VERSION 5.8 ;
BUSBITCHARS "[]" ;
DIVIDERCHAR "/" ;
UNITS
    DATABASE MICRONS 1000 ;
END UNITS

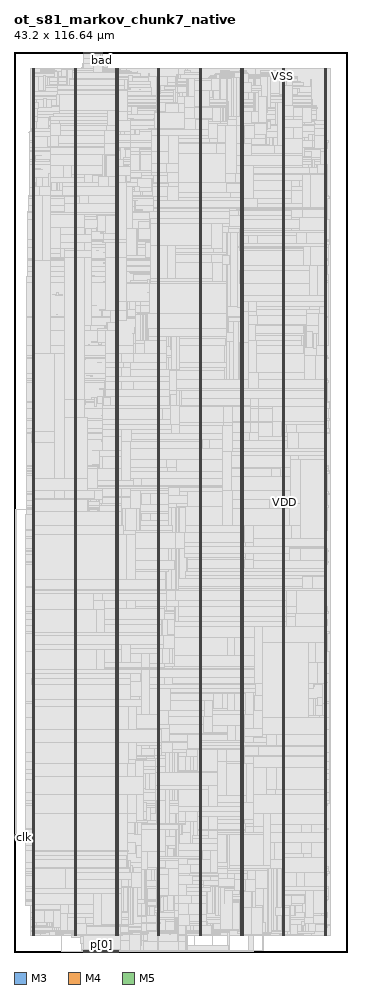
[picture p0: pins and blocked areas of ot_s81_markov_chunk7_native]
MACRO ot_s81_markov_chunk7_native
  FOREIGN ot_s81_markov_chunk7_native 0 0 ;
  CLASS BLOCK ;
  SIZE 43.2 BY 116.64 ;
  PIN bad
    DIRECTION OUTPUT ;
    USE SIGNAL ;
    PORT
      LAYER M3 ;
        RECT  11.448 116.496 11.466 116.64 ;
    END
  END bad
  PIN clk
    DIRECTION INPUT ;
    USE SIGNAL ;
    PORT
      LAYER M4 ;
        RECT  0 14.88 0.192 14.904 ;
    END
  END clk
  PIN p[0]
    DIRECTION INPUT ;
    USE SIGNAL ;
    PORT
      LAYER M3 ;
        RECT  11.304 0 11.322 0.144 ;
    END
  END p[0]
  PIN p[10]
    DIRECTION INPUT ;
    USE SIGNAL ;
    PORT
      LAYER M3 ;
        RECT  12.024 0 12.042 0.144 ;
    END
  END p[10]
  PIN p[11]
    DIRECTION INPUT ;
    USE SIGNAL ;
    PORT
      LAYER M5 ;
        RECT  12.048 0 12.072 0.192 ;
    END
  END p[11]
  PIN p[12]
    DIRECTION INPUT ;
    USE SIGNAL ;
    PORT
      LAYER M3 ;
        RECT  12.168 0 12.186 0.144 ;
    END
  END p[12]
  PIN p[13]
    DIRECTION INPUT ;
    USE SIGNAL ;
    PORT
      LAYER M5 ;
        RECT  12.192 0 12.216 0.192 ;
    END
  END p[13]
  PIN p[14]
    DIRECTION INPUT ;
    USE SIGNAL ;
    PORT
      LAYER M3 ;
        RECT  12.312 0 12.33 0.144 ;
    END
  END p[14]
  PIN p[15]
    DIRECTION INPUT ;
    USE SIGNAL ;
    PORT
      LAYER M5 ;
        RECT  12.336 0 12.36 0.192 ;
    END
  END p[15]
  PIN p[16]
    DIRECTION INPUT ;
    USE SIGNAL ;
    PORT
      LAYER M3 ;
        RECT  12.456 0 12.474 0.144 ;
    END
  END p[16]
  PIN p[17]
    DIRECTION INPUT ;
    USE SIGNAL ;
    PORT
      LAYER M5 ;
        RECT  12.48 0 12.504 0.192 ;
    END
  END p[17]
  PIN p[18]
    DIRECTION INPUT ;
    USE SIGNAL ;
    PORT
      LAYER M3 ;
        RECT  12.6 0 12.618 0.144 ;
    END
  END p[18]
  PIN p[19]
    DIRECTION INPUT ;
    USE SIGNAL ;
    PORT
      LAYER M5 ;
        RECT  12.624 0 12.648 0.192 ;
    END
  END p[19]
  PIN p[1]
    DIRECTION INPUT ;
    USE SIGNAL ;
    PORT
      LAYER M5 ;
        RECT  11.328 0 11.352 0.192 ;
    END
  END p[1]
  PIN p[20]
    DIRECTION INPUT ;
    USE SIGNAL ;
    PORT
      LAYER M3 ;
        RECT  12.744 0 12.762 0.144 ;
    END
  END p[20]
  PIN p[21]
    DIRECTION INPUT ;
    USE SIGNAL ;
    PORT
      LAYER M5 ;
        RECT  12.768 0 12.792 0.192 ;
    END
  END p[21]
  PIN p[22]
    DIRECTION INPUT ;
    USE SIGNAL ;
    PORT
      LAYER M3 ;
        RECT  12.888 0 12.906 0.144 ;
    END
  END p[22]
  PIN p[23]
    DIRECTION INPUT ;
    USE SIGNAL ;
    PORT
      LAYER M5 ;
        RECT  12.912 0 12.936 0.192 ;
    END
  END p[23]
  PIN p[24]
    DIRECTION INPUT ;
    USE SIGNAL ;
    PORT
      LAYER M3 ;
        RECT  13.032 0 13.05 0.144 ;
    END
    PORT
      LAYER M3 ;
        RECT  12.996 0.067 13.086 0.103 ;
    END
  END p[24]
  PIN p[25]
    DIRECTION INPUT ;
    USE SIGNAL ;
    PORT
      LAYER M5 ;
        RECT  13.056 0 13.08 0.192 ;
    END
  END p[25]
  PIN p[26]
    DIRECTION INPUT ;
    USE SIGNAL ;
    PORT
      LAYER M3 ;
        RECT  13.176 0 13.194 0.144 ;
    END
  END p[26]
  PIN p[27]
    DIRECTION INPUT ;
    USE SIGNAL ;
    PORT
      LAYER M5 ;
        RECT  13.2 0 13.224 0.192 ;
    END
  END p[27]
  PIN p[28]
    DIRECTION INPUT ;
    USE SIGNAL ;
    PORT
      LAYER M3 ;
        RECT  13.32 0 13.338 0.144 ;
    END
  END p[28]
  PIN p[29]
    DIRECTION INPUT ;
    USE SIGNAL ;
    PORT
      LAYER M5 ;
        RECT  13.344 0 13.368 0.192 ;
    END
  END p[29]
  PIN p[2]
    DIRECTION INPUT ;
    USE SIGNAL ;
    PORT
      LAYER M3 ;
        RECT  11.448 0 11.466 0.144 ;
    END
  END p[2]
  PIN p[30]
    DIRECTION INPUT ;
    USE SIGNAL ;
    PORT
      LAYER M3 ;
        RECT  13.464 0 13.482 0.144 ;
    END
  END p[30]
  PIN p[31]
    DIRECTION INPUT ;
    USE SIGNAL ;
    PORT
      LAYER M5 ;
        RECT  13.488 0 13.512 0.192 ;
    END
  END p[31]
  PIN p[3]
    DIRECTION INPUT ;
    USE SIGNAL ;
    PORT
      LAYER M5 ;
        RECT  11.472 0 11.496 0.192 ;
    END
  END p[3]
  PIN p[4]
    DIRECTION INPUT ;
    USE SIGNAL ;
    PORT
      LAYER M3 ;
        RECT  11.592 0 11.61 0.144 ;
    END
  END p[4]
  PIN p[5]
    DIRECTION INPUT ;
    USE SIGNAL ;
    PORT
      LAYER M5 ;
        RECT  11.616 0 11.64 0.192 ;
    END
  END p[5]
  PIN p[6]
    DIRECTION INPUT ;
    USE SIGNAL ;
    PORT
      LAYER M3 ;
        RECT  11.736 0 11.754 0.144 ;
    END
  END p[6]
  PIN p[7]
    DIRECTION INPUT ;
    USE SIGNAL ;
    PORT
      LAYER M5 ;
        RECT  11.76 0 11.784 0.192 ;
    END
  END p[7]
  PIN p[8]
    DIRECTION INPUT ;
    USE SIGNAL ;
    PORT
      LAYER M3 ;
        RECT  11.88 0 11.898 0.144 ;
    END
  END p[8]
  PIN p[9]
    DIRECTION INPUT ;
    USE SIGNAL ;
    PORT
      LAYER M5 ;
        RECT  11.904 0 11.928 0.192 ;
    END
  END p[9]
  PIN rst_n
    DIRECTION INPUT ;
    USE SIGNAL ;
    PORT
      LAYER M4 ;
        RECT  0 15.024 0.192 15.048 ;
    END
  END rst_n
  PIN sum[0]
    DIRECTION INPUT ;
    USE SIGNAL ;
    PORT
      LAYER M3 ;
        RECT  9 0 9.018 0.144 ;
    END
  END sum[0]
  PIN sum[10]
    DIRECTION INPUT ;
    USE SIGNAL ;
    PORT
      LAYER M3 ;
        RECT  9.72 0 9.738 0.144 ;
    END
  END sum[10]
  PIN sum[11]
    DIRECTION INPUT ;
    USE SIGNAL ;
    PORT
      LAYER M5 ;
        RECT  9.744 0 9.768 0.192 ;
    END
  END sum[11]
  PIN sum[12]
    DIRECTION INPUT ;
    USE SIGNAL ;
    PORT
      LAYER M3 ;
        RECT  9.864 0 9.882 0.144 ;
    END
  END sum[12]
  PIN sum[13]
    DIRECTION INPUT ;
    USE SIGNAL ;
    PORT
      LAYER M5 ;
        RECT  9.888 0 9.912 0.192 ;
    END
  END sum[13]
  PIN sum[14]
    DIRECTION INPUT ;
    USE SIGNAL ;
    PORT
      LAYER M3 ;
        RECT  10.008 0 10.026 0.144 ;
    END
  END sum[14]
  PIN sum[15]
    DIRECTION INPUT ;
    USE SIGNAL ;
    PORT
      LAYER M5 ;
        RECT  10.032 0 10.056 0.192 ;
    END
  END sum[15]
  PIN sum[16]
    DIRECTION INPUT ;
    USE SIGNAL ;
    PORT
      LAYER M3 ;
        RECT  10.152 0 10.17 0.144 ;
    END
  END sum[16]
  PIN sum[17]
    DIRECTION INPUT ;
    USE SIGNAL ;
    PORT
      LAYER M5 ;
        RECT  10.176 0 10.2 0.192 ;
    END
  END sum[17]
  PIN sum[18]
    DIRECTION INPUT ;
    USE SIGNAL ;
    PORT
      LAYER M3 ;
        RECT  10.296 0 10.314 0.144 ;
    END
  END sum[18]
  PIN sum[19]
    DIRECTION INPUT ;
    USE SIGNAL ;
    PORT
      LAYER M5 ;
        RECT  10.32 0 10.344 0.192 ;
    END
  END sum[19]
  PIN sum[1]
    DIRECTION INPUT ;
    USE SIGNAL ;
    PORT
      LAYER M5 ;
        RECT  9.024 0 9.048 0.192 ;
    END
  END sum[1]
  PIN sum[20]
    DIRECTION INPUT ;
    USE SIGNAL ;
    PORT
      LAYER M3 ;
        RECT  10.44 0 10.458 0.144 ;
    END
  END sum[20]
  PIN sum[21]
    DIRECTION INPUT ;
    USE SIGNAL ;
    PORT
      LAYER M5 ;
        RECT  10.464 0 10.488 0.192 ;
    END
  END sum[21]
  PIN sum[22]
    DIRECTION INPUT ;
    USE SIGNAL ;
    PORT
      LAYER M3 ;
        RECT  10.584 0 10.602 0.144 ;
    END
  END sum[22]
  PIN sum[23]
    DIRECTION INPUT ;
    USE SIGNAL ;
    PORT
      LAYER M5 ;
        RECT  10.608 0 10.632 0.192 ;
    END
  END sum[23]
  PIN sum[24]
    DIRECTION INPUT ;
    USE SIGNAL ;
    PORT
      LAYER M3 ;
        RECT  10.728 0 10.746 0.144 ;
    END
  END sum[24]
  PIN sum[25]
    DIRECTION INPUT ;
    USE SIGNAL ;
    PORT
      LAYER M5 ;
        RECT  10.752 0 10.776 0.192 ;
    END
  END sum[25]
  PIN sum[26]
    DIRECTION INPUT ;
    USE SIGNAL ;
    PORT
      LAYER M3 ;
        RECT  10.872 0 10.89 0.144 ;
    END
  END sum[26]
  PIN sum[27]
    DIRECTION INPUT ;
    USE SIGNAL ;
    PORT
      LAYER M5 ;
        RECT  10.896 0 10.92 0.192 ;
    END
  END sum[27]
  PIN sum[28]
    DIRECTION INPUT ;
    USE SIGNAL ;
    PORT
      LAYER M3 ;
        RECT  11.016 0 11.034 0.144 ;
    END
  END sum[28]
  PIN sum[29]
    DIRECTION INPUT ;
    USE SIGNAL ;
    PORT
      LAYER M5 ;
        RECT  11.04 0 11.064 0.192 ;
    END
  END sum[29]
  PIN sum[2]
    DIRECTION INPUT ;
    USE SIGNAL ;
    PORT
      LAYER M3 ;
        RECT  9.144 0 9.162 0.144 ;
    END
  END sum[2]
  PIN sum[30]
    DIRECTION INPUT ;
    USE SIGNAL ;
    PORT
      LAYER M3 ;
        RECT  11.16 0 11.178 0.144 ;
    END
  END sum[30]
  PIN sum[31]
    DIRECTION INPUT ;
    USE SIGNAL ;
    PORT
      LAYER M5 ;
        RECT  11.184 0 11.208 0.192 ;
    END
  END sum[31]
  PIN sum[3]
    DIRECTION INPUT ;
    USE SIGNAL ;
    PORT
      LAYER M5 ;
        RECT  9.168 0 9.192 0.192 ;
    END
  END sum[3]
  PIN sum[4]
    DIRECTION INPUT ;
    USE SIGNAL ;
    PORT
      LAYER M3 ;
        RECT  9.288 0 9.306 0.144 ;
    END
  END sum[4]
  PIN sum[5]
    DIRECTION INPUT ;
    USE SIGNAL ;
    PORT
      LAYER M5 ;
        RECT  9.312 0 9.336 0.192 ;
    END
  END sum[5]
  PIN sum[6]
    DIRECTION INPUT ;
    USE SIGNAL ;
    PORT
      LAYER M3 ;
        RECT  9.432 0 9.45 0.144 ;
    END
  END sum[6]
  PIN sum[7]
    DIRECTION INPUT ;
    USE SIGNAL ;
    PORT
      LAYER M5 ;
        RECT  9.456 0 9.48 0.192 ;
    END
  END sum[7]
  PIN sum[8]
    DIRECTION INPUT ;
    USE SIGNAL ;
    PORT
      LAYER M3 ;
        RECT  9.576 0 9.594 0.144 ;
    END
  END sum[8]
  PIN sum[9]
    DIRECTION INPUT ;
    USE SIGNAL ;
    PORT
      LAYER M5 ;
        RECT  9.6 0 9.624 0.192 ;
    END
  END sum[9]
  PIN vin
    DIRECTION INPUT ;
    USE SIGNAL ;
    PORT
      LAYER M4 ;
        RECT  0 15.168 0.192 15.192 ;
    END
  END vin
  PIN vout
    DIRECTION OUTPUT ;
    USE SIGNAL ;
    PORT
      LAYER M3 ;
        RECT  11.304 116.496 11.322 116.64 ;
    END
  END vout
  PIN y[0]
    DIRECTION OUTPUT ;
    USE SIGNAL ;
    PORT
      LAYER M3 ;
        RECT  9 116.496 9.018 116.64 ;
    END
  END y[0]
  PIN y[10]
    DIRECTION OUTPUT ;
    USE SIGNAL ;
    PORT
      LAYER M3 ;
        RECT  9.72 116.496 9.738 116.64 ;
    END
  END y[10]
  PIN y[11]
    DIRECTION OUTPUT ;
    USE SIGNAL ;
    PORT
      LAYER M5 ;
        RECT  9.744 116.448 9.768 116.64 ;
    END
  END y[11]
  PIN y[12]
    DIRECTION OUTPUT ;
    USE SIGNAL ;
    PORT
      LAYER M3 ;
        RECT  9.864 116.496 9.882 116.64 ;
    END
  END y[12]
  PIN y[13]
    DIRECTION OUTPUT ;
    USE SIGNAL ;
    PORT
      LAYER M5 ;
        RECT  9.888 116.448 9.912 116.64 ;
    END
  END y[13]
  PIN y[14]
    DIRECTION OUTPUT ;
    USE SIGNAL ;
    PORT
      LAYER M3 ;
        RECT  10.008 116.496 10.026 116.64 ;
    END
  END y[14]
  PIN y[15]
    DIRECTION OUTPUT ;
    USE SIGNAL ;
    PORT
      LAYER M5 ;
        RECT  10.032 116.448 10.056 116.64 ;
    END
  END y[15]
  PIN y[16]
    DIRECTION OUTPUT ;
    USE SIGNAL ;
    PORT
      LAYER M3 ;
        RECT  10.152 116.496 10.17 116.64 ;
    END
  END y[16]
  PIN y[17]
    DIRECTION OUTPUT ;
    USE SIGNAL ;
    PORT
      LAYER M5 ;
        RECT  10.176 116.448 10.2 116.64 ;
    END
  END y[17]
  PIN y[18]
    DIRECTION OUTPUT ;
    USE SIGNAL ;
    PORT
      LAYER M3 ;
        RECT  10.296 116.496 10.314 116.64 ;
    END
  END y[18]
  PIN y[19]
    DIRECTION OUTPUT ;
    USE SIGNAL ;
    PORT
      LAYER M5 ;
        RECT  10.32 116.448 10.344 116.64 ;
    END
  END y[19]
  PIN y[1]
    DIRECTION OUTPUT ;
    USE SIGNAL ;
    PORT
      LAYER M5 ;
        RECT  9.024 116.448 9.048 116.64 ;
    END
  END y[1]
  PIN y[20]
    DIRECTION OUTPUT ;
    USE SIGNAL ;
    PORT
      LAYER M3 ;
        RECT  10.44 116.496 10.458 116.64 ;
    END
  END y[20]
  PIN y[21]
    DIRECTION OUTPUT ;
    USE SIGNAL ;
    PORT
      LAYER M5 ;
        RECT  10.464 116.448 10.488 116.64 ;
    END
  END y[21]
  PIN y[22]
    DIRECTION OUTPUT ;
    USE SIGNAL ;
    PORT
      LAYER M3 ;
        RECT  10.584 116.496 10.602 116.64 ;
    END
  END y[22]
  PIN y[23]
    DIRECTION OUTPUT ;
    USE SIGNAL ;
    PORT
      LAYER M5 ;
        RECT  10.608 116.448 10.632 116.64 ;
    END
  END y[23]
  PIN y[24]
    DIRECTION OUTPUT ;
    USE SIGNAL ;
    PORT
      LAYER M3 ;
        RECT  10.728 116.496 10.746 116.64 ;
    END
  END y[24]
  PIN y[25]
    DIRECTION OUTPUT ;
    USE SIGNAL ;
    PORT
      LAYER M5 ;
        RECT  10.752 116.448 10.776 116.64 ;
    END
  END y[25]
  PIN y[26]
    DIRECTION OUTPUT ;
    USE SIGNAL ;
    PORT
      LAYER M3 ;
        RECT  10.872 116.496 10.89 116.64 ;
    END
  END y[26]
  PIN y[27]
    DIRECTION OUTPUT ;
    USE SIGNAL ;
    PORT
      LAYER M5 ;
        RECT  10.896 116.448 10.92 116.64 ;
    END
  END y[27]
  PIN y[28]
    DIRECTION OUTPUT ;
    USE SIGNAL ;
    PORT
      LAYER M3 ;
        RECT  11.016 116.496 11.034 116.64 ;
    END
  END y[28]
  PIN y[29]
    DIRECTION OUTPUT ;
    USE SIGNAL ;
    PORT
      LAYER M5 ;
        RECT  11.04 116.448 11.064 116.64 ;
    END
  END y[29]
  PIN y[2]
    DIRECTION OUTPUT ;
    USE SIGNAL ;
    PORT
      LAYER M3 ;
        RECT  9.144 116.496 9.162 116.64 ;
    END
  END y[2]
  PIN y[30]
    DIRECTION OUTPUT ;
    USE SIGNAL ;
    PORT
      LAYER M3 ;
        RECT  11.16 116.496 11.178 116.64 ;
    END
  END y[30]
  PIN y[31]
    DIRECTION OUTPUT ;
    USE SIGNAL ;
    PORT
      LAYER M5 ;
        RECT  11.184 116.448 11.208 116.64 ;
    END
  END y[31]
  PIN y[3]
    DIRECTION OUTPUT ;
    USE SIGNAL ;
    PORT
      LAYER M5 ;
        RECT  9.168 116.448 9.192 116.64 ;
    END
  END y[3]
  PIN y[4]
    DIRECTION OUTPUT ;
    USE SIGNAL ;
    PORT
      LAYER M3 ;
        RECT  9.288 116.496 9.306 116.64 ;
    END
  END y[4]
  PIN y[5]
    DIRECTION OUTPUT ;
    USE SIGNAL ;
    PORT
      LAYER M5 ;
        RECT  9.312 116.448 9.336 116.64 ;
    END
  END y[5]
  PIN y[6]
    DIRECTION OUTPUT ;
    USE SIGNAL ;
    PORT
      LAYER M3 ;
        RECT  9.432 116.496 9.45 116.64 ;
    END
  END y[6]
  PIN y[7]
    DIRECTION OUTPUT ;
    USE SIGNAL ;
    PORT
      LAYER M5 ;
        RECT  9.456 116.448 9.48 116.64 ;
    END
  END y[7]
  PIN y[8]
    DIRECTION OUTPUT ;
    USE SIGNAL ;
    PORT
      LAYER M3 ;
        RECT  9.576 116.496 9.594 116.64 ;
    END
    PORT
      LAYER M3 ;
        RECT  9.54 116.508 9.666 116.573 ;
    END
  END y[8]
  PIN y[9]
    DIRECTION OUTPUT ;
    USE SIGNAL ;
    PORT
      LAYER M5 ;
        RECT  9.6 116.448 9.624 116.64 ;
    END
  END y[9]
  PIN VDD
    DIRECTION INOUT ;
    USE POWER ;
    PORT
      LAYER M5 ;
        RECT  40.392 2.151 40.512 114.489 ;
        RECT  34.992 2.151 35.112 114.489 ;
        RECT  29.592 2.151 29.712 114.489 ;
        RECT  24.192 2.151 24.312 114.489 ;
        RECT  18.792 2.151 18.912 114.489 ;
        RECT  13.392 2.151 13.512 114.489 ;
        RECT  7.992 2.151 8.112 114.489 ;
        RECT  2.592 2.151 2.712 114.489 ;
    END
  END VDD
  PIN VSS
    DIRECTION INOUT ;
    USE GROUND ;
    PORT
      LAYER M5 ;
        RECT  40.2 2.137 40.32 114.503 ;
        RECT  34.8 2.137 34.92 114.503 ;
        RECT  29.4 2.137 29.52 114.503 ;
        RECT  24 2.137 24.12 114.503 ;
        RECT  18.6 2.137 18.72 114.503 ;
        RECT  13.2 2.137 13.32 114.503 ;
        RECT  7.8 2.137 7.92 114.503 ;
        RECT  2.4 2.137 2.52 114.503 ;
    END
  END VSS
  # OT_OBS_CLOSED layer=M5 d_um=1.536 added=357
  OBS
    LAYER RVTN ;
     RECT  2.16 2.16 41.04 2.295 ;
     RECT  2.16 2.565 41.04 2.835 ;
     RECT  2.16 3.105 41.04 3.375 ;
     RECT  2.16 3.645 41.04 3.915 ;
     RECT  2.16 4.185 41.04 4.455 ;
     RECT  2.16 4.725 41.04 4.995 ;
     RECT  2.16 5.265 41.04 5.535 ;
     RECT  2.16 5.805 41.04 6.075 ;
     RECT  2.16 6.345 41.04 6.615 ;
     RECT  2.16 6.885 41.04 7.155 ;
     RECT  2.16 7.425 41.04 7.695 ;
     RECT  2.16 7.965 41.04 8.235 ;
     RECT  2.16 8.505 41.04 8.775 ;
     RECT  2.16 9.045 41.04 9.315 ;
     RECT  2.16 9.585 41.04 9.855 ;
     RECT  2.16 10.125 41.04 10.395 ;
     RECT  2.16 10.665 41.04 10.935 ;
     RECT  2.16 11.205 41.04 11.475 ;
     RECT  2.16 11.745 41.04 12.015 ;
     RECT  2.16 12.285 41.04 12.555 ;
     RECT  2.16 12.825 41.04 13.095 ;
     RECT  2.16 13.365 41.04 13.635 ;
     RECT  2.16 13.905 41.04 14.175 ;
     RECT  2.16 14.445 41.04 14.715 ;
     RECT  2.16 14.985 41.04 15.255 ;
     RECT  2.16 15.525 41.04 15.795 ;
     RECT  2.16 16.065 41.04 16.335 ;
     RECT  2.16 16.605 41.04 16.875 ;
     RECT  2.16 17.145 41.04 17.415 ;
     RECT  2.16 17.685 41.04 17.955 ;
     RECT  2.16 18.225 41.04 18.495 ;
     RECT  2.16 18.765 41.04 19.035 ;
     RECT  2.16 19.305 41.04 19.575 ;
     RECT  2.16 19.845 41.04 20.115 ;
     RECT  2.16 20.385 41.04 20.655 ;
     RECT  2.16 20.925 41.04 21.195 ;
     RECT  2.16 21.465 41.04 21.735 ;
     RECT  2.16 22.005 41.04 22.275 ;
     RECT  2.16 22.545 41.04 22.815 ;
     RECT  2.16 23.085 41.04 23.355 ;
     RECT  2.16 23.625 41.04 23.895 ;
     RECT  2.16 24.165 41.04 24.435 ;
     RECT  2.16 24.705 41.04 24.975 ;
     RECT  2.16 25.245 41.04 25.515 ;
     RECT  2.16 25.785 41.04 26.055 ;
     RECT  2.16 26.325 41.04 26.595 ;
     RECT  2.16 26.865 41.04 27.135 ;
     RECT  2.16 27.405 41.04 27.675 ;
     RECT  2.16 27.945 41.04 28.215 ;
     RECT  2.16 28.485 41.04 28.755 ;
     RECT  2.16 29.025 41.04 29.295 ;
     RECT  2.16 29.565 41.04 29.835 ;
     RECT  2.16 30.105 41.04 30.375 ;
     RECT  2.16 30.645 41.04 30.915 ;
     RECT  2.16 31.185 41.04 31.455 ;
     RECT  2.16 31.725 41.04 31.995 ;
     RECT  2.16 32.265 41.04 32.535 ;
     RECT  2.16 32.805 41.04 33.075 ;
     RECT  2.16 33.345 41.04 33.615 ;
     RECT  2.16 33.885 41.04 34.155 ;
     RECT  2.16 34.425 41.04 34.695 ;
     RECT  2.16 34.965 41.04 35.235 ;
     RECT  2.16 35.505 41.04 35.775 ;
     RECT  2.16 36.045 41.04 36.315 ;
     RECT  2.16 36.585 41.04 36.855 ;
     RECT  2.16 37.125 41.04 37.395 ;
     RECT  2.16 37.665 41.04 37.935 ;
     RECT  2.16 38.205 41.04 38.475 ;
     RECT  2.16 38.745 41.04 39.015 ;
     RECT  2.16 39.285 41.04 39.555 ;
     RECT  2.16 39.825 41.04 40.095 ;
     RECT  2.16 40.365 41.04 40.635 ;
     RECT  2.16 40.905 41.04 41.175 ;
     RECT  2.16 41.445 41.04 41.715 ;
     RECT  2.16 41.985 41.04 42.255 ;
     RECT  2.16 42.525 41.04 42.795 ;
     RECT  2.16 43.065 41.04 43.335 ;
     RECT  2.16 43.605 41.04 43.875 ;
     RECT  2.16 44.145 41.04 44.415 ;
     RECT  2.16 44.685 41.04 44.955 ;
     RECT  2.16 45.225 41.04 45.495 ;
     RECT  2.16 45.765 41.04 46.035 ;
     RECT  2.16 46.305 41.04 46.575 ;
     RECT  2.16 46.845 41.04 47.115 ;
     RECT  2.16 47.385 41.04 47.655 ;
     RECT  2.16 47.925 41.04 48.195 ;
     RECT  2.16 48.465 41.04 48.735 ;
     RECT  2.16 49.005 41.04 49.275 ;
     RECT  2.16 49.545 41.04 49.815 ;
     RECT  2.16 50.085 41.04 50.355 ;
     RECT  2.16 50.625 41.04 50.895 ;
     RECT  2.16 51.165 41.04 51.435 ;
     RECT  2.16 51.705 41.04 51.975 ;
     RECT  2.16 52.245 41.04 52.515 ;
     RECT  2.16 52.785 41.04 53.055 ;
     RECT  2.16 53.325 41.04 53.595 ;
     RECT  2.16 53.865 41.04 54.135 ;
     RECT  2.16 54.405 41.04 54.675 ;
     RECT  2.16 54.945 41.04 55.215 ;
     RECT  2.16 55.485 41.04 55.755 ;
     RECT  2.16 56.025 41.04 56.295 ;
     RECT  2.16 56.565 41.04 56.835 ;
     RECT  2.16 57.105 41.04 57.375 ;
     RECT  2.16 57.645 41.04 57.915 ;
     RECT  2.16 58.185 41.04 58.455 ;
     RECT  2.16 58.725 41.04 58.995 ;
     RECT  2.16 59.265 41.04 59.535 ;
     RECT  2.16 59.805 41.04 60.075 ;
     RECT  2.16 60.345 41.04 60.615 ;
     RECT  2.16 60.885 41.04 61.155 ;
     RECT  2.16 61.425 41.04 61.695 ;
     RECT  2.16 61.965 41.04 62.235 ;
     RECT  2.16 62.505 41.04 62.775 ;
     RECT  2.16 63.045 41.04 63.315 ;
     RECT  2.16 63.585 41.04 63.855 ;
     RECT  2.16 64.125 41.04 64.395 ;
     RECT  2.16 64.665 41.04 64.935 ;
     RECT  2.16 65.205 41.04 65.475 ;
     RECT  2.16 65.745 41.04 66.015 ;
     RECT  2.16 66.285 41.04 66.555 ;
     RECT  2.16 66.825 41.04 67.095 ;
     RECT  2.16 67.365 41.04 67.635 ;
     RECT  2.16 67.905 41.04 68.175 ;
     RECT  2.16 68.445 41.04 68.715 ;
     RECT  2.16 68.985 41.04 69.255 ;
     RECT  2.16 69.525 41.04 69.795 ;
     RECT  2.16 70.065 41.04 70.335 ;
     RECT  2.16 70.605 41.04 70.875 ;
     RECT  2.16 71.145 41.04 71.415 ;
     RECT  2.16 71.685 41.04 71.955 ;
     RECT  2.16 72.225 41.04 72.495 ;
     RECT  2.16 72.765 41.04 73.035 ;
     RECT  2.16 73.305 41.04 73.575 ;
     RECT  2.16 73.845 41.04 74.115 ;
     RECT  2.16 74.385 41.04 74.655 ;
     RECT  2.16 74.925 41.04 75.195 ;
     RECT  2.16 75.465 41.04 75.735 ;
     RECT  2.16 76.005 41.04 76.275 ;
     RECT  2.16 76.545 41.04 76.815 ;
     RECT  2.16 77.085 41.04 77.355 ;
     RECT  2.16 77.625 41.04 77.895 ;
     RECT  2.16 78.165 41.04 78.435 ;
     RECT  2.16 78.705 41.04 78.975 ;
     RECT  2.16 79.245 41.04 79.515 ;
     RECT  2.16 79.785 41.04 80.055 ;
     RECT  2.16 80.325 41.04 80.595 ;
     RECT  2.16 80.865 41.04 81.135 ;
     RECT  2.16 81.405 41.04 81.675 ;
     RECT  2.16 81.945 41.04 82.215 ;
     RECT  2.16 82.485 41.04 82.755 ;
     RECT  2.16 83.025 41.04 83.295 ;
     RECT  2.16 83.565 41.04 83.835 ;
     RECT  2.16 84.105 41.04 84.375 ;
     RECT  2.16 84.645 41.04 84.915 ;
     RECT  2.16 85.185 41.04 85.455 ;
     RECT  2.16 85.725 41.04 85.995 ;
     RECT  2.16 86.265 41.04 86.535 ;
     RECT  2.16 86.805 41.04 87.075 ;
     RECT  2.16 87.345 41.04 87.615 ;
     RECT  2.16 87.885 41.04 88.155 ;
     RECT  2.16 88.425 41.04 88.695 ;
     RECT  2.16 88.965 41.04 89.235 ;
     RECT  2.16 89.505 41.04 89.775 ;
     RECT  2.16 90.045 41.04 90.315 ;
     RECT  2.16 90.585 41.04 90.855 ;
     RECT  2.16 91.125 41.04 91.395 ;
     RECT  2.16 91.665 41.04 91.935 ;
     RECT  2.16 92.205 41.04 92.475 ;
     RECT  2.16 92.745 41.04 93.015 ;
     RECT  2.16 93.285 41.04 93.555 ;
     RECT  2.16 93.825 41.04 94.095 ;
     RECT  2.16 94.365 41.04 94.635 ;
     RECT  2.16 94.905 41.04 95.175 ;
     RECT  2.16 95.445 41.04 95.715 ;
     RECT  2.16 95.985 41.04 96.255 ;
     RECT  2.16 96.525 41.04 96.795 ;
     RECT  2.16 97.065 41.04 97.335 ;
     RECT  2.16 97.605 41.04 97.875 ;
     RECT  2.16 98.145 41.04 98.415 ;
     RECT  2.16 98.685 41.04 98.955 ;
     RECT  2.16 99.225 41.04 99.495 ;
     RECT  2.16 99.765 41.04 100.035 ;
     RECT  2.16 100.305 41.04 100.575 ;
     RECT  2.16 100.845 41.04 101.115 ;
     RECT  2.16 101.385 41.04 101.655 ;
     RECT  2.16 101.925 41.04 102.195 ;
     RECT  2.16 102.465 41.04 102.735 ;
     RECT  2.16 103.005 41.04 103.275 ;
     RECT  2.16 103.545 41.04 103.815 ;
     RECT  2.16 104.085 41.04 104.355 ;
     RECT  2.16 104.625 41.04 104.895 ;
     RECT  2.16 105.165 41.04 105.435 ;
     RECT  2.16 105.705 41.04 105.975 ;
     RECT  2.16 106.245 41.04 106.515 ;
     RECT  2.16 106.785 41.04 107.055 ;
     RECT  2.16 107.325 41.04 107.595 ;
     RECT  2.16 107.865 41.04 108.135 ;
     RECT  2.16 108.405 41.04 108.675 ;
     RECT  2.16 108.945 41.04 109.215 ;
     RECT  2.16 109.485 41.04 109.755 ;
     RECT  2.16 110.025 41.04 110.295 ;
     RECT  2.16 110.565 41.04 110.835 ;
     RECT  2.16 111.105 41.04 111.375 ;
     RECT  2.16 111.645 41.04 111.915 ;
     RECT  2.16 112.185 41.04 112.455 ;
     RECT  2.16 112.725 41.04 112.995 ;
     RECT  2.16 113.265 41.04 113.535 ;
     RECT  2.16 113.805 41.04 114.075 ;
     RECT  2.16 114.345 41.04 114.48 ;
    LAYER RVTP ;
     RECT  2.16 2.295 41.04 2.565 ;
     RECT  2.16 2.835 41.04 3.105 ;
     RECT  2.16 3.375 41.04 3.645 ;
     RECT  2.16 3.915 41.04 4.185 ;
     RECT  2.16 4.455 41.04 4.725 ;
     RECT  2.16 4.995 41.04 5.265 ;
     RECT  2.16 5.535 41.04 5.805 ;
     RECT  2.16 6.075 41.04 6.345 ;
     RECT  2.16 6.615 41.04 6.885 ;
     RECT  2.16 7.155 41.04 7.425 ;
     RECT  2.16 7.695 41.04 7.965 ;
     RECT  2.16 8.235 41.04 8.505 ;
     RECT  2.16 8.775 41.04 9.045 ;
     RECT  2.16 9.315 41.04 9.585 ;
     RECT  2.16 9.855 41.04 10.125 ;
     RECT  2.16 10.395 41.04 10.665 ;
     RECT  2.16 10.935 41.04 11.205 ;
     RECT  2.16 11.475 41.04 11.745 ;
     RECT  2.16 12.015 41.04 12.285 ;
     RECT  2.16 12.555 41.04 12.825 ;
     RECT  2.16 13.095 41.04 13.365 ;
     RECT  2.16 13.635 41.04 13.905 ;
     RECT  2.16 14.175 41.04 14.445 ;
     RECT  2.16 14.715 41.04 14.985 ;
     RECT  2.16 15.255 41.04 15.525 ;
     RECT  2.16 15.795 41.04 16.065 ;
     RECT  2.16 16.335 41.04 16.605 ;
     RECT  2.16 16.875 41.04 17.145 ;
     RECT  2.16 17.415 41.04 17.685 ;
     RECT  2.16 17.955 41.04 18.225 ;
     RECT  2.16 18.495 41.04 18.765 ;
     RECT  2.16 19.035 41.04 19.305 ;
     RECT  2.16 19.575 41.04 19.845 ;
     RECT  2.16 20.115 41.04 20.385 ;
     RECT  2.16 20.655 41.04 20.925 ;
     RECT  2.16 21.195 41.04 21.465 ;
     RECT  2.16 21.735 41.04 22.005 ;
     RECT  2.16 22.275 41.04 22.545 ;
     RECT  2.16 22.815 41.04 23.085 ;
     RECT  2.16 23.355 41.04 23.625 ;
     RECT  2.16 23.895 41.04 24.165 ;
     RECT  2.16 24.435 41.04 24.705 ;
     RECT  2.16 24.975 41.04 25.245 ;
     RECT  2.16 25.515 41.04 25.785 ;
     RECT  2.16 26.055 41.04 26.325 ;
     RECT  2.16 26.595 41.04 26.865 ;
     RECT  2.16 27.135 41.04 27.405 ;
     RECT  2.16 27.675 41.04 27.945 ;
     RECT  2.16 28.215 41.04 28.485 ;
     RECT  2.16 28.755 41.04 29.025 ;
     RECT  2.16 29.295 41.04 29.565 ;
     RECT  2.16 29.835 41.04 30.105 ;
     RECT  2.16 30.375 41.04 30.645 ;
     RECT  2.16 30.915 41.04 31.185 ;
     RECT  2.16 31.455 41.04 31.725 ;
     RECT  2.16 31.995 41.04 32.265 ;
     RECT  2.16 32.535 41.04 32.805 ;
     RECT  2.16 33.075 41.04 33.345 ;
     RECT  2.16 33.615 41.04 33.885 ;
     RECT  2.16 34.155 41.04 34.425 ;
     RECT  2.16 34.695 41.04 34.965 ;
     RECT  2.16 35.235 41.04 35.505 ;
     RECT  2.16 35.775 41.04 36.045 ;
     RECT  2.16 36.315 41.04 36.585 ;
     RECT  2.16 36.855 41.04 37.125 ;
     RECT  2.16 37.395 41.04 37.665 ;
     RECT  2.16 37.935 41.04 38.205 ;
     RECT  2.16 38.475 41.04 38.745 ;
     RECT  2.16 39.015 41.04 39.285 ;
     RECT  2.16 39.555 41.04 39.825 ;
     RECT  2.16 40.095 41.04 40.365 ;
     RECT  2.16 40.635 41.04 40.905 ;
     RECT  2.16 41.175 41.04 41.445 ;
     RECT  2.16 41.715 41.04 41.985 ;
     RECT  2.16 42.255 41.04 42.525 ;
     RECT  2.16 42.795 41.04 43.065 ;
     RECT  2.16 43.335 41.04 43.605 ;
     RECT  2.16 43.875 41.04 44.145 ;
     RECT  2.16 44.415 41.04 44.685 ;
     RECT  2.16 44.955 41.04 45.225 ;
     RECT  2.16 45.495 41.04 45.765 ;
     RECT  2.16 46.035 41.04 46.305 ;
     RECT  2.16 46.575 41.04 46.845 ;
     RECT  2.16 47.115 41.04 47.385 ;
     RECT  2.16 47.655 41.04 47.925 ;
     RECT  2.16 48.195 41.04 48.465 ;
     RECT  2.16 48.735 41.04 49.005 ;
     RECT  2.16 49.275 41.04 49.545 ;
     RECT  2.16 49.815 41.04 50.085 ;
     RECT  2.16 50.355 41.04 50.625 ;
     RECT  2.16 50.895 41.04 51.165 ;
     RECT  2.16 51.435 41.04 51.705 ;
     RECT  2.16 51.975 41.04 52.245 ;
     RECT  2.16 52.515 41.04 52.785 ;
     RECT  2.16 53.055 41.04 53.325 ;
     RECT  2.16 53.595 41.04 53.865 ;
     RECT  2.16 54.135 41.04 54.405 ;
     RECT  2.16 54.675 41.04 54.945 ;
     RECT  2.16 55.215 41.04 55.485 ;
     RECT  2.16 55.755 41.04 56.025 ;
     RECT  2.16 56.295 41.04 56.565 ;
     RECT  2.16 56.835 41.04 57.105 ;
     RECT  2.16 57.375 41.04 57.645 ;
     RECT  2.16 57.915 41.04 58.185 ;
     RECT  2.16 58.455 41.04 58.725 ;
     RECT  2.16 58.995 41.04 59.265 ;
     RECT  2.16 59.535 41.04 59.805 ;
     RECT  2.16 60.075 41.04 60.345 ;
     RECT  2.16 60.615 41.04 60.885 ;
     RECT  2.16 61.155 41.04 61.425 ;
     RECT  2.16 61.695 41.04 61.965 ;
     RECT  2.16 62.235 41.04 62.505 ;
     RECT  2.16 62.775 41.04 63.045 ;
     RECT  2.16 63.315 41.04 63.585 ;
     RECT  2.16 63.855 41.04 64.125 ;
     RECT  2.16 64.395 41.04 64.665 ;
     RECT  2.16 64.935 41.04 65.205 ;
     RECT  2.16 65.475 41.04 65.745 ;
     RECT  2.16 66.015 41.04 66.285 ;
     RECT  2.16 66.555 41.04 66.825 ;
     RECT  2.16 67.095 41.04 67.365 ;
     RECT  2.16 67.635 41.04 67.905 ;
     RECT  2.16 68.175 41.04 68.445 ;
     RECT  2.16 68.715 41.04 68.985 ;
     RECT  2.16 69.255 41.04 69.525 ;
     RECT  2.16 69.795 41.04 70.065 ;
     RECT  2.16 70.335 41.04 70.605 ;
     RECT  2.16 70.875 41.04 71.145 ;
     RECT  2.16 71.415 41.04 71.685 ;
     RECT  2.16 71.955 41.04 72.225 ;
     RECT  2.16 72.495 41.04 72.765 ;
     RECT  2.16 73.035 41.04 73.305 ;
     RECT  2.16 73.575 41.04 73.845 ;
     RECT  2.16 74.115 41.04 74.385 ;
     RECT  2.16 74.655 41.04 74.925 ;
     RECT  2.16 75.195 41.04 75.465 ;
     RECT  2.16 75.735 41.04 76.005 ;
     RECT  2.16 76.275 41.04 76.545 ;
     RECT  2.16 76.815 41.04 77.085 ;
     RECT  2.16 77.355 41.04 77.625 ;
     RECT  2.16 77.895 41.04 78.165 ;
     RECT  2.16 78.435 41.04 78.705 ;
     RECT  2.16 78.975 41.04 79.245 ;
     RECT  2.16 79.515 41.04 79.785 ;
     RECT  2.16 80.055 41.04 80.325 ;
     RECT  2.16 80.595 41.04 80.865 ;
     RECT  2.16 81.135 41.04 81.405 ;
     RECT  2.16 81.675 41.04 81.945 ;
     RECT  2.16 82.215 41.04 82.485 ;
     RECT  2.16 82.755 41.04 83.025 ;
     RECT  2.16 83.295 41.04 83.565 ;
     RECT  2.16 83.835 41.04 84.105 ;
     RECT  2.16 84.375 41.04 84.645 ;
     RECT  2.16 84.915 41.04 85.185 ;
     RECT  2.16 85.455 41.04 85.725 ;
     RECT  2.16 85.995 41.04 86.265 ;
     RECT  2.16 86.535 41.04 86.805 ;
     RECT  2.16 87.075 41.04 87.345 ;
     RECT  2.16 87.615 41.04 87.885 ;
     RECT  2.16 88.155 41.04 88.425 ;
     RECT  2.16 88.695 41.04 88.965 ;
     RECT  2.16 89.235 41.04 89.505 ;
     RECT  2.16 89.775 41.04 90.045 ;
     RECT  2.16 90.315 41.04 90.585 ;
     RECT  2.16 90.855 41.04 91.125 ;
     RECT  2.16 91.395 41.04 91.665 ;
     RECT  2.16 91.935 41.04 92.205 ;
     RECT  2.16 92.475 41.04 92.745 ;
     RECT  2.16 93.015 41.04 93.285 ;
     RECT  2.16 93.555 41.04 93.825 ;
     RECT  2.16 94.095 41.04 94.365 ;
     RECT  2.16 94.635 41.04 94.905 ;
     RECT  2.16 95.175 41.04 95.445 ;
     RECT  2.16 95.715 41.04 95.985 ;
     RECT  2.16 96.255 41.04 96.525 ;
     RECT  2.16 96.795 41.04 97.065 ;
     RECT  2.16 97.335 41.04 97.605 ;
     RECT  2.16 97.875 41.04 98.145 ;
     RECT  2.16 98.415 41.04 98.685 ;
     RECT  2.16 98.955 41.04 99.225 ;
     RECT  2.16 99.495 41.04 99.765 ;
     RECT  2.16 100.035 41.04 100.305 ;
     RECT  2.16 100.575 41.04 100.845 ;
     RECT  2.16 101.115 41.04 101.385 ;
     RECT  2.16 101.655 41.04 101.925 ;
     RECT  2.16 102.195 41.04 102.465 ;
     RECT  2.16 102.735 41.04 103.005 ;
     RECT  2.16 103.275 41.04 103.545 ;
     RECT  2.16 103.815 41.04 104.085 ;
     RECT  2.16 104.355 41.04 104.625 ;
     RECT  2.16 104.895 41.04 105.165 ;
     RECT  2.16 105.435 41.04 105.705 ;
     RECT  2.16 105.975 41.04 106.245 ;
     RECT  2.16 106.515 41.04 106.785 ;
     RECT  2.16 107.055 41.04 107.325 ;
     RECT  2.16 107.595 41.04 107.865 ;
     RECT  2.16 108.135 41.04 108.405 ;
     RECT  2.16 108.675 41.04 108.945 ;
     RECT  2.16 109.215 41.04 109.485 ;
     RECT  2.16 109.755 41.04 110.025 ;
     RECT  2.16 110.295 41.04 110.565 ;
     RECT  2.16 110.835 41.04 111.105 ;
     RECT  2.16 111.375 41.04 111.645 ;
     RECT  2.16 111.915 41.04 112.185 ;
     RECT  2.16 112.455 41.04 112.725 ;
     RECT  2.16 112.995 41.04 113.265 ;
     RECT  2.16 113.535 41.04 113.805 ;
     RECT  2.16 114.075 41.04 114.345 ;
    LAYER M1 ;
     RECT  2.16 2.151 41.04 114.489 ;
    LAYER M2 ;
     RECT  1.543 14.616 1.651 14.634 ;
     RECT  1.579 12.906 1.687 12.924 ;
     RECT  1.507 6.084 1.831 6.102 ;
     RECT  1.687 95.994 1.867 96.012 ;
     RECT  1.903 57.816 1.939 57.834 ;
     RECT  1.903 11.286 1.975 11.304 ;
     RECT  1.615 9.936 2.011 9.954 ;
     RECT  1.687 12.906 2.047 13.392 ;
     RECT  2.083 2.646 2.16 2.664 ;
     RECT  1.831 6.084 2.16 6.174 ;
     RECT  1.939 7.776 2.16 7.794 ;
     RECT  2.011 9.936 2.16 10.224 ;
     RECT  1.975 11.016 2.16 11.304 ;
     RECT  2.047 12.366 2.16 13.392 ;
     RECT  1.651 14.616 2.16 15.318 ;
     RECT  1.975 26.64 2.16 26.658 ;
     RECT  1.975 34.506 2.16 34.524 ;
     RECT  1.507 36.018 2.16 36.036 ;
     RECT  1.867 51.516 2.16 51.534 ;
     RECT  1.939 54.954 2.16 54.972 ;
     RECT  1.543 56.736 2.16 56.754 ;
     RECT  1.939 57.816 2.16 58.014 ;
     RECT  2.011 61.056 2.16 61.074 ;
     RECT  1.579 62.676 2.16 62.694 ;
     RECT  2.047 64.638 2.16 64.656 ;
     RECT  1.615 67.266 2.16 67.284 ;
     RECT  2.047 68.346 2.16 68.364 ;
     RECT  2.083 80.91 2.16 80.928 ;
     RECT  1.975 84.006 2.16 84.024 ;
     RECT  1.651 87.516 2.16 87.534 ;
     RECT  2.047 88.362 2.16 88.38 ;
     RECT  2.119 90.486 2.16 90.504 ;
     RECT  1.867 95.994 2.16 96.084 ;
     RECT  1.831 98.046 2.16 98.064 ;
     RECT  2.155 104.67 2.16 104.688 ;
     RECT  1.939 106.254 2.16 106.272 ;
     RECT  2.16 2.151 3.487 114.489 ;
     RECT  3.487 2.151 4.559 114.534 ;
     RECT  4.559 2.151 6.187 114.489 ;
     RECT  6.187 2.151 7.411 114.534 ;
     RECT  7.411 1.881 8.635 114.534 ;
     RECT  6.187 0.036 8.707 0.054 ;
     RECT  8.635 1.152 8.735 114.534 ;
     RECT  8.735 1.881 8.843 114.534 ;
     RECT  8.707 0.036 9.023 0.162 ;
     RECT  9.139 115.821 9.427 115.839 ;
     RECT  9.427 115.821 9.455 115.92 ;
     RECT  9.455 115.902 9.527 115.92 ;
     RECT  9.535 116.478 9.671 116.568 ;
     RECT  8.843 1.881 9.751 114.489 ;
     RECT  9.751 1.881 9.787 114.678 ;
     RECT  9.787 1.881 10.175 114.759 ;
     RECT  9.023 0.036 10.867 0.054 ;
     RECT  10.867 0.036 10.967 0.162 ;
     RECT  10.175 1.881 11.183 114.642 ;
     RECT  11.183 2.151 11.399 114.606 ;
     RECT  11.011 115.821 11.507 115.839 ;
     RECT  11.399 2.151 11.939 114.57 ;
     RECT  11.731 0.306 12.163 0.324 ;
     RECT  12.163 0.144 12.307 0.324 ;
     RECT  12.307 0.144 12.595 0.864 ;
     RECT  12.595 0.144 12.991 1.17 ;
     RECT  12.991 0.036 13.171 1.17 ;
     RECT  11.939 2.151 13.171 114.534 ;
     RECT  13.171 0.036 13.739 114.534 ;
     RECT  13.739 0.036 21.263 114.489 ;
     RECT  21.263 1.422 22.487 114.489 ;
     RECT  21.263 0.036 26.779 0.162 ;
     RECT  26.779 0.036 30.731 0.234 ;
     RECT  30.731 0.036 30.983 0.054 ;
     RECT  22.487 2.106 31.271 114.489 ;
     RECT  31.271 2.151 41.04 114.489 ;
    LAYER M3 ;
     RECT  12.996 0.031 13.014 0.067 ;
     RECT  30.96 0.031 30.978 0.067 ;
     RECT  10.944 0.031 10.962 0.108 ;
     RECT  12.996 0.103 13.41 0.108 ;
     RECT  9 0.108 13.482 0.139 ;
     RECT  8.712 0.139 13.482 0.172 ;
     RECT  26.784 0.103 26.802 0.239 ;
     RECT  8.712 0.172 13.518 0.329 ;
     RECT  27.9 0.139 27.918 0.811 ;
     RECT  21.24 0.841 21.258 0.859 ;
     RECT  8.712 0.329 13.194 1.147 ;
     RECT  21.24 0.859 21.69 1.387 ;
     RECT  21.24 1.387 22.41 1.417 ;
     RECT  17.28 0.175 17.298 1.435 ;
     RECT  8.64 1.147 13.194 1.957 ;
     RECT  7.416 1.876 7.434 2.101 ;
     RECT  30.456 0.067 30.978 2.101 ;
     RECT  7.416 2.101 7.794 2.143 ;
     RECT  8.604 1.957 13.194 2.143 ;
     RECT  14.004 2.101 14.022 2.143 ;
     RECT  23.4 0.235 23.418 2.143 ;
     RECT  6.192 0.031 6.21 2.191 ;
     RECT  21.24 1.417 22.482 2.191 ;
     RECT  23.4 2.143 24.105 2.191 ;
     RECT  25.668 0.187 25.686 2.191 ;
     RECT  30.456 2.101 31.266 2.191 ;
     RECT  16.74 1.435 17.298 2.227 ;
     RECT  25.668 2.191 26.298 2.227 ;
     RECT  30.456 2.191 31.482 2.227 ;
     RECT  32.436 2.191 32.454 2.227 ;
     RECT  36.612 2.191 36.63 2.227 ;
     RECT  15.156 1.147 15.174 2.251 ;
     RECT  5.436 2.191 5.454 2.263 ;
     RECT  6.192 2.191 6.282 2.263 ;
     RECT  36.612 2.227 36.918 2.263 ;
     RECT  5.436 2.263 6.282 2.299 ;
     RECT  7.416 2.143 14.022 2.299 ;
     RECT  14.94 2.251 15.174 2.299 ;
     RECT  20.16 2.263 20.178 2.299 ;
     RECT  25.416 2.227 26.298 2.299 ;
     RECT  30.456 2.227 33.138 2.299 ;
     RECT  34.815 2.143 34.905 2.299 ;
     RECT  36.252 2.263 36.918 2.299 ;
     RECT  7.416 2.299 15.174 2.335 ;
     RECT  16.344 2.227 17.298 2.335 ;
     RECT  18.615 2.143 18.705 2.335 ;
     RECT  20.16 2.299 20.322 2.335 ;
     RECT  21.24 2.191 24.105 2.335 ;
     RECT  5.436 2.299 6.354 2.371 ;
     RECT  7.416 2.335 15.354 2.371 ;
     RECT  25.416 2.299 26.802 2.371 ;
     RECT  29.415 2.143 29.505 2.371 ;
     RECT  30.312 2.299 33.282 2.371 ;
     RECT  34.38 2.299 34.905 2.371 ;
     RECT  35.64 2.299 37.566 2.371 ;
     RECT  38.52 2.299 38.538 2.371 ;
     RECT  2.415 2.143 2.505 2.413 ;
     RECT  20.16 2.335 24.105 2.413 ;
     RECT  24.84 2.371 26.802 2.413 ;
     RECT  28.908 2.371 29.505 2.413 ;
     RECT  30.276 2.371 39.006 2.413 ;
     RECT  40.215 2.143 40.305 2.413 ;
     RECT  2.415 2.413 2.697 2.461 ;
     RECT  18.615 2.335 19.278 2.461 ;
     RECT  20.16 2.413 26.802 2.461 ;
     RECT  2.415 2.461 4.122 2.533 ;
     RECT  5.436 2.371 15.354 2.533 ;
     RECT  16.344 2.335 17.406 2.533 ;
     RECT  18.615 2.461 26.802 2.569 ;
     RECT  27.72 0.811 27.918 2.569 ;
     RECT  2.415 2.533 4.662 2.605 ;
     RECT  5.436 2.533 17.406 2.605 ;
     RECT  28.908 2.413 39.006 2.635 ;
     RECT  2.415 2.605 17.586 2.641 ;
     RECT  18.615 2.569 27.918 2.641 ;
     RECT  2.088 2.641 27.918 2.731 ;
     RECT  28.908 2.635 39.258 2.731 ;
     RECT  40.215 2.413 40.497 2.731 ;
     RECT  2.088 2.731 40.497 3.145 ;
     RECT  2.088 3.145 40.59 3.335 ;
     RECT  18.252 3.335 40.59 3.415 ;
     RECT  18.252 3.415 40.842 3.569 ;
     RECT  2.088 3.335 17.298 4.189 ;
     RECT  18.252 3.569 40.497 4.189 ;
     RECT  2.088 4.189 17.37 4.261 ;
     RECT  18.18 4.189 40.497 4.261 ;
     RECT  2.088 4.261 40.497 4.531 ;
     RECT  2.088 4.531 40.59 5.099 ;
     RECT  2.088 5.099 40.497 6.079 ;
     RECT  1.512 6.079 40.497 6.583 ;
     RECT  1.512 6.583 40.554 6.619 ;
     RECT  1.512 6.619 40.59 6.817 ;
     RECT  1.512 6.817 40.734 6.845 ;
     RECT  10.512 6.845 40.734 7.195 ;
     RECT  1.512 6.845 9.558 7.861 ;
     RECT  1.512 7.861 9.774 8.203 ;
     RECT  10.512 7.195 40.806 8.203 ;
     RECT  1.512 8.203 40.806 8.429 ;
     RECT  1.512 8.429 40.497 9.895 ;
     RECT  1.512 9.895 40.59 10.201 ;
     RECT  1.512 10.201 40.914 10.427 ;
     RECT  1.512 10.427 40.734 10.877 ;
     RECT  19.944 10.877 40.734 11.129 ;
     RECT  1.512 10.877 19.098 11.641 ;
     RECT  19.944 11.129 40.554 11.641 ;
     RECT  1.512 11.641 40.554 13.091 ;
     RECT  1.512 13.091 19.278 13.819 ;
     RECT  20.016 13.091 40.554 13.819 ;
     RECT  1.512 13.819 40.554 15.871 ;
     RECT  1.512 15.871 40.734 15.989 ;
     RECT  1.512 15.989 40.554 18.967 ;
     RECT  1.512 18.967 40.59 19.201 ;
     RECT  1.512 19.201 40.842 19.651 ;
     RECT  1.512 19.651 40.914 20.651 ;
     RECT  1.512 20.651 40.842 22.351 ;
     RECT  1.512 22.351 40.914 23.081 ;
     RECT  1.512 23.081 40.878 23.621 ;
     RECT  1.512 23.621 40.842 24.709 ;
     RECT  1.512 24.709 40.914 25.889 ;
     RECT  1.512 25.889 40.842 28.795 ;
     RECT  1.512 28.795 40.95 30.407 ;
     RECT  1.512 30.407 40.842 32.197 ;
     RECT  1.512 32.197 40.878 32.459 ;
     RECT  1.512 32.459 40.842 36.041 ;
     RECT  1.548 36.041 40.842 38.939 ;
     RECT  1.548 38.939 40.626 41.251 ;
     RECT  1.548 41.251 40.914 41.513 ;
     RECT  1.548 41.513 40.497 42.331 ;
     RECT  1.548 42.331 40.59 43.133 ;
     RECT  1.548 43.133 40.497 43.915 ;
     RECT  1.548 43.915 40.77 44.069 ;
     RECT  1.548 44.069 40.662 44.789 ;
     RECT  1.548 44.789 40.497 47.191 ;
     RECT  1.548 47.191 40.554 47.381 ;
     RECT  1.548 47.381 40.497 50.251 ;
     RECT  1.548 50.251 40.662 50.431 ;
     RECT  1.548 50.431 40.698 50.549 ;
     RECT  1.548 50.549 40.59 51.511 ;
     RECT  1.548 51.511 40.662 51.871 ;
     RECT  1.548 51.871 40.77 52.007 ;
     RECT  1.548 52.007 40.662 52.277 ;
     RECT  1.548 52.277 40.497 53.563 ;
     RECT  1.548 53.563 40.554 53.789 ;
     RECT  1.548 53.789 40.518 54.619 ;
     RECT  1.548 54.619 40.554 54.715 ;
     RECT  1.548 54.715 40.626 56.759 ;
     RECT  1.584 56.759 40.626 57.541 ;
     RECT  1.584 57.541 40.662 57.649 ;
     RECT  1.584 57.649 40.734 57.839 ;
     RECT  1.584 57.839 40.662 58.451 ;
     RECT  1.584 58.451 40.626 59.305 ;
     RECT  1.584 59.305 40.842 59.459 ;
     RECT  1.584 59.459 40.806 59.729 ;
     RECT  1.584 59.729 40.626 61.735 ;
     RECT  1.584 61.735 40.662 62.041 ;
     RECT  1.584 62.041 40.914 62.267 ;
     RECT  1.584 62.267 40.878 62.429 ;
     RECT  1.584 62.429 40.77 62.699 ;
     RECT  1.62 62.699 40.77 62.969 ;
     RECT  1.62 62.969 40.698 63.005 ;
     RECT  1.62 63.005 40.554 67.171 ;
     RECT  1.62 67.171 40.914 67.289 ;
     RECT  1.656 67.289 40.914 67.829 ;
     RECT  1.656 67.829 40.734 68.917 ;
     RECT  1.656 68.917 40.842 69.179 ;
     RECT  1.656 69.179 40.698 70.375 ;
     RECT  1.656 70.375 40.914 71.249 ;
     RECT  1.656 71.249 40.842 71.339 ;
     RECT  1.656 71.339 40.698 71.375 ;
     RECT  1.656 71.375 40.626 73.777 ;
     RECT  1.656 73.777 40.734 74.039 ;
     RECT  1.656 74.039 40.59 74.309 ;
     RECT  1.656 74.309 40.518 75.029 ;
     RECT  1.656 75.029 40.497 76.855 ;
     RECT  1.656 76.855 40.734 77.009 ;
     RECT  1.656 77.009 40.59 77.279 ;
     RECT  1.656 77.279 40.497 78.637 ;
     RECT  1.656 78.637 40.698 82.255 ;
     RECT  1.656 82.255 40.77 82.409 ;
     RECT  1.656 82.409 40.698 86.729 ;
     RECT  15.048 86.729 40.698 87.035 ;
     RECT  1.656 86.729 14.166 87.539 ;
     RECT  15.516 87.035 40.698 87.781 ;
     RECT  15.444 87.781 40.698 87.809 ;
     RECT  15.444 87.809 40.662 87.889 ;
     RECT  15.3 87.889 40.662 87.925 ;
     RECT  15.084 87.925 40.662 88.051 ;
     RECT  1.692 87.539 14.166 88.159 ;
     RECT  14.94 88.051 40.662 88.159 ;
     RECT  1.692 88.159 40.662 88.799 ;
     RECT  14.292 88.799 40.662 88.933 ;
     RECT  1.692 88.799 13.554 89.581 ;
     RECT  14.292 88.933 40.734 89.581 ;
     RECT  1.692 89.581 40.734 89.779 ;
     RECT  1.692 89.779 40.77 89.879 ;
     RECT  1.692 89.879 40.734 91.355 ;
     RECT  10.044 91.355 40.734 91.741 ;
     RECT  7.704 91.355 9.27 92.101 ;
     RECT  10.044 91.741 40.842 92.101 ;
     RECT  7.704 92.101 40.842 92.245 ;
     RECT  1.692 91.355 6.858 92.347 ;
     RECT  7.704 92.245 40.914 92.347 ;
     RECT  1.692 92.347 40.914 94.901 ;
     RECT  1.692 94.901 40.626 95.791 ;
     RECT  1.692 95.791 40.662 96.017 ;
     RECT  1.836 96.017 40.662 96.719 ;
     RECT  1.836 96.719 40.59 97.681 ;
     RECT  1.836 97.681 40.914 97.907 ;
     RECT  1.836 97.907 40.734 98.069 ;
     RECT  1.944 98.069 40.734 98.105 ;
     RECT  1.944 98.105 40.59 99.121 ;
     RECT  1.944 99.121 40.662 102.119 ;
     RECT  1.944 102.119 40.554 102.497 ;
     RECT  1.944 102.497 40.497 102.701 ;
     RECT  14.22 102.701 40.497 102.965 ;
     RECT  1.944 102.701 13.497 103.711 ;
     RECT  1.944 103.711 13.59 103.855 ;
     RECT  14.508 102.965 40.497 104.017 ;
     RECT  14.364 104.017 40.497 104.089 ;
     RECT  1.944 103.855 13.626 104.287 ;
     RECT  14.364 104.089 40.626 104.287 ;
     RECT  1.944 104.287 40.626 104.971 ;
     RECT  1.944 104.971 40.734 105.161 ;
     RECT  1.944 105.161 40.497 106.277 ;
     RECT  2.304 106.277 40.497 106.349 ;
     RECT  2.304 106.349 6.318 106.733 ;
     RECT  2.376 106.733 6.318 106.979 ;
     RECT  2.415 106.979 6.318 107.131 ;
     RECT  7.056 106.349 40.497 107.131 ;
     RECT  2.415 107.131 40.497 107.825 ;
     RECT  2.415 107.825 39.222 107.897 ;
     RECT  2.415 107.897 39.186 107.905 ;
     RECT  2.34 107.905 39.186 108.509 ;
     RECT  2.34 108.509 15.282 108.599 ;
     RECT  2.376 108.599 15.282 108.893 ;
     RECT  16.056 108.509 39.186 109.021 ;
     RECT  16.056 109.021 39.258 109.255 ;
     RECT  16.056 109.255 39.366 109.409 ;
     RECT  2.415 108.893 15.282 109.525 ;
     RECT  16.056 109.409 39.258 109.525 ;
     RECT  2.415 109.525 39.258 109.679 ;
     RECT  2.415 109.679 38.646 109.949 ;
     RECT  2.415 109.949 38.574 109.957 ;
     RECT  2.376 109.957 38.574 110.065 ;
     RECT  2.34 110.065 38.574 110.525 ;
     RECT  2.376 110.525 38.574 110.867 ;
     RECT  2.376 110.867 38.502 111.065 ;
     RECT  18.576 111.065 38.502 111.341 ;
     RECT  2.376 111.065 17.766 111.479 ;
     RECT  2.415 111.479 17.766 111.983 ;
     RECT  18.615 111.341 38.502 112.145 ;
     RECT  18.615 112.145 37.53 112.253 ;
     RECT  2.415 111.983 17.694 112.379 ;
     RECT  19.908 112.253 37.53 112.685 ;
     RECT  2.415 112.379 17.658 112.757 ;
     RECT  19.908 112.685 37.134 112.757 ;
     RECT  38.484 112.145 38.502 113.099 ;
     RECT  19.908 112.757 36.738 113.189 ;
     RECT  21.528 113.189 36.738 113.225 ;
     RECT  2.415 112.757 17.442 113.305 ;
     RECT  25.236 113.225 36.738 113.333 ;
     RECT  25.236 113.333 34.074 113.369 ;
     RECT  19.908 113.189 20.538 113.419 ;
     RECT  19.692 113.419 20.538 113.453 ;
     RECT  2.376 113.305 17.442 113.459 ;
     RECT  19.692 113.453 20.43 113.459 ;
     RECT  25.344 113.369 34.074 113.459 ;
     RECT  2.376 113.459 16.578 113.495 ;
     RECT  19.692 113.459 19.71 113.495 ;
     RECT  34.815 113.333 36.738 113.495 ;
     RECT  25.524 113.459 34.074 113.531 ;
     RECT  34.815 113.495 36.234 113.531 ;
     RECT  25.956 113.531 34.074 113.729 ;
     RECT  34.815 113.531 36.162 113.729 ;
     RECT  21.528 113.225 24.297 113.765 ;
     RECT  17.496 113.611 17.514 113.801 ;
     RECT  2.376 113.495 16.398 113.873 ;
     RECT  26.136 113.729 30.402 113.873 ;
     RECT  31.896 113.729 34.074 113.873 ;
     RECT  26.784 113.873 30.402 113.885 ;
     RECT  2.376 113.873 16.002 113.999 ;
     RECT  22.104 113.765 24.297 113.999 ;
     RECT  26.784 113.885 30.294 113.999 ;
     RECT  34.815 113.729 36.018 113.999 ;
     RECT  3.492 113.999 16.002 114.035 ;
     RECT  23.652 113.999 24.297 114.035 ;
     RECT  31.932 113.873 34.074 114.035 ;
     RECT  35.928 113.999 36.018 114.035 ;
     RECT  15.984 114.035 16.002 114.071 ;
     RECT  26.784 113.999 30.078 114.071 ;
     RECT  36 114.035 36.018 114.071 ;
     RECT  3.492 114.035 15.174 114.107 ;
     RECT  3.492 114.107 14.994 114.143 ;
     RECT  28.836 114.071 30.078 114.143 ;
     RECT  2.376 113.999 2.697 114.227 ;
     RECT  18.615 112.253 18.897 114.227 ;
     RECT  24.015 114.035 24.297 114.227 ;
     RECT  34.815 113.999 35.097 114.227 ;
     RECT  40.215 107.825 40.497 114.227 ;
     RECT  3.492 114.143 5.454 114.269 ;
     RECT  6.192 114.143 14.994 114.269 ;
     RECT  22.104 113.999 22.842 114.269 ;
     RECT  26.784 114.071 27.918 114.269 ;
     RECT  29.304 114.143 30.078 114.269 ;
     RECT  31.932 114.035 34.038 114.269 ;
     RECT  2.376 114.227 2.505 114.305 ;
     RECT  6.192 114.269 14.634 114.305 ;
     RECT  29.304 114.269 29.505 114.305 ;
     RECT  33.948 114.269 33.966 114.305 ;
     RECT  3.492 114.269 5.274 114.341 ;
     RECT  6.984 114.305 13.734 114.341 ;
     RECT  6.192 114.305 6.246 114.365 ;
     RECT  3.492 114.341 5.13 114.377 ;
     RECT  22.212 114.269 22.23 114.413 ;
     RECT  4.536 114.377 5.13 114.449 ;
     RECT  7.272 114.341 13.734 114.449 ;
     RECT  14.616 114.305 14.634 114.449 ;
     RECT  2.415 114.305 2.505 114.497 ;
     RECT  7.815 114.449 7.905 114.497 ;
     RECT  13.215 114.449 13.734 114.497 ;
     RECT  18.615 114.227 18.705 114.497 ;
     RECT  24.015 114.227 24.105 114.497 ;
     RECT  29.415 114.305 29.505 114.497 ;
     RECT  34.815 114.227 34.905 114.497 ;
     RECT  40.215 114.227 40.305 114.497 ;
     RECT  3.492 114.377 3.51 114.539 ;
     RECT  4.536 114.449 4.554 114.539 ;
     RECT  6.192 114.365 6.21 114.539 ;
     RECT  13.716 114.497 13.734 114.539 ;
     RECT  8.712 114.449 12.114 114.605 ;
     RECT  8.892 114.605 12.114 115.181 ;
     RECT  9 115.181 12.114 115.805 ;
     RECT  9 115.805 11.934 115.853 ;
     RECT  9 115.853 11.466 116.508 ;
    LAYER M4 ;
     RECT  0.156 14.88 0.275 15.192 ;
     RECT  0.275 15.024 2.408 15.192 ;
     RECT  2.365 18.192 2.408 18.216 ;
     RECT  2.293 34.656 2.408 35.496 ;
     RECT  2.365 46.608 2.408 46.632 ;
     RECT  2.365 52.992 2.408 53.016 ;
     RECT  2.365 54.864 2.408 54.888 ;
     RECT  0.229 57.36 2.408 57.384 ;
     RECT  2.293 66.096 2.408 66.12 ;
     RECT  2.293 67.392 2.408 67.416 ;
     RECT  2.401 69.312 2.408 69.336 ;
     RECT  2.365 86.832 2.408 86.856 ;
     RECT  2.365 90 2.408 90.024 ;
     RECT  2.365 103.2 2.408 103.224 ;
     RECT  2.293 106.704 2.408 106.728 ;
     RECT  2.365 108.864 2.408 108.888 ;
     RECT  2.408 2.148 2.512 114.492 ;
     RECT  2.512 2.418 2.704 114.222 ;
     RECT  2.704 75.552 2.819 76.104 ;
     RECT  2.704 102.624 2.819 103.224 ;
     RECT  2.704 89.424 2.837 91.32 ;
     RECT  2.819 102.912 2.845 103.224 ;
     RECT  2.704 66.288 2.867 69.336 ;
     RECT  2.704 106.704 2.873 110.52 ;
     RECT  2.704 88.368 2.909 88.392 ;
     RECT  2.704 3.408 2.915 7.944 ;
     RECT  2.704 45.024 2.915 45.288 ;
     RECT  2.704 95.76 2.953 100.344 ;
     RECT  2.704 38.256 3.011 40.296 ;
     RECT  2.704 18.192 3.017 23.928 ;
     RECT  2.704 94.56 3.017 94.68 ;
     RECT  2.704 36.864 3.089 36.888 ;
     RECT  3.011 38.256 3.089 39.48 ;
     RECT  2.704 82.56 3.107 82.68 ;
     RECT  2.704 64.896 3.125 64.968 ;
     RECT  2.704 77.424 3.125 77.832 ;
     RECT  2.704 32.928 3.197 33.336 ;
     RECT  3.089 38.352 3.197 39.48 ;
     RECT  3.107 82.56 3.197 82.632 ;
     RECT  2.704 70.656 3.233 73.032 ;
     RECT  2.704 111.552 3.233 113.448 ;
     RECT  2.704 79.248 3.299 79.272 ;
     RECT  2.704 12.528 3.341 15.576 ;
     RECT  3.017 18.768 3.341 21.672 ;
     RECT  3.341 12.528 3.347 15.384 ;
     RECT  2.704 9.36 3.377 11.352 ;
     RECT  2.704 25.104 3.377 27.816 ;
     RECT  3.197 82.56 3.377 82.584 ;
     RECT  2.915 45.024 3.449 45.048 ;
     RECT  2.704 101.424 3.449 101.544 ;
     RECT  3.017 94.656 3.485 94.68 ;
     RECT  2.867 66.288 3.521 68.424 ;
     RECT  2.845 103.2 3.521 103.224 ;
     RECT  3.341 20.544 3.539 21.672 ;
     RECT  2.704 31.92 3.557 31.944 ;
     RECT  3.233 71.328 3.557 73.032 ;
     RECT  2.704 51.36 3.587 51.384 ;
     RECT  3.347 12.528 3.593 14.184 ;
     RECT  2.915 7.728 3.628 7.944 ;
     RECT  2.953 96.336 3.629 100.344 ;
     RECT  3.629 97.536 3.683 100.344 ;
     RECT  2.704 29.232 3.685 29.256 ;
     RECT  3.685 29.232 3.692 29.976 ;
     RECT  3.628 7.728 3.701 7.848 ;
     RECT  2.704 80.496 3.731 81.48 ;
     RECT  3.692 29.232 3.733 30.6 ;
     RECT  2.704 46.608 3.737 48.648 ;
     RECT  2.704 86.64 3.737 86.856 ;
     RECT  3.683 97.536 3.737 97.56 ;
     RECT  3.449 101.424 3.737 101.448 ;
     RECT  2.704 56.448 3.769 58.728 ;
     RECT  2.704 59.808 3.769 60.216 ;
     RECT  3.593 12.528 3.773 13.704 ;
     RECT  3.125 64.944 3.781 64.968 ;
     RECT  3.521 66.288 3.781 67.272 ;
     RECT  3.197 32.928 3.805 32.952 ;
     RECT  2.704 62.496 3.805 62.664 ;
     RECT  2.837 89.424 3.805 89.448 ;
     RECT  3.233 111.696 3.805 113.448 ;
     RECT  3.788 69.504 3.829 69.528 ;
     RECT  2.873 109.392 3.841 110.52 ;
     RECT  3.197 38.448 3.845 39.48 ;
     RECT  3.737 86.64 3.845 86.712 ;
     RECT  3.377 26.256 3.877 27.816 ;
     RECT  3.733 29.04 3.877 30.6 ;
     RECT  2.704 34.8 3.877 35.496 ;
     RECT  2.704 42.144 3.877 43.272 ;
     RECT  2.704 52.416 3.881 53.016 ;
     RECT  3.557 72.432 3.881 73.032 ;
     RECT  3.805 62.496 3.905 63 ;
     RECT  3.881 52.416 3.913 52.44 ;
     RECT  3.845 38.448 3.923 39.336 ;
     RECT  3.731 80.496 3.949 80.52 ;
     RECT  3.521 68.4 3.971 68.424 ;
     RECT  3.737 46.992 3.973 48.648 ;
     RECT  2.704 50.064 3.973 50.136 ;
     RECT  2.704 16.848 3.985 16.872 ;
     RECT  3.769 56.448 3.985 60.408 ;
     RECT  3.905 61.536 3.985 63 ;
     RECT  3.985 56.448 3.989 63 ;
     RECT  3.845 86.688 3.989 86.712 ;
     RECT  3.805 111.696 4.025 113.592 ;
     RECT  3.877 34.08 4.028 35.496 ;
     RECT  2.704 54.048 4.057 54.888 ;
     RECT  3.805 88.944 4.057 89.448 ;
     RECT  2.837 90.48 4.057 91.32 ;
     RECT  3.377 9.648 4.061 11.352 ;
     RECT  3.125 77.808 4.061 77.832 ;
     RECT  4.057 88.944 4.061 91.32 ;
     RECT  4.025 111.696 4.061 113.448 ;
     RECT  3.341 18.768 4.093 19.368 ;
     RECT  3.877 41.568 4.115 43.272 ;
     RECT  4.057 54.048 4.129 55.128 ;
     RECT  3.989 56.448 4.129 58.728 ;
     RECT  4.028 34.08 4.133 36.216 ;
     RECT  3.781 64.944 4.133 67.272 ;
     RECT  3.017 22.656 4.165 23.928 ;
     RECT  3.923 38.64 4.169 39.336 ;
     RECT  4.115 42.528 4.169 43.272 ;
     RECT  3.985 16.512 4.172 16.872 ;
     RECT  4.093 18.192 4.172 19.368 ;
     RECT  4.201 44.448 4.209 44.472 ;
     RECT  4.165 22.512 4.211 23.928 ;
     RECT  3.973 46.992 4.213 50.136 ;
     RECT  3.949 80.16 4.241 80.52 ;
     RECT  3.841 109.392 4.241 110.568 ;
     RECT  4.172 16.512 4.259 19.368 ;
     RECT  4.213 46.992 4.259 51 ;
     RECT  2.915 3.408 4.273 6.696 ;
     RECT  3.701 7.728 4.273 7.752 ;
     RECT  4.259 46.992 4.277 47.304 ;
     RECT  4.273 3.408 4.309 7.752 ;
     RECT  4.061 112.32 4.313 113.448 ;
     RECT  3.829 69.504 4.345 70.2 ;
     RECT  4.169 42.624 4.349 43.272 ;
     RECT  2.704 104.256 4.355 105.672 ;
     RECT  3.347 15.36 4.381 15.384 ;
     RECT  3.877 26.256 4.381 30.6 ;
     RECT  2.704 83.76 4.385 83.784 ;
     RECT  4.355 105.216 4.396 105.672 ;
     RECT  3.773 12.528 4.405 13.08 ;
     RECT  3.989 62.16 4.417 63 ;
     RECT  3.985 76.176 4.453 76.2 ;
     RECT  4.129 54.048 4.489 58.728 ;
     RECT  4.133 66.912 4.489 67.272 ;
     RECT  2.873 106.704 4.493 108.216 ;
     RECT  3.805 32.448 4.525 32.952 ;
     RECT  4.133 34.08 4.525 35.592 ;
     RECT  3.683 98.736 4.525 100.344 ;
     RECT  4.405 11.856 4.529 13.08 ;
     RECT  3.989 59.856 4.529 60.984 ;
     RECT  4.345 69.504 4.537 70.68 ;
     RECT  4.061 88.944 4.547 90.552 ;
     RECT  3.377 25.104 4.549 25.128 ;
     RECT  4.259 48.384 4.549 51 ;
     RECT  3.913 52.032 4.549 52.44 ;
     RECT  3.539 20.544 4.561 21.144 ;
     RECT  4.549 25.104 4.561 25.224 ;
     RECT  4.381 26.256 4.561 30.84 ;
     RECT  4.493 107.808 4.561 108.216 ;
     RECT  4.489 66.912 4.573 67.8 ;
     RECT  4.525 32.448 4.595 35.592 ;
     RECT  4.547 88.944 4.595 88.968 ;
     RECT  4.309 3.36 4.597 7.752 ;
     RECT  4.349 42.672 4.597 43.272 ;
     RECT  4.209 44.304 4.597 44.472 ;
     RECT  4.595 32.448 4.601 32.472 ;
     RECT  4.453 76.176 4.601 76.392 ;
     RECT  4.313 112.32 4.601 113.352 ;
     RECT  4.381 15.312 4.633 15.384 ;
     RECT  4.259 16.512 4.633 16.536 ;
     RECT  4.345 73.776 4.637 73.8 ;
     RECT  2.704 93.504 4.637 93.528 ;
     RECT  3.629 96.336 4.637 96.36 ;
     RECT  4.417 62.16 4.673 63.768 ;
     RECT  4.489 53.568 4.691 58.728 ;
     RECT  4.561 20.544 4.705 21.24 ;
     RECT  4.211 22.512 4.705 23.016 ;
     RECT  4.201 45.552 4.709 45.576 ;
     RECT  4.277 46.992 4.709 47.016 ;
     RECT  4.673 62.16 4.739 62.712 ;
     RECT  4.549 48.384 4.745 52.44 ;
     RECT  4.133 64.944 4.745 65.832 ;
     RECT  4.573 66.912 4.745 66.936 ;
     RECT  4.061 9.648 4.781 10.872 ;
     RECT  4.745 48.384 4.781 52.056 ;
     RECT  4.781 51.84 4.817 52.056 ;
     RECT  4.739 62.544 4.817 62.712 ;
     RECT  4.597 69.264 4.817 69.288 ;
     RECT  4.169 38.784 4.844 39.336 ;
     RECT  4.529 12.48 4.849 13.08 ;
     RECT  4.525 98.736 4.849 100.872 ;
     RECT  4.781 48.384 4.853 50.76 ;
     RECT  4.597 3.312 4.885 7.752 ;
     RECT  4.561 25.104 4.885 30.84 ;
     RECT  4.597 42.672 4.889 44.472 ;
     RECT  4.529 59.856 4.889 60.408 ;
     RECT  4.241 109.392 4.889 110.52 ;
     RECT  4.885 3.168 4.921 7.752 ;
     RECT  4.885 25.056 4.921 30.84 ;
     RECT  4.537 70.656 4.957 70.68 ;
     RECT  3.881 72.432 4.957 72.456 ;
     RECT  4.396 105.408 4.957 105.672 ;
     RECT  4.493 106.704 4.957 106.728 ;
     RECT  4.921 3.168 4.993 7.992 ;
     RECT  4.921 24.336 5.027 30.84 ;
     RECT  4.601 76.368 5.027 76.392 ;
     RECT  4.645 37.536 5.065 37.56 ;
     RECT  4.601 112.32 5.065 112.344 ;
     RECT  4.981 75.168 5.068 75.192 ;
     RECT  4.705 20.544 5.075 23.016 ;
     RECT  4.561 107.808 5.077 108.312 ;
     RECT  4.781 10.656 5.105 10.872 ;
     RECT  5.027 24.816 5.105 30.84 ;
     RECT  5.105 24.912 5.141 30.84 ;
     RECT  4.673 63.744 5.141 63.768 ;
     RECT  5.077 107.808 5.164 108.6 ;
     RECT  5.141 25.056 5.171 27.528 ;
     RECT  4.844 38.784 5.173 39.432 ;
     RECT  5.173 38.784 5.177 39.576 ;
     RECT  4.889 42.72 5.177 44.472 ;
     RECT  4.691 56.976 5.209 58.728 ;
     RECT  4.889 59.856 5.209 60.264 ;
     RECT  4.993 2.784 5.249 7.992 ;
     RECT  4.633 15.312 5.249 16.536 ;
     RECT  4.817 51.84 5.249 51.864 ;
     RECT  4.691 53.568 5.249 55.848 ;
     RECT  5.249 2.784 5.267 7.608 ;
     RECT  4.633 77.472 5.267 77.496 ;
     RECT  5.105 10.848 5.269 10.872 ;
     RECT  5.141 28.656 5.276 30.84 ;
     RECT  5.276 28.656 5.281 31.032 ;
     RECT  5.101 32.352 5.281 32.376 ;
     RECT  4.601 113.328 5.281 113.352 ;
     RECT  5.171 25.104 5.285 27.528 ;
     RECT  4.853 49.152 5.308 50.76 ;
     RECT  4.259 18.144 5.317 19.368 ;
     RECT  5.029 85.248 5.353 85.272 ;
     RECT  5.075 20.544 5.363 21.432 ;
     RECT  5.281 28.656 5.363 32.376 ;
     RECT  4.597 102.576 5.389 102.6 ;
     RECT  5.317 17.856 5.404 19.368 ;
     RECT  5.177 42.96 5.425 44.472 ;
     RECT  4.597 94.656 5.425 94.68 ;
     RECT  5.353 85.104 5.461 85.272 ;
     RECT  5.267 2.784 5.465 7.368 ;
     RECT  5.363 28.656 5.465 30.744 ;
     RECT  5.363 31.728 5.465 32.376 ;
     RECT  4.849 98.736 5.533 101.208 ;
     RECT  5.363 20.784 5.555 21.432 ;
     RECT  4.889 109.68 5.564 110.52 ;
     RECT  5.404 18.192 5.573 19.368 ;
     RECT  5.285 25.152 5.573 27.528 ;
     RECT  3.949 92.496 5.605 92.52 ;
     RECT  5.065 112.272 5.605 112.344 ;
     RECT  5.281 113.328 5.605 114.168 ;
     RECT  5.308 49.152 5.609 49.224 ;
     RECT  4.957 70.656 5.609 72.456 ;
     RECT  5.425 93.936 5.612 94.68 ;
     RECT  5.533 82.656 5.645 82.68 ;
     RECT  5.612 93.936 5.653 95.016 ;
     RECT  5.533 98.736 5.653 101.448 ;
     RECT  5.389 102.576 5.653 102.648 ;
     RECT  5.075 22.512 5.677 23.016 ;
     RECT  5.653 98.736 5.699 102.648 ;
     RECT  4.849 12.48 5.708 13.176 ;
     RECT  4.817 62.544 5.717 62.664 ;
     RECT  5.708 12.48 5.749 13.272 ;
     RECT  5.249 15.312 5.749 16.392 ;
     RECT  5.308 50.736 5.749 50.76 ;
     RECT  5.557 104.4 5.749 104.424 ;
     RECT  5.555 20.928 5.753 21.432 ;
     RECT  5.653 93.936 5.753 95.784 ;
     RECT  5.465 28.704 5.789 30.072 ;
     RECT  5.425 42.96 5.789 45.144 ;
     RECT  5.461 85.104 5.789 85.512 ;
     RECT  5.605 112.272 5.789 114.168 ;
     RECT  5.177 39.312 5.821 39.576 ;
     RECT  5.209 56.976 5.825 60.264 ;
     RECT  4.957 105.408 5.852 106.728 ;
     RECT  5.164 107.808 5.852 108.216 ;
     RECT  5.564 109.68 5.893 111.144 ;
     RECT  5.605 91.776 5.897 92.52 ;
     RECT  5.749 104.16 5.897 104.424 ;
     RECT  5.789 28.704 5.933 29.976 ;
     RECT  5.699 98.736 5.933 102.6 ;
     RECT  5.933 101.328 5.939 102.6 ;
     RECT  4.547 90.048 5.996 90.552 ;
     RECT  4.745 64.944 6.073 64.968 ;
     RECT  5.897 104.208 6.083 104.424 ;
     RECT  5.893 109.68 6.085 111.24 ;
     RECT  5.497 61.296 6.14 61.32 ;
     RECT  5.249 53.568 6.181 55.416 ;
     RECT  6.181 52.896 6.185 55.416 ;
     RECT  5.753 94.08 6.185 95.784 ;
     RECT  5.789 113.472 6.217 114.168 ;
     RECT  5.825 56.976 6.227 59.832 ;
     RECT  6.14 60.816 6.227 61.32 ;
     RECT  5.749 12.48 6.229 13.368 ;
     RECT  5.749 14.784 6.229 16.392 ;
     RECT  6.083 104.256 6.229 104.424 ;
     RECT  5.852 105.408 6.229 108.216 ;
     RECT  6.085 109.392 6.253 111.24 ;
     RECT  5.789 112.272 6.253 112.392 ;
     RECT  5.789 85.104 6.257 85.272 ;
     RECT  5.821 39.312 6.289 40.104 ;
     RECT  6.073 64.944 6.289 65.304 ;
     RECT  6.185 52.896 6.293 53.592 ;
     RECT  5.609 70.656 6.293 71.64 ;
     RECT  6.257 85.248 6.293 85.272 ;
     RECT  6.229 12.48 6.323 16.392 ;
     RECT  5.933 98.736 6.325 100.344 ;
     RECT  5.789 42.96 6.329 44.472 ;
     RECT  6.227 58.704 6.365 59.832 ;
     RECT  6.329 42.96 6.419 43.896 ;
     RECT  5.465 31.92 6.433 32.376 ;
     RECT  4.595 33.792 6.433 35.592 ;
     RECT  6.289 64.944 6.433 65.544 ;
     RECT  5.269 10.848 6.445 11.4 ;
     RECT  5.465 2.784 6.469 4.104 ;
     RECT  5.465 5.136 6.469 7.368 ;
     RECT  6.185 54.624 6.469 55.416 ;
     RECT  6.227 56.976 6.469 57.624 ;
     RECT  6.365 58.704 6.509 58.824 ;
     RECT  6.293 52.896 6.545 53.352 ;
     RECT  6.185 94.56 6.563 95.784 ;
     RECT  5.573 26.016 6.572 27.528 ;
     RECT  5.933 28.704 6.572 29.88 ;
     RECT  5.573 18.576 6.577 19.368 ;
     RECT  5.209 69.216 6.577 69.24 ;
     RECT  6.253 109.392 6.577 112.392 ;
     RECT  5.749 50.736 6.581 50.808 ;
     RECT  6.509 58.8 6.581 58.824 ;
     RECT  5.857 41.952 6.613 41.976 ;
     RECT  6.613 41.616 6.649 41.976 ;
     RECT  6.419 42.96 6.649 43.56 ;
     RECT  6.577 18.576 6.721 19.704 ;
     RECT  5.753 21.072 6.721 21.432 ;
     RECT  5.677 22.512 6.721 23.352 ;
     RECT  6.469 2.784 6.757 7.368 ;
     RECT  6.721 18.192 6.757 19.704 ;
     RECT  6.445 10.848 6.761 11.352 ;
     RECT  5.609 49.152 6.793 49.176 ;
     RECT  6.721 96.768 6.805 96.792 ;
     RECT  6.577 69.216 6.821 69.576 ;
     RECT  5.065 36.96 6.829 37.56 ;
     RECT  5.749 46.752 6.829 46.776 ;
     RECT  6.109 47.856 6.829 47.88 ;
     RECT  6.229 104.256 6.833 108.216 ;
     RECT  6.289 38.832 6.853 40.104 ;
     RECT  6.805 96.768 6.853 96.936 ;
     RECT  6.325 97.968 6.853 100.344 ;
     RECT  6.433 31.92 6.86 35.592 ;
     RECT  6.577 109.2 6.865 112.392 ;
     RECT  6.217 113.472 6.865 114.36 ;
     RECT  6.761 10.848 6.901 10.92 ;
     RECT  6.572 26.016 6.901 29.88 ;
     RECT  6.86 31.392 6.901 35.592 ;
     RECT  6.829 36.96 6.901 37.608 ;
     RECT  6.853 38.784 6.901 40.152 ;
     RECT  6.833 104.352 6.901 108.216 ;
     RECT  6.865 109.2 6.901 114.36 ;
     RECT  6.829 46.752 6.949 46.872 ;
     RECT  5.717 62.544 6.997 62.568 ;
     RECT  6.721 21.072 7.009 23.352 ;
     RECT  6.997 62.544 7.009 63.24 ;
     RECT  6.757 2.784 7.045 7.896 ;
     RECT  4.781 9.648 7.045 9.672 ;
     RECT  6.949 46.32 7.081 46.872 ;
     RECT  6.829 47.856 7.081 48.12 ;
     RECT  7.009 21.072 7.093 23.64 ;
     RECT  6.613 51.216 7.093 51.24 ;
     RECT  6.757 18 7.117 19.704 ;
     RECT  7.093 21.072 7.141 24.12 ;
     RECT  6.901 36.96 7.153 40.152 ;
     RECT  7.045 9.36 7.225 9.672 ;
     RECT  6.901 10.656 7.225 10.92 ;
     RECT  6.853 96.768 7.225 100.344 ;
     RECT  5.939 101.328 7.225 102.312 ;
     RECT  6.227 61.104 7.285 61.128 ;
     RECT  7.009 62.208 7.285 63.24 ;
     RECT  7.117 18 7.297 19.992 ;
     RECT  7.141 21.072 7.297 24.696 ;
     RECT  6.649 41.616 7.305 43.56 ;
     RECT  7.093 51.216 7.333 51.768 ;
     RECT  6.323 12.48 7.381 14.904 ;
     RECT  6.323 15.984 7.381 16.392 ;
     RECT  7.305 41.472 7.405 43.56 ;
     RECT  7.285 61.104 7.405 63.24 ;
     RECT  6.433 64.32 7.405 65.544 ;
     RECT  7.081 46.32 7.429 48.12 ;
     RECT  6.793 49.152 7.429 49.704 ;
     RECT  7.405 61.104 7.429 65.544 ;
     RECT  7.297 18 7.441 24.696 ;
     RECT  6.901 26.016 7.441 35.592 ;
     RECT  7.153 36.816 7.441 40.152 ;
     RECT  7.429 61.104 7.441 65.976 ;
     RECT  6.469 54.624 7.477 57.624 ;
     RECT  5.897 92.304 7.477 92.52 ;
     RECT  6.973 93.504 7.477 93.528 ;
     RECT  7.477 92.304 7.525 93.528 ;
     RECT  7.441 17.904 7.621 24.696 ;
     RECT  7.441 61.008 7.628 65.976 ;
     RECT  7.045 2.784 7.729 8.184 ;
     RECT  7.729 2.544 7.808 8.184 ;
     RECT  7.225 9.36 7.808 10.92 ;
     RECT  7.381 12.48 7.808 16.392 ;
     RECT  7.621 17.616 7.808 24.696 ;
     RECT  7.441 26.016 7.808 40.152 ;
     RECT  7.405 41.472 7.808 43.944 ;
     RECT  7.181 44.976 7.808 45 ;
     RECT  7.429 46.32 7.808 49.704 ;
     RECT  7.333 51.216 7.808 51.96 ;
     RECT  6.545 53.328 7.808 53.352 ;
     RECT  7.477 54.624 7.808 58.44 ;
     RECT  6.997 59.856 7.808 59.88 ;
     RECT  7.628 61.008 7.808 66.168 ;
     RECT  7.117 67.824 7.808 67.848 ;
     RECT  6.821 68.928 7.808 69.576 ;
     RECT  6.293 71.616 7.808 71.64 ;
     RECT  6.865 77.376 7.808 77.4 ;
     RECT  7.513 79.296 7.808 79.32 ;
     RECT  4.241 80.496 7.808 80.52 ;
     RECT  7.621 85.488 7.808 85.512 ;
     RECT  7.261 88.896 7.808 88.92 ;
     RECT  5.996 90.048 7.808 91.176 ;
     RECT  7.525 92.16 7.808 93.528 ;
     RECT  6.563 94.608 7.808 95.784 ;
     RECT  7.225 96.768 7.808 102.312 ;
     RECT  6.901 104.352 7.808 114.36 ;
     RECT  7.808 2.148 7.912 114.492 ;
     RECT  7.912 2.208 8.104 114.492 ;
     RECT  8.104 45.504 8.237 50.712 ;
     RECT  8.104 51.744 8.243 55.512 ;
     RECT  8.104 95.616 8.309 114.492 ;
     RECT  8.104 60.336 8.381 63 ;
     RECT  8.104 76.704 8.417 76.92 ;
     RECT  8.104 80.496 8.417 80.76 ;
     RECT  8.104 89.184 8.417 94.056 ;
     RECT  8.104 13.056 8.425 34.488 ;
     RECT  8.104 35.472 8.453 37.704 ;
     RECT  8.425 15.216 8.483 34.488 ;
     RECT  8.417 90.816 8.489 90.888 ;
     RECT  8.453 35.856 8.524 37.704 ;
     RECT  8.104 74.112 8.525 74.136 ;
     RECT  8.104 75.168 8.525 75.192 ;
     RECT  8.425 13.056 8.572 14.136 ;
     RECT  8.243 51.744 8.597 54.648 ;
     RECT  8.483 15.216 8.633 21.528 ;
     RECT  8.104 68.928 8.633 69.24 ;
     RECT  8.381 60.336 8.675 62.328 ;
     RECT  8.309 96.816 8.701 114.492 ;
     RECT  8.524 36.288 8.741 37.704 ;
     RECT  8.417 92.016 8.777 94.056 ;
     RECT  8.104 64.176 8.813 65.16 ;
     RECT  8.237 46.512 8.86 50.712 ;
     RECT  8.701 96.816 8.881 114.6 ;
     RECT  8.86 50.688 8.915 50.712 ;
     RECT  8.104 84.288 8.921 84.312 ;
     RECT  8.417 89.184 8.921 89.688 ;
     RECT  8.741 36.288 8.957 37.464 ;
     RECT  8.104 2.208 8.963 9.384 ;
     RECT  8.483 22.512 9.011 34.488 ;
     RECT  8.813 64.176 9.029 65.016 ;
     RECT  8.963 2.208 9.059 6.12 ;
     RECT  8.417 76.752 9.101 76.92 ;
     RECT  9.011 22.512 9.107 32.472 ;
     RECT  8.572 13.056 9.133 13.656 ;
     RECT  8.104 71.616 9.133 71.64 ;
     RECT  8.881 96.816 9.133 115.176 ;
     RECT  8.777 92.016 9.137 93.816 ;
     RECT  9.133 96.816 9.155 115.752 ;
     RECT  9.155 96.864 9.157 115.752 ;
     RECT  8.104 40.8 9.169 44.376 ;
     RECT  8.237 45.504 9.169 45.528 ;
     RECT  9.133 13.008 9.173 13.656 ;
     RECT  8.104 10.752 9.203 10.776 ;
     RECT  9.125 0.192 9.205 0.216 ;
     RECT  8.963 7.632 9.205 9.384 ;
     RECT  9.173 13.008 9.205 13.08 ;
     RECT  9.169 40.8 9.205 45.528 ;
     RECT  9.157 96.864 9.209 115.896 ;
     RECT  9.133 70.896 9.245 71.64 ;
     RECT  8.675 60.336 9.251 61.656 ;
     RECT  9.029 64.992 9.281 65.016 ;
     RECT  9.137 92.16 9.281 93.816 ;
     RECT  9.205 40.416 9.292 45.528 ;
     RECT  8.633 15.216 9.317 21.432 ;
     RECT  9.101 76.752 9.317 76.776 ;
     RECT  8.104 85.344 9.353 86.088 ;
     RECT  8.597 51.744 9.389 54.312 ;
     RECT  9.251 61.2 9.389 61.656 ;
     RECT  8.921 89.184 9.389 89.208 ;
     RECT  9.317 15.216 9.395 17.592 ;
     RECT  8.104 56.88 9.397 58.44 ;
     RECT  9.395 15.216 9.443 17.4 ;
     RECT  9.209 115.152 9.445 115.896 ;
     RECT  9.353 85.344 9.461 85.512 ;
     RECT  8.633 69.216 9.491 69.24 ;
     RECT  9.059 2.736 9.497 6.12 ;
     RECT  9.389 53.76 9.497 54.312 ;
     RECT  9.209 96.864 9.497 114.12 ;
     RECT  9.397 56.88 9.529 58.92 ;
     RECT  9.385 60.192 9.529 60.216 ;
     RECT  9.389 51.744 9.587 52.392 ;
     RECT  9.317 18.816 9.601 21.432 ;
     RECT  9.107 22.512 9.601 24.12 ;
     RECT  9.205 12.192 9.637 13.08 ;
     RECT  8.309 95.616 9.637 95.64 ;
     RECT  8.104 38.784 9.673 39.336 ;
     RECT  9.443 15.216 9.677 17.16 ;
     RECT  9.497 2.736 9.683 5.688 ;
     RECT  9.292 40.8 9.685 45.528 ;
     RECT  8.86 46.512 9.685 49.416 ;
     RECT  9.529 56.88 9.713 60.216 ;
     RECT  8.957 36.432 9.745 37.464 ;
     RECT  9.673 78.672 9.785 78.696 ;
     RECT  8.489 90.816 9.785 90.84 ;
     RECT  9.713 56.88 9.817 57.384 ;
     RECT  9.637 10.8 9.821 13.08 ;
     RECT  9.461 85.344 9.821 85.368 ;
     RECT  9.685 40.8 9.827 49.416 ;
     RECT  9.011 33.6 9.836 34.488 ;
     RECT  9.713 58.368 9.857 60.216 ;
     RECT  9.421 74.688 9.889 74.712 ;
     RECT  9.827 40.8 9.901 47.736 ;
     RECT  9.901 40.8 9.971 45.528 ;
     RECT  8.417 80.496 9.973 80.52 ;
     RECT  9.637 95.568 9.997 95.64 ;
     RECT  9.683 2.736 10.001 3.432 ;
     RECT  9.889 74.544 10.001 74.712 ;
     RECT  9.281 92.304 10.045 93.816 ;
     RECT  9.245 71.616 10.069 71.64 ;
     RECT  10.045 92.304 10.073 92.328 ;
     RECT  9.997 95.568 10.105 95.688 ;
     RECT  10.105 14.112 10.189 14.136 ;
     RECT  9.745 36.432 10.213 37.512 ;
     RECT  10.001 74.544 10.217 74.664 ;
     RECT  9.445 115.152 10.289 115.944 ;
     RECT  10.001 3.312 10.307 3.432 ;
     RECT  9.497 103.728 10.309 114.12 ;
     RECT  10.289 115.152 10.309 115.848 ;
     RECT  9.107 25.2 10.321 32.472 ;
     RECT  9.836 33.6 10.321 35.064 ;
     RECT  10.213 36.384 10.321 37.512 ;
     RECT  10.069 71.616 10.393 71.88 ;
     RECT  8.104 87.696 10.397 87.72 ;
     RECT  10.321 25.2 10.429 35.064 ;
     RECT  10.429 25.2 10.451 35.304 ;
     RECT  9.205 7.632 10.499 9.72 ;
     RECT  10.499 9.696 10.501 9.72 ;
     RECT  9.821 10.8 10.501 13.032 ;
     RECT  10.501 9.696 10.505 13.032 ;
     RECT  10.451 25.2 10.537 33.864 ;
     RECT  10.309 103.728 10.541 115.848 ;
     RECT  10.451 34.896 10.573 35.304 ;
     RECT  10.321 36.384 10.573 37.704 ;
     RECT  10.499 7.632 10.577 8.712 ;
     RECT  9.497 54.096 10.597 54.312 ;
     RECT  10.105 95.568 10.604 95.736 ;
     RECT  9.497 96.864 10.609 102.6 ;
     RECT  10.541 115.152 10.643 115.848 ;
     RECT  10.045 93.408 10.645 93.816 ;
     RECT  10.604 95.376 10.645 95.736 ;
     RECT  10.609 96.864 10.645 102.744 ;
     RECT  10.307 3.408 10.649 3.432 ;
     RECT  10.505 9.696 10.649 10.104 ;
     RECT  9.673 38.784 10.649 39.624 ;
     RECT  9.857 58.416 10.681 60.216 ;
     RECT  9.389 61.2 10.681 61.512 ;
     RECT  10.597 53.52 10.684 54.312 ;
     RECT  10.393 70.656 10.685 71.88 ;
     RECT  9.637 83.808 10.685 83.832 ;
     RECT  9.601 18.816 10.717 24.12 ;
     RECT  10.717 18.576 10.748 24.12 ;
     RECT  10.537 25.104 10.748 33.864 ;
     RECT  10.645 94.944 10.753 102.744 ;
     RECT  10.541 103.728 10.753 114.12 ;
     RECT  10.465 14.208 10.789 14.232 ;
     RECT  9.677 15.504 10.789 17.16 ;
     RECT  10.748 18.576 10.789 33.864 ;
     RECT  9.817 56.448 10.789 57.384 ;
     RECT  10.649 38.832 10.825 39.624 ;
     RECT  9.901 46.512 10.825 47.736 ;
     RECT  9.827 48.768 10.825 49.416 ;
     RECT  10.141 63.216 10.825 63.24 ;
     RECT  10.685 71.04 10.825 71.88 ;
     RECT  10.789 14.208 10.829 33.864 ;
     RECT  10.829 14.208 10.835 18.6 ;
     RECT  10.829 19.584 10.835 33.864 ;
     RECT  10.684 54.096 10.837 54.312 ;
     RECT  10.789 55.68 10.837 57.384 ;
     RECT  10.753 94.944 10.873 114.12 ;
     RECT  10.873 94.944 10.883 96.6 ;
     RECT  9.587 52.128 10.901 52.392 ;
     RECT  10.681 90.864 10.901 90.888 ;
     RECT  10.681 58.416 10.909 61.512 ;
     RECT  10.825 46.512 10.933 49.56 ;
     RECT  10.069 79.056 10.933 79.08 ;
     RECT  10.837 54.096 10.937 57.384 ;
     RECT  10.825 62.688 10.937 63.24 ;
     RECT  10.505 11.184 10.973 13.032 ;
     RECT  9.683 4.56 11.009 5.688 ;
     RECT  10.973 12.528 11.009 13.032 ;
     RECT  10.835 14.784 11.009 18.6 ;
     RECT  10.937 63.216 11.029 63.24 ;
     RECT  10.177 64.944 11.029 64.968 ;
     RECT  11.029 63.216 11.075 64.968 ;
     RECT  11.075 63.216 11.081 64.2 ;
     RECT  11.081 64.176 11.116 64.2 ;
     RECT  10.835 19.632 11.117 33.864 ;
     RECT  10.933 46.512 11.123 49.608 ;
     RECT  10.937 55.536 11.125 57.384 ;
     RECT  10.909 58.416 11.125 59.208 ;
     RECT  10.825 38.832 11.149 40.392 ;
     RECT  9.971 41.376 11.149 45.528 ;
     RECT  10.973 11.184 11.153 11.448 ;
     RECT  11.125 55.536 11.153 59.208 ;
     RECT  10.717 50.784 11.221 50.808 ;
     RECT  10.901 52.128 11.221 52.152 ;
     RECT  9.205 0.192 11.225 0.552 ;
     RECT  10.645 93.408 11.257 93.96 ;
     RECT  11.009 12.768 11.293 13.032 ;
     RECT  11.113 83.184 11.293 83.208 ;
     RECT  11.257 93.072 11.293 93.96 ;
     RECT  10.883 94.944 11.293 96.36 ;
     RECT  10.577 7.632 11.297 7.656 ;
     RECT  10.789 76.368 11.297 76.392 ;
     RECT  10.933 78.768 11.297 79.272 ;
     RECT  8.104 66.384 11.329 66.408 ;
     RECT  11.117 19.632 11.377 32.52 ;
     RECT  11.149 38.832 11.393 45.528 ;
     RECT  11.225 0.288 11.401 0.552 ;
     RECT  11.293 82.464 11.405 83.208 ;
     RECT  11.009 14.88 11.411 18.6 ;
     RECT  11.153 56.544 11.411 59.208 ;
     RECT  11.293 93.072 11.411 96.36 ;
     RECT  11.329 66.192 11.413 66.408 ;
     RECT  11.117 33.504 11.437 33.864 ;
     RECT  10.573 34.896 11.437 37.704 ;
     RECT  11.009 4.56 11.441 4.584 ;
     RECT  11.413 66.192 11.468 66.792 ;
     RECT  11.365 69.504 11.509 69.528 ;
     RECT  11.411 96.336 11.513 96.36 ;
     RECT  11.468 66.192 11.555 67.464 ;
     RECT  10.643 115.728 11.555 115.848 ;
     RECT  11.509 69.456 11.596 69.528 ;
     RECT  11.516 92.016 11.603 92.04 ;
     RECT  10.825 71.04 11.617 71.976 ;
     RECT  11.113 72.96 11.617 72.984 ;
     RECT  10.577 8.688 11.621 8.712 ;
     RECT  11.617 71.04 11.657 72.984 ;
     RECT  11.596 69.504 11.689 69.528 ;
     RECT  11.297 79.248 11.689 79.272 ;
     RECT  9.973 80.496 11.689 81.24 ;
     RECT  10.873 97.728 11.699 114.12 ;
     RECT  10.937 54.096 11.729 54.312 ;
     RECT  11.657 71.856 11.756 72.984 ;
     RECT  11.756 71.856 11.765 73.944 ;
     RECT  11.123 46.656 11.797 49.608 ;
     RECT  11.221 50.784 11.797 52.152 ;
     RECT  11.377 19.632 11.801 32.472 ;
     RECT  11.411 56.688 11.801 59.208 ;
     RECT  11.545 86.832 11.833 86.856 ;
     RECT  11.617 89.28 11.833 89.304 ;
     RECT  10.105 1.728 11.837 1.752 ;
     RECT  11.729 54.096 11.843 54.12 ;
     RECT  11.765 71.952 11.843 72.072 ;
     RECT  11.765 73.92 11.843 73.944 ;
     RECT  11.689 79.248 11.843 81.24 ;
     RECT  11.393 38.832 11.845 45.624 ;
     RECT  11.833 86.64 11.869 86.856 ;
     RECT  11.699 97.728 11.893 103.272 ;
     RECT  10.909 61.488 11.905 61.512 ;
     RECT  11.797 46.656 11.945 52.152 ;
     RECT  10.909 60.192 11.945 60.456 ;
     RECT  11.555 115.776 11.945 115.848 ;
     RECT  11.437 33.504 11.977 37.704 ;
     RECT  11.845 38.688 11.977 45.624 ;
     RECT  11.411 93.072 11.981 95.16 ;
     RECT  11.893 97.488 11.981 103.272 ;
     RECT  11.843 80.784 12.013 81.24 ;
     RECT  11.153 11.184 12.016 11.208 ;
     RECT  11.981 93.744 12.017 95.16 ;
     RECT  11.401 0.288 12.037 0.6 ;
     RECT  11.801 19.632 12.049 32.28 ;
     RECT  10.649 9.936 12.085 9.96 ;
     RECT  12.016 11.136 12.085 11.208 ;
     RECT  11.977 33.504 12.085 45.624 ;
     RECT  11.945 46.656 12.085 50.712 ;
     RECT  11.905 61.44 12.085 61.512 ;
     RECT  11.945 115.776 12.125 115.8 ;
     RECT  12.013 80.784 12.131 81.528 ;
     RECT  11.555 66.768 12.133 67.464 ;
     RECT  11.545 5.856 12.157 5.88 ;
     RECT  12.049 7.104 12.157 7.128 ;
     RECT  12.085 9.936 12.181 11.208 ;
     RECT  11.945 51.744 12.193 52.152 ;
     RECT  12.017 95.136 12.197 95.16 ;
     RECT  12.133 66.768 12.22 68.376 ;
     RECT  11.801 57.072 12.229 59.208 ;
     RECT  12.085 84.72 12.233 84.744 ;
     RECT  12.181 9.024 12.265 11.208 ;
     RECT  12.157 5.856 12.301 7.128 ;
     RECT  12.193 51.744 12.373 52.536 ;
     RECT  11.843 79.248 12.409 79.272 ;
     RECT  11.405 83.184 12.409 83.208 ;
     RECT  11.833 89.136 12.409 89.304 ;
     RECT  12.301 5.856 12.445 7.752 ;
     RECT  11.411 14.88 12.445 18.168 ;
     RECT  11.293 12.768 12.469 13.368 ;
     RECT  12.445 14.496 12.469 18.168 ;
     RECT  12.085 61.44 12.517 62.184 ;
     RECT  12.22 66.768 12.517 67.8 ;
     RECT  12.409 83.184 12.517 83.592 ;
     RECT  12.277 96.72 12.545 96.744 ;
     RECT  12.373 51.744 12.553 53.016 ;
     RECT  11.869 85.92 12.565 86.856 ;
     RECT  12.565 85.104 12.668 86.856 ;
     RECT  12.469 12.768 12.689 18.168 ;
     RECT  12.049 19.392 12.689 32.28 ;
     RECT  12.409 88.56 12.697 89.304 ;
     RECT  12.517 82.704 12.709 83.592 ;
     RECT  12.697 88.32 12.757 89.304 ;
     RECT  12.445 4.944 12.769 7.752 ;
     RECT  12.265 9.024 12.769 11.496 ;
     RECT  12.553 51.744 12.805 53.064 ;
     RECT  11.153 55.536 12.805 55.56 ;
     RECT  12.229 57.072 12.805 59.88 ;
     RECT  11.689 69.504 12.805 70.824 ;
     RECT  12.805 54.72 12.841 55.56 ;
     RECT  12.805 56.88 12.841 59.88 ;
     RECT  12.037 0.288 12.901 1.464 ;
     RECT  12.901 0.24 13.013 1.464 ;
     RECT  12.193 2.496 13.013 2.52 ;
     RECT  12.769 4.944 13.093 11.496 ;
     RECT  12.689 12.768 13.093 32.28 ;
     RECT  12.085 33.504 13.093 50.712 ;
     RECT  12.805 51.744 13.093 53.592 ;
     RECT  13.093 33.504 13.129 53.592 ;
     RECT  13.013 0.24 13.189 2.52 ;
     RECT  13.189 0.192 13.208 2.52 ;
     RECT  13.093 4.128 13.208 32.28 ;
     RECT  13.129 33.36 13.208 53.592 ;
     RECT  12.841 54.72 13.208 59.88 ;
     RECT  12.517 61.44 13.208 62.76 ;
     RECT  12.445 64.608 13.208 64.776 ;
     RECT  12.517 65.808 13.208 67.8 ;
     RECT  12.805 69.408 13.208 70.824 ;
     RECT  11.843 71.952 13.208 71.976 ;
     RECT  13.165 77.568 13.208 77.592 ;
     RECT  12.409 78.816 13.208 79.272 ;
     RECT  12.131 80.784 13.208 80.808 ;
     RECT  12.709 81.888 13.208 83.592 ;
     RECT  12.668 85.104 13.208 87.336 ;
     RECT  12.757 88.32 13.208 89.496 ;
     RECT  11.617 90.624 13.208 90.648 ;
     RECT  12.017 93.744 13.208 94.056 ;
     RECT  12.545 96.336 13.208 96.744 ;
     RECT  11.981 98.064 13.208 103.272 ;
     RECT  11.699 104.256 13.208 114.12 ;
     RECT  13.208 0.192 13.312 114.492 ;
     RECT  13.312 0.192 13.453 114.222 ;
     RECT  13.453 0.144 13.504 114.222 ;
     RECT  13.504 100.608 13.565 100.824 ;
     RECT  13.504 90 13.619 90.024 ;
     RECT  13.504 2.496 13.637 17.016 ;
     RECT  13.637 2.496 13.681 14.328 ;
     RECT  13.681 2.496 13.745 14.232 ;
     RECT  13.504 105.936 13.745 109.464 ;
     RECT  13.504 96.624 13.853 97.08 ;
     RECT  13.745 107.856 13.889 109.464 ;
     RECT  13.504 18.144 13.9 64.632 ;
     RECT  13.745 2.496 13.907 4.152 ;
     RECT  13.504 110.496 13.925 113.064 ;
     RECT  13.9 18.144 13.955 23.4 ;
     RECT  13.504 75.792 14.003 77.592 ;
     RECT  14.003 75.792 14.033 77.544 ;
     RECT  13.9 24.48 14.105 64.632 ;
     RECT  14.033 75.792 14.147 76.968 ;
     RECT  13.745 5.232 14.177 14.232 ;
     RECT  13.504 101.856 14.213 102.696 ;
     RECT  14.105 62.976 14.285 64.632 ;
     RECT  13.745 105.936 14.321 106.824 ;
     RECT  13.853 97.056 14.357 97.08 ;
     RECT  14.105 24.48 14.429 61.512 ;
     RECT  13.504 98.976 14.492 99 ;
     RECT  13.565 100.608 14.492 100.632 ;
     RECT  13.504 69.792 14.497 74.616 ;
     RECT  13.504 66.288 14.533 68.568 ;
     RECT  14.497 69.792 14.533 75.192 ;
     RECT  14.213 101.856 14.533 101.88 ;
     RECT  13.889 107.856 14.537 108.888 ;
     RECT  14.492 98.976 14.579 100.632 ;
     RECT  13.504 81.888 14.609 83.112 ;
     RECT  14.609 82.128 14.641 83.112 ;
     RECT  14.533 84.288 14.641 84.312 ;
     RECT  14.177 5.232 14.675 14.136 ;
     RECT  14.641 82.128 14.681 84.312 ;
     RECT  13.925 111.696 14.706 113.064 ;
     RECT  14.533 66.288 14.713 75.192 ;
     RECT  13.504 92.304 14.713 92.328 ;
     RECT  13.504 93.744 14.713 93.816 ;
     RECT  13.955 18.144 14.717 23.016 ;
     RECT  13.637 15.36 14.725 17.016 ;
     RECT  14.717 18.144 14.725 22.92 ;
     RECT  14.537 107.856 14.725 107.976 ;
     RECT  14.706 111.744 14.785 113.064 ;
     RECT  14.285 62.976 14.789 64.104 ;
     RECT  14.785 111.744 14.789 113.64 ;
     RECT  14.713 66.096 14.825 75.192 ;
     RECT  14.713 92.304 14.825 93.816 ;
     RECT  13.907 3.552 14.857 4.152 ;
     RECT  14.675 5.232 14.857 11.832 ;
     RECT  14.857 3.552 14.867 11.832 ;
     RECT  14.533 101.76 14.897 101.88 ;
     RECT  14.429 24.48 14.905 51.432 ;
     RECT  13.504 0.144 14.929 1.464 ;
     RECT  13.907 2.496 14.929 2.52 ;
     RECT  14.929 0.144 14.969 2.52 ;
     RECT  14.681 83.232 15.005 84.312 ;
     RECT  14.789 111.84 15.041 111.864 ;
     RECT  14.867 3.6 15.077 11.832 ;
     RECT  14.897 101.76 15.107 101.784 ;
     RECT  14.725 107.76 15.107 107.976 ;
     RECT  14.789 62.976 15.109 63.864 ;
     RECT  14.825 92.304 15.109 92.328 ;
     RECT  14.579 99.84 15.148 100.632 ;
     RECT  14.147 76.368 15.177 76.968 ;
     RECT  14.905 41.184 15.185 51.432 ;
     RECT  14.825 66.096 15.196 75 ;
     RECT  14.789 112.848 15.293 113.64 ;
     RECT  13.925 110.496 15.329 110.52 ;
     RECT  15.061 98.784 15.349 98.808 ;
     RECT  15.177 76.896 15.361 76.968 ;
     RECT  14.893 96.624 15.361 96.648 ;
     RECT  15.077 3.6 15.365 11.208 ;
     RECT  15.196 66.096 15.397 74.088 ;
     RECT  15.293 112.848 15.401 112.872 ;
     RECT  15.365 3.6 15.509 11.016 ;
     RECT  15.107 107.952 15.509 107.976 ;
     RECT  15.361 80.112 15.577 80.136 ;
     RECT  15.361 96.624 15.577 97.416 ;
     RECT  15.148 100.32 15.577 100.632 ;
     RECT  14.725 15.36 15.613 22.92 ;
     RECT  15.577 79.968 15.649 80.952 ;
     RECT  15.349 98.592 15.649 98.808 ;
     RECT  14.321 105.936 15.649 106.584 ;
     RECT  15.649 79.824 15.685 80.952 ;
     RECT  14.681 82.128 15.685 82.152 ;
     RECT  14.675 12.816 15.689 14.136 ;
     RECT  15.505 78.624 15.721 78.648 ;
     RECT  15.685 79.824 15.721 82.152 ;
     RECT  15.721 78.624 15.757 82.152 ;
     RECT  15.005 83.232 15.757 83.256 ;
     RECT  15.577 96.144 15.761 97.416 ;
     RECT  15.649 105.888 15.761 106.584 ;
     RECT  15.613 15.264 15.781 22.92 ;
     RECT  14.905 24.48 15.781 39.912 ;
     RECT  15.109 92.16 15.833 92.328 ;
     RECT  15.689 12.816 15.865 13.752 ;
     RECT  15.185 42.576 15.865 51.432 ;
     RECT  14.429 52.464 15.865 61.512 ;
     RECT  15.833 92.304 15.884 92.328 ;
     RECT  14.825 93.744 15.884 93.816 ;
     RECT  15.109 62.64 15.901 63.864 ;
     RECT  15.397 65.472 15.901 74.088 ;
     RECT  15.781 15.264 15.941 39.912 ;
     RECT  15.941 15.264 16.013 19.56 ;
     RECT  15.761 97.392 16.013 97.416 ;
     RECT  15.941 21.168 16.028 39.912 ;
     RECT  15.185 41.184 16.028 41.4 ;
     RECT  16.013 15.264 16.049 19.368 ;
     RECT  15.884 92.304 16.081 93.816 ;
     RECT  16.028 21.168 16.115 41.4 ;
     RECT  16.081 92.304 16.157 94.728 ;
     RECT  14.533 104.256 16.161 104.28 ;
     RECT  16.157 92.304 16.193 92.328 ;
     RECT  16.157 93.792 16.193 94.728 ;
     RECT  15.865 42.576 16.225 61.512 ;
     RECT  15.901 62.64 16.225 64.056 ;
     RECT  16.161 103.728 16.225 104.28 ;
     RECT  15.649 98.592 16.229 99.192 ;
     RECT  15.761 105.936 16.229 106.584 ;
     RECT  16.225 103.344 16.259 104.28 ;
     RECT  16.259 103.344 16.268 103.752 ;
     RECT  15.577 100.32 16.309 101.016 ;
     RECT  16.268 102.576 16.355 103.752 ;
     RECT  14.969 0.144 16.373 2.28 ;
     RECT  16.261 111.792 16.373 111.816 ;
     RECT  15.757 78.624 16.405 83.256 ;
     RECT  15.005 84.288 16.405 84.312 ;
     RECT  16.229 98.592 16.405 98.616 ;
     RECT  16.309 100.32 16.441 101.352 ;
     RECT  16.405 78.624 16.451 84.312 ;
     RECT  15.901 65.136 16.477 74.088 ;
     RECT  16.477 65.136 16.501 74.424 ;
     RECT  16.225 75.792 16.501 75.816 ;
     RECT  16.441 100.272 16.547 101.352 ;
     RECT  15.509 3.648 16.549 11.016 ;
     RECT  15.865 12.288 16.549 13.752 ;
     RECT  16.405 107.76 16.553 107.784 ;
     RECT  16.547 100.992 16.588 101.352 ;
     RECT  16.405 98.016 16.589 98.616 ;
     RECT  15.761 96.144 16.621 96.168 ;
     RECT  15.361 76.896 16.657 77.544 ;
     RECT  16.451 78.624 16.657 82.728 ;
     RECT  16.621 95.904 16.661 96.168 ;
     RECT  16.373 0.144 16.769 1.464 ;
     RECT  16.588 101.328 16.769 101.352 ;
     RECT  16.501 65.136 16.796 75.816 ;
     RECT  16.657 76.896 16.796 82.728 ;
     RECT  16.115 21.168 16.835 39.912 ;
     RECT  16.549 3.648 16.981 13.752 ;
     RECT  13.504 86.64 17.017 86.664 ;
     RECT  15.925 90.24 17.017 90.264 ;
     RECT  16.796 65.136 17.077 82.728 ;
     RECT  16.835 21.168 17.089 23.112 ;
     RECT  16.835 24.336 17.093 39.912 ;
     RECT  16.049 15.264 17.161 17.112 ;
     RECT  16.049 18.24 17.161 19.368 ;
     RECT  16.225 42.576 17.161 64.056 ;
     RECT  17.077 65.04 17.161 82.728 ;
     RECT  16.981 2.64 17.165 13.752 ;
     RECT  17.161 15.264 17.165 19.368 ;
     RECT  16.115 40.992 17.269 41.4 ;
     RECT  17.017 86.64 17.269 86.76 ;
     RECT  17.161 42.576 17.305 82.728 ;
     RECT  17.165 2.64 17.309 8.28 ;
     RECT  17.093 39.216 17.345 39.912 ;
     RECT  17.305 42.528 17.345 82.728 ;
     RECT  17.269 40.992 17.365 41.496 ;
     RECT  17.345 42.528 17.365 75.528 ;
     RECT  17.365 40.992 17.411 75.528 ;
     RECT  17.411 41.136 17.417 75.528 ;
     RECT  16.229 106.56 17.485 106.584 ;
     RECT  17.089 21.12 17.521 23.112 ;
     RECT  16.193 93.792 17.521 94.68 ;
     RECT  16.661 95.904 17.521 95.928 ;
     RECT  17.345 76.56 17.593 82.728 ;
     RECT  16.451 83.76 17.593 84.312 ;
     RECT  17.309 2.64 17.597 5.88 ;
     RECT  17.269 86.64 17.605 87.192 ;
     RECT  17.165 15.264 17.633 18.744 ;
     RECT  17.305 85.488 17.653 85.512 ;
     RECT  17.605 86.544 17.653 87.192 ;
     RECT  17.089 105.168 17.797 105.192 ;
     RECT  17.521 93.792 17.809 95.928 ;
     RECT  17.165 9.312 17.845 13.752 ;
     RECT  16.589 98.592 17.845 98.616 ;
     RECT  17.804 100.656 17.845 100.68 ;
     RECT  17.845 98.592 17.941 100.68 ;
     RECT  17.809 93.408 18.017 95.928 ;
     RECT  17.017 89.952 18.044 91.896 ;
     RECT  18.017 92.88 18.044 95.928 ;
     RECT  17.941 97.92 18.061 100.68 ;
     RECT  16.355 102.912 18.14 103.752 ;
     RECT  17.797 105.072 18.14 105.192 ;
     RECT  17.845 9.312 18.169 14.088 ;
     RECT  17.633 15.264 18.169 16.92 ;
     RECT  18.14 102.912 18.169 105.192 ;
     RECT  17.485 106.56 18.169 106.68 ;
     RECT  18.061 108.048 18.181 108.072 ;
     RECT  17.089 88.896 18.277 88.92 ;
     RECT  18.044 89.952 18.277 95.928 ;
     RECT  17.093 24.336 18.325 37.992 ;
     RECT  18.325 24.096 18.349 37.992 ;
     RECT  17.345 39.216 18.349 39.864 ;
     RECT  17.633 17.904 18.373 18.744 ;
     RECT  17.521 21.072 18.373 23.112 ;
     RECT  18.349 24.096 18.373 39.864 ;
     RECT  17.417 54.336 18.421 75.528 ;
     RECT  17.593 76.56 18.421 84.312 ;
     RECT  18.373 17.904 18.469 19.608 ;
     RECT  18.373 21.072 18.469 39.864 ;
     RECT  18.421 110.592 18.469 110.616 ;
     RECT  18.181 108.048 18.565 108.936 ;
     RECT  18.469 110.592 18.565 112.248 ;
     RECT  16.769 0.144 18.608 1.416 ;
     RECT  17.597 2.784 18.608 5.88 ;
     RECT  17.309 6.864 18.608 8.28 ;
     RECT  18.169 9.312 18.608 16.92 ;
     RECT  18.469 17.904 18.608 39.864 ;
     RECT  17.417 41.136 18.608 53.352 ;
     RECT  18.421 54.336 18.608 84.312 ;
     RECT  17.653 85.488 18.608 87.192 ;
     RECT  18.277 88.896 18.608 95.928 ;
     RECT  18.061 97.44 18.608 100.68 ;
     RECT  18.421 101.856 18.608 101.88 ;
     RECT  18.169 102.912 18.608 106.68 ;
     RECT  18.565 108.048 18.608 112.248 ;
     RECT  16.549 113.424 18.608 113.448 ;
     RECT  18.608 0.144 18.712 114.492 ;
     RECT  18.712 2.418 18.904 114.222 ;
     RECT  18.904 111.312 18.965 112.248 ;
     RECT  18.904 100.608 19.043 101.88 ;
     RECT  18.904 54.384 19.235 77.064 ;
     RECT  18.904 40.992 19.283 53.4 ;
     RECT  18.904 14.928 19.289 39.864 ;
     RECT  18.904 92.112 19.289 95.688 ;
     RECT  18.904 108.192 19.289 110.04 ;
     RECT  18.904 5.28 19.433 7.176 ;
     RECT  18.904 88.896 19.433 89.784 ;
     RECT  18.965 111.696 19.505 112.248 ;
     RECT  18.904 98.496 19.571 99.192 ;
     RECT  18.904 2.784 19.577 4.248 ;
     RECT  19.577 2.784 19.613 4.152 ;
     RECT  18.904 96.72 19.619 96.744 ;
     RECT  19.613 2.832 19.685 4.152 ;
     RECT  19.433 89.376 19.721 89.784 ;
     RECT  19.283 44.208 19.763 53.4 ;
     RECT  19.283 40.992 19.829 43.128 ;
     RECT  18.904 8.16 19.865 13.848 ;
     RECT  18.904 113.424 19.897 113.448 ;
     RECT  19.235 54.384 19.907 69.48 ;
     RECT  19.433 5.376 19.933 7.176 ;
     RECT  19.865 8.16 19.933 13.416 ;
     RECT  19.043 100.896 19.957 101.88 ;
     RECT  18.904 102.96 19.957 106.584 ;
     RECT  19.571 99.024 20.005 99.192 ;
     RECT  18.904 78.432 20.051 87.24 ;
     RECT  19.235 70.464 20.081 77.064 ;
     RECT  19.289 14.928 20.153 39.816 ;
     RECT  19.907 63.216 20.293 69.48 ;
     RECT  20.081 70.464 20.293 72.264 ;
     RECT  20.051 78.432 20.293 87.192 ;
     RECT  19.721 89.76 20.293 89.784 ;
     RECT  18.904 91.056 20.293 91.08 ;
     RECT  20.293 63.216 20.333 72.264 ;
     RECT  20.081 73.296 20.365 77.064 ;
     RECT  20.293 78.096 20.365 87.192 ;
     RECT  19.957 100.896 20.389 106.584 ;
     RECT  20.293 89.76 20.405 91.08 ;
     RECT  19.289 108.816 20.435 110.04 ;
     RECT  19.763 46.752 20.437 53.4 ;
     RECT  19.907 54.384 20.437 62.232 ;
     RECT  20.389 100.896 20.473 107.16 ;
     RECT  20.153 19.584 20.509 39.816 ;
     RECT  20.005 99.024 20.549 99.768 ;
     RECT  19.289 92.448 20.581 95.688 ;
     RECT  20.405 91.056 20.653 91.08 ;
     RECT  20.653 91.056 20.684 91.224 ;
     RECT  20.581 92.448 20.684 96.456 ;
     RECT  19.933 5.376 20.725 13.416 ;
     RECT  20.435 108.96 20.725 110.04 ;
     RECT  19.505 111.696 20.725 111.72 ;
     RECT  20.725 5.328 20.761 13.416 ;
     RECT  20.473 100.896 20.765 107.736 ;
     RECT  20.684 91.056 20.771 96.456 ;
     RECT  19.685 2.832 20.773 3.96 ;
     RECT  20.761 5.136 20.773 13.416 ;
     RECT  19.829 41.136 20.797 43.128 ;
     RECT  19.763 44.208 20.797 45.624 ;
     RECT  20.509 19.584 20.819 39.912 ;
     RECT  20.797 41.136 20.869 45.624 ;
     RECT  20.437 46.752 20.869 62.232 ;
     RECT  20.771 92.448 20.869 96.456 ;
     RECT  20.773 2.832 20.905 13.416 ;
     RECT  20.869 41.136 20.915 62.232 ;
     RECT  20.905 2.832 20.941 13.656 ;
     RECT  20.153 14.928 20.941 17.928 ;
     RECT  20.725 108.96 20.941 111.72 ;
     RECT  19.897 112.704 20.941 113.448 ;
     RECT  20.549 99.024 20.977 99.144 ;
     RECT  20.941 108.96 20.981 113.448 ;
     RECT  20.915 46.512 21.013 62.232 ;
     RECT  20.333 63.216 21.013 68.664 ;
     RECT  20.333 69.984 21.049 72.264 ;
     RECT  20.365 73.296 21.049 87.192 ;
     RECT  20.941 2.832 21.053 17.928 ;
     RECT  20.981 112.368 21.061 113.448 ;
     RECT  21.053 2.832 21.125 7.8 ;
     RECT  20.819 19.584 21.161 39.816 ;
     RECT  21.061 112.368 21.203 113.736 ;
     RECT  20.869 92.448 21.301 97.32 ;
     RECT  21.013 46.512 21.337 68.664 ;
     RECT  20.765 100.896 21.341 107.544 ;
     RECT  21.341 100.896 21.373 102.984 ;
     RECT  21.053 8.784 21.413 17.928 ;
     RECT  21.337 46.512 21.445 68.952 ;
     RECT  21.049 69.984 21.445 87.192 ;
     RECT  20.405 89.76 21.445 89.784 ;
     RECT  21.445 46.512 21.449 87.192 ;
     RECT  21.445 89.76 21.481 89.832 ;
     RECT  20.915 41.136 21.521 45.48 ;
     RECT  21.161 19.584 21.553 28.296 ;
     RECT  21.521 41.136 21.557 45.336 ;
     RECT  21.203 113.712 21.557 113.736 ;
     RECT  21.553 19.2 21.625 28.296 ;
     RECT  21.625 19.104 21.661 28.296 ;
     RECT  21.413 15.264 21.733 17.928 ;
     RECT  21.661 19.008 21.733 28.296 ;
     RECT  21.481 89.76 21.733 90.024 ;
     RECT  20.771 91.056 21.733 91.224 ;
     RECT  21.341 104.256 21.733 107.544 ;
     RECT  21.373 100.848 21.769 102.984 ;
     RECT  21.733 89.76 21.797 91.224 ;
     RECT  21.733 15.264 21.809 28.296 ;
     RECT  21.449 66.432 21.829 87.192 ;
     RECT  21.797 88.896 21.829 91.224 ;
     RECT  21.301 92.448 21.829 97.416 ;
     RECT  21.733 104.256 21.829 107.592 ;
     RECT  20.981 108.96 21.829 111.384 ;
     RECT  21.829 66.432 21.881 87.912 ;
     RECT  21.829 88.896 21.881 97.416 ;
     RECT  21.161 29.856 21.921 39.816 ;
     RECT  21.881 89.76 21.925 97.416 ;
     RECT  21.125 2.88 22.021 7.8 ;
     RECT  21.413 8.784 22.021 14.088 ;
     RECT  21.921 29.856 22.124 39.912 ;
     RECT  21.557 41.136 22.124 45.192 ;
     RECT  20.977 98.736 22.165 99.144 ;
     RECT  21.769 100.752 22.165 102.984 ;
     RECT  22.124 29.856 22.211 45.192 ;
     RECT  18.712 0.144 22.261 1.416 ;
     RECT  22.021 2.88 22.261 14.088 ;
     RECT  21.829 104.256 22.345 111.384 ;
     RECT  21.203 112.368 22.345 112.728 ;
     RECT  22.261 0.144 22.348 14.088 ;
     RECT  21.449 46.512 22.381 65.4 ;
     RECT  22.211 29.856 22.417 39.384 ;
     RECT  22.348 0.144 22.421 1.416 ;
     RECT  22.345 104.256 22.457 113.256 ;
     RECT  22.381 46.32 22.489 65.4 ;
     RECT  21.881 66.432 22.489 85.512 ;
     RECT  22.165 98.736 22.489 102.984 ;
     RECT  21.925 89.76 22.525 97.56 ;
     RECT  22.489 98.736 22.525 103.08 ;
     RECT  22.525 89.76 22.601 103.08 ;
     RECT  22.457 104.4 22.643 113.256 ;
     RECT  22.601 92.448 22.693 103.08 ;
     RECT  21.881 86.496 22.741 87.912 ;
     RECT  22.211 41.136 22.777 45.192 ;
     RECT  22.489 46.32 22.781 85.512 ;
     RECT  21.809 15.456 22.813 28.296 ;
     RECT  22.417 29.808 22.813 39.384 ;
     RECT  22.601 89.76 22.877 91.464 ;
     RECT  22.348 2.784 22.885 14.088 ;
     RECT  22.813 15.456 22.885 39.384 ;
     RECT  22.777 41.136 22.933 45.288 ;
     RECT  22.781 46.32 22.933 69.864 ;
     RECT  22.781 70.848 22.957 85.512 ;
     RECT  22.741 86.496 22.957 88.488 ;
     RECT  22.933 41.136 23.245 69.864 ;
     RECT  22.885 2.784 23.317 39.384 ;
     RECT  23.245 40.656 23.317 69.864 ;
     RECT  22.643 104.4 23.605 105.384 ;
     RECT  22.643 106.56 23.605 113.256 ;
     RECT  22.957 70.848 23.641 88.488 ;
     RECT  22.877 89.52 23.641 91.464 ;
     RECT  23.317 2.784 24.008 69.864 ;
     RECT  23.641 70.848 24.008 91.464 ;
     RECT  22.693 92.448 24.008 103.224 ;
     RECT  23.605 104.4 24.008 113.256 ;
     RECT  24.008 2.148 24.112 114.492 ;
     RECT  24.112 2.418 24.304 114.222 ;
     RECT  24.304 22.128 24.401 83.256 ;
     RECT  24.401 22.128 24.508 83.208 ;
     RECT  24.508 29.568 24.689 83.208 ;
     RECT  24.304 106.32 24.844 113.256 ;
     RECT  24.689 29.856 24.899 83.208 ;
     RECT  24.304 2.88 24.941 20.856 ;
     RECT  24.941 2.88 25.049 3.912 ;
     RECT  24.941 4.992 25.049 20.856 ;
     RECT  24.899 29.856 25.085 69.816 ;
     RECT  24.899 70.848 25.157 83.208 ;
     RECT  24.304 88.944 25.265 105.336 ;
     RECT  25.265 100.08 25.285 105.336 ;
     RECT  24.844 106.32 25.285 109.512 ;
     RECT  24.304 84.288 25.297 87.912 ;
     RECT  25.265 88.944 25.297 99.096 ;
     RECT  25.049 2.88 25.405 3.672 ;
     RECT  25.085 51.84 25.445 69.816 ;
     RECT  24.508 22.128 25.621 28.296 ;
     RECT  25.085 29.856 25.657 50.856 ;
     RECT  25.405 2.256 25.667 3.672 ;
     RECT  25.297 84.288 25.697 99.096 ;
     RECT  24.844 110.784 25.697 113.256 ;
     RECT  25.697 89.376 25.715 99.096 ;
     RECT  25.285 100.08 25.733 109.512 ;
     RECT  25.049 4.992 25.769 20.328 ;
     RECT  25.621 22.128 25.793 28.488 ;
     RECT  25.667 2.784 25.841 3.672 ;
     RECT  25.697 110.784 25.873 112.2 ;
     RECT  25.793 21.648 25.877 28.488 ;
     RECT  25.445 51.984 25.909 69.816 ;
     RECT  25.157 70.848 25.909 82.776 ;
     RECT  25.769 4.992 26.021 8.568 ;
     RECT  25.769 9.552 26.089 20.328 ;
     RECT  25.877 22.128 26.129 28.488 ;
     RECT  26.021 4.992 26.161 8.52 ;
     RECT  25.697 113.184 26.269 113.256 ;
     RECT  26.089 9.552 26.387 20.952 ;
     RECT  26.387 11.664 26.428 20.952 ;
     RECT  26.161 4.704 26.497 8.52 ;
     RECT  25.657 29.808 26.629 50.856 ;
     RECT  25.909 51.984 26.629 82.776 ;
     RECT  26.629 29.808 26.665 82.776 ;
     RECT  25.873 110.544 26.677 112.2 ;
     RECT  26.269 113.184 26.677 113.736 ;
     RECT  25.733 100.08 26.725 103.32 ;
     RECT  25.733 104.304 26.725 109.512 ;
     RECT  26.665 29.472 26.777 82.776 ;
     RECT  26.777 29.472 26.779 62.904 ;
     RECT  26.677 110.544 26.784 113.736 ;
     RECT  25.841 2.88 26.809 3.672 ;
     RECT  26.497 4.704 26.809 8.328 ;
     RECT  25.697 84.288 26.809 87.912 ;
     RECT  25.715 89.424 26.809 99.096 ;
     RECT  26.129 22.368 26.813 28.488 ;
     RECT  26.813 22.368 26.849 25.416 ;
     RECT  26.428 19.2 26.921 20.952 ;
     RECT  26.779 29.472 26.993 62.856 ;
     RECT  26.809 84.288 27.013 99.096 ;
     RECT  26.725 100.08 27.013 109.512 ;
     RECT  26.993 29.472 27.052 37.992 ;
     RECT  27.013 83.808 27.137 109.512 ;
     RECT  26.993 39.168 27.203 62.856 ;
     RECT  26.921 19.2 27.251 20.328 ;
     RECT  27.203 39.312 27.281 62.856 ;
     RECT  26.777 63.888 27.301 82.776 ;
     RECT  27.137 83.808 27.301 105.528 ;
     RECT  27.137 106.8 27.395 109.512 ;
     RECT  27.251 19.2 27.461 20.088 ;
     RECT  26.849 22.512 27.461 25.416 ;
     RECT  27.052 29.472 27.533 37.176 ;
     RECT  27.301 63.888 27.539 105.528 ;
     RECT  27.395 107.136 27.565 109.512 ;
     RECT  26.784 110.544 27.565 113.208 ;
     RECT  26.428 11.664 27.589 17.928 ;
     RECT  27.461 19.2 27.589 19.368 ;
     RECT  26.387 9.552 27.673 10.488 ;
     RECT  27.589 11.664 27.673 19.368 ;
     RECT  27.539 80.256 27.677 105.528 ;
     RECT  27.565 107.136 27.683 113.208 ;
     RECT  26.813 26.544 27.712 28.488 ;
     RECT  27.533 29.472 27.712 31.944 ;
     RECT  27.533 33.072 27.713 37.176 ;
     RECT  22.421 0.144 27.749 0.84 ;
     RECT  27.677 80.256 27.821 82.056 ;
     RECT  27.461 24.336 27.853 25.416 ;
     RECT  27.281 59.184 27.961 62.856 ;
     RECT  27.539 63.888 27.961 79.08 ;
     RECT  27.677 83.664 28.115 105.528 ;
     RECT  27.713 33.264 28.177 37.176 ;
     RECT  27.461 22.512 28.213 23.304 ;
     RECT  27.683 107.28 28.249 113.208 ;
     RECT  28.213 22.224 28.285 23.304 ;
     RECT  26.809 2.88 28.361 8.328 ;
     RECT  28.177 33.264 28.393 38.28 ;
     RECT  28.115 97.536 28.397 105.528 ;
     RECT  28.357 20.736 28.453 20.76 ;
     RECT  27.853 24.336 28.465 25.464 ;
     RECT  28.393 33.264 28.501 38.328 ;
     RECT  27.281 39.312 28.501 58.008 ;
     RECT  27.961 59.184 28.501 79.08 ;
     RECT  27.821 80.256 28.501 81.768 ;
     RECT  28.249 107.28 28.508 113.352 ;
     RECT  28.501 33.264 28.609 58.008 ;
     RECT  27.712 26.544 28.789 31.944 ;
     RECT  28.609 33.264 28.789 58.104 ;
     RECT  28.508 107.28 28.825 114.024 ;
     RECT  28.397 102.912 28.861 105.528 ;
     RECT  28.825 107.136 28.861 114.024 ;
     RECT  28.285 22.032 28.933 23.304 ;
     RECT  28.465 24.336 28.933 25.512 ;
     RECT  28.789 26.544 28.933 58.104 ;
     RECT  28.115 83.664 28.933 96.36 ;
     RECT  28.933 22.032 29.077 58.104 ;
     RECT  28.501 59.184 29.077 81.768 ;
     RECT  27.673 9.552 29.125 19.368 ;
     RECT  28.453 20.64 29.125 20.76 ;
     RECT  28.361 7.44 29.185 8.328 ;
     RECT  29.185 7.44 29.221 8.568 ;
     RECT  29.125 9.552 29.221 20.76 ;
     RECT  28.361 2.88 29.249 6.456 ;
     RECT  28.861 102.912 29.269 114.024 ;
     RECT  28.933 83.52 29.293 96.36 ;
     RECT  28.397 97.536 29.293 101.64 ;
     RECT  29.249 2.832 29.408 6.456 ;
     RECT  29.221 7.44 29.408 20.76 ;
     RECT  29.077 22.032 29.408 81.768 ;
     RECT  29.293 83.52 29.408 101.64 ;
     RECT  29.269 102.912 29.408 114.264 ;
     RECT  29.408 2.148 29.512 114.492 ;
     RECT  29.512 2.418 29.704 114.222 ;
     RECT  29.704 22.032 29.765 29.352 ;
     RECT  29.704 30.384 29.765 53.64 ;
     RECT  29.704 108.912 29.765 113.88 ;
     RECT  29.765 22.032 29.837 28.488 ;
     RECT  29.837 22.032 29.843 22.872 ;
     RECT  29.704 103.008 29.843 107.688 ;
     RECT  29.704 91.2 29.873 102.024 ;
     RECT  29.704 54.672 29.981 74.088 ;
     RECT  29.873 91.2 29.981 93.768 ;
     RECT  29.765 30.384 29.987 53.544 ;
     RECT  29.987 31.776 30.017 53.544 ;
     RECT  29.987 30.384 30.089 30.744 ;
     RECT  29.873 94.848 30.089 102.024 ;
     RECT  29.765 110.544 30.413 113.88 ;
     RECT  30.089 97.632 30.508 102.024 ;
     RECT  29.704 75.12 30.697 75.24 ;
     RECT  29.704 76.368 30.697 87.624 ;
     RECT  30.697 75.12 30.737 87.624 ;
     RECT  29.843 103.008 30.764 105.528 ;
     RECT  29.704 20.4 30.769 20.952 ;
     RECT  29.704 2.784 30.805 19.368 ;
     RECT  30.737 75.12 30.809 82.968 ;
     RECT  29.843 22.848 30.841 22.872 ;
     RECT  29.837 23.856 30.841 28.488 ;
     RECT  30.805 2.256 30.889 19.368 ;
     RECT  30.841 22.848 30.913 28.488 ;
     RECT  29.981 69.744 30.913 74.088 ;
     RECT  30.809 75.12 30.913 75.912 ;
     RECT  30.089 30.384 31.093 30.648 ;
     RECT  30.017 31.776 31.093 53.352 ;
     RECT  29.704 88.704 31.093 89.88 ;
     RECT  29.981 91.2 31.093 93.672 ;
     RECT  29.765 108.912 31.093 109.512 ;
     RECT  30.413 110.544 31.093 113.256 ;
     RECT  31.093 30.384 31.141 53.352 ;
     RECT  29.981 54.672 31.141 68.76 ;
     RECT  30.913 22.848 31.165 29.064 ;
     RECT  29.843 106.56 31.165 107.688 ;
     RECT  31.093 108.912 31.165 113.256 ;
     RECT  30.737 84 31.189 87.624 ;
     RECT  31.093 88.704 31.189 93.672 ;
     RECT  31.165 22.656 31.201 29.064 ;
     RECT  30.769 20.4 31.241 21.672 ;
     RECT  31.141 30.384 31.241 68.76 ;
     RECT  31.165 106.56 31.249 113.256 ;
     RECT  31.241 21.648 31.333 21.672 ;
     RECT  31.201 22.656 31.333 29.208 ;
     RECT  31.189 84 31.385 93.672 ;
     RECT  31.241 54.672 31.417 68.76 ;
     RECT  30.913 69.744 31.417 75.912 ;
     RECT  30.764 102.816 31.417 105.528 ;
     RECT  31.249 106.56 31.417 107.736 ;
     RECT  30.089 94.848 31.525 96.456 ;
     RECT  30.508 97.632 31.525 101.64 ;
     RECT  30.889 2.736 31.532 19.368 ;
     RECT  31.241 20.4 31.532 20.664 ;
     RECT  31.532 2.736 31.565 20.664 ;
     RECT  31.385 88.368 31.597 93.672 ;
     RECT  31.525 94.848 31.597 101.64 ;
     RECT  31.333 21.648 31.633 29.208 ;
     RECT  31.241 30.384 31.633 53.112 ;
     RECT  31.597 88.368 31.661 101.64 ;
     RECT  31.417 102.816 31.661 107.736 ;
     RECT  31.633 21.648 31.673 53.112 ;
     RECT  31.661 88.368 31.715 107.736 ;
     RECT  31.565 2.736 31.885 8.472 ;
     RECT  31.417 54.672 31.885 75.912 ;
     RECT  30.809 76.992 31.885 82.968 ;
     RECT  31.249 108.816 31.885 113.256 ;
     RECT  31.565 9.84 31.955 20.664 ;
     RECT  31.955 13.008 31.961 20.664 ;
     RECT  31.961 13.008 32.051 16.92 ;
     RECT  31.673 30 32.069 53.112 ;
     RECT  32.069 30 32.141 31.224 ;
     RECT  31.885 54.672 32.245 82.968 ;
     RECT  31.385 84 32.245 87.192 ;
     RECT  31.673 21.648 32.249 28.68 ;
     RECT  32.069 32.304 32.281 53.112 ;
     RECT  27.749 0.144 32.291 0.168 ;
     RECT  32.051 16.08 32.321 16.92 ;
     RECT  31.961 17.904 32.533 20.664 ;
     RECT  32.281 32.304 32.537 53.592 ;
     RECT  32.245 54.672 32.753 87.192 ;
     RECT  31.715 88.368 32.771 107.688 ;
     RECT  32.537 48.144 32.773 53.592 ;
     RECT  32.753 54.672 32.773 82.2 ;
     RECT  32.773 48.144 32.789 82.2 ;
     RECT  32.537 32.304 32.861 37.656 ;
     RECT  32.789 48.192 32.861 82.2 ;
     RECT  32.771 106.56 32.861 107.688 ;
     RECT  31.885 108.816 32.861 113.448 ;
     RECT  31.885 2.592 32.869 8.472 ;
     RECT  31.955 9.84 32.869 11.976 ;
     RECT  32.861 33.792 32.933 37.656 ;
     RECT  32.861 54.672 32.933 82.2 ;
     RECT  32.869 2.592 33.001 11.976 ;
     RECT  32.051 13.008 33.001 14.52 ;
     RECT  32.141 30 33.004 30.888 ;
     RECT  32.753 83.184 33.013 87.192 ;
     RECT  33.013 83.184 33.068 87.24 ;
     RECT  32.771 88.368 33.068 105.528 ;
     RECT  32.861 48.192 33.085 53.64 ;
     RECT  33.068 83.184 33.155 105.528 ;
     RECT  32.861 106.704 33.217 107.688 ;
     RECT  33.217 106.704 33.221 107.928 ;
     RECT  32.861 109.488 33.221 113.448 ;
     RECT  33.221 109.488 33.257 113.256 ;
     RECT  32.249 22.656 33.325 28.68 ;
     RECT  33.001 2.592 33.365 14.52 ;
     RECT  33.155 88.368 33.443 105.528 ;
     RECT  32.933 57.312 33.539 82.2 ;
     RECT  33.443 94.416 33.581 105.528 ;
     RECT  32.861 32.304 33.613 32.472 ;
     RECT  33.581 94.656 33.617 105.528 ;
     RECT  32.533 17.904 33.621 21.48 ;
     RECT  33.613 32.064 33.635 32.472 ;
     RECT  33.365 2.832 33.685 14.52 ;
     RECT  33.617 94.848 33.689 105.528 ;
     RECT  33.004 30.384 33.721 30.888 ;
     RECT  33.539 63.888 33.733 82.2 ;
     RECT  33.155 83.184 33.733 87.336 ;
     RECT  33.733 63.888 33.761 87.336 ;
     RECT  32.537 38.784 33.788 47.16 ;
     RECT  33.085 48.192 33.788 53.592 ;
     RECT  33.221 107.232 33.829 107.928 ;
     RECT  33.257 109.488 33.829 110.088 ;
     RECT  33.685 2.832 33.973 14.952 ;
     RECT  32.321 16.08 33.973 16.536 ;
     RECT  33.621 17.568 33.973 21.48 ;
     RECT  33.973 2.832 34.189 21.48 ;
     RECT  33.325 22.656 34.189 29.256 ;
     RECT  33.788 38.784 34.189 53.592 ;
     RECT  32.933 54.96 34.189 56.28 ;
     RECT  33.689 103.008 34.189 105.528 ;
     RECT  33.829 107.232 34.189 110.088 ;
     RECT  32.933 33.84 34.357 37.656 ;
     RECT  33.257 111.264 34.369 113.256 ;
     RECT  34.189 38.784 34.405 56.28 ;
     RECT  33.539 57.312 34.405 62.856 ;
     RECT  34.405 38.784 34.513 62.856 ;
     RECT  33.761 63.888 34.513 75.144 ;
     RECT  34.189 2.832 34.657 29.256 ;
     RECT  33.721 30.384 34.657 30.984 ;
     RECT  34.657 2.832 34.693 30.984 ;
     RECT  33.635 32.064 34.693 32.328 ;
     RECT  34.357 33.312 34.729 37.656 ;
     RECT  34.513 38.784 34.729 75.144 ;
     RECT  34.693 2.832 34.808 32.328 ;
     RECT  34.729 33.312 34.808 75.144 ;
     RECT  33.761 76.224 34.808 87.336 ;
     RECT  33.443 88.368 34.808 93.336 ;
     RECT  33.689 94.848 34.808 101.928 ;
     RECT  34.189 103.008 34.808 110.088 ;
     RECT  34.369 111.12 34.808 113.256 ;
     RECT  34.808 2.148 34.912 114.492 ;
     RECT  34.912 2.304 35.104 114.222 ;
     RECT  35.104 56.256 35.165 61.512 ;
     RECT  35.104 97.392 35.165 100.344 ;
     RECT  35.165 56.256 35.201 60.072 ;
     RECT  35.104 111.12 35.219 113.592 ;
     RECT  35.165 99.984 35.273 100.344 ;
     RECT  35.104 13.056 35.309 38.184 ;
     RECT  35.104 54.72 35.309 55.272 ;
     RECT  35.219 111.12 35.315 113.256 ;
     RECT  35.309 30.384 35.345 38.184 ;
     RECT  35.104 2.304 35.381 11.88 ;
     RECT  35.165 97.392 35.381 98.952 ;
     RECT  35.104 103.296 35.417 109.704 ;
     RECT  35.201 56.256 35.489 58.536 ;
     RECT  35.104 86.304 35.489 88.44 ;
     RECT  35.309 13.056 35.525 29.256 ;
     RECT  35.489 86.496 35.561 88.44 ;
     RECT  35.525 14.208 35.603 29.256 ;
     RECT  35.603 14.208 35.705 29.112 ;
     RECT  35.381 2.304 35.777 6.552 ;
     RECT  35.345 30.384 35.795 33 ;
     RECT  35.104 62.544 35.843 84.936 ;
     RECT  35.705 14.208 36.029 18.216 ;
     RECT  35.315 111.12 36.083 113.064 ;
     RECT  36.029 14.208 36.101 18.168 ;
     RECT  35.795 30.384 36.101 32.904 ;
     RECT  35.525 13.056 36.131 13.08 ;
     RECT  35.201 59.712 36.169 60.072 ;
     RECT  35.165 61.2 36.173 61.512 ;
     RECT  35.417 103.296 36.173 106.2 ;
     RECT  35.843 62.544 36.227 82.056 ;
     RECT  35.417 107.232 36.227 109.704 ;
     RECT  36.227 107.232 36.275 109.464 ;
     RECT  35.489 56.256 36.281 58.2 ;
     RECT  36.083 113.04 36.281 113.064 ;
     RECT  35.777 4.752 36.353 6.552 ;
     RECT  35.705 19.296 36.371 29.112 ;
     RECT  35.345 34.128 36.38 38.184 ;
     RECT  35.104 39.264 36.38 53.592 ;
     RECT  36.173 61.248 36.385 61.512 ;
     RECT  36.227 62.544 36.385 68.952 ;
     RECT  35.104 89.76 36.385 96.312 ;
     RECT  36.101 14.352 36.389 18.168 ;
     RECT  35.273 99.984 36.421 100.296 ;
     RECT  35.104 101.568 36.421 102.072 ;
     RECT  36.38 34.128 36.425 53.592 ;
     RECT  35.843 83.04 36.457 84.936 ;
     RECT  36.353 4.752 36.461 6.36 ;
     RECT  36.371 22.176 36.461 29.112 ;
     RECT  36.173 103.344 36.461 106.2 ;
     RECT  36.461 22.176 36.467 29.064 ;
     RECT  36.425 34.128 36.467 40.68 ;
     RECT  36.385 89.088 36.469 96.312 ;
     RECT  35.381 97.632 36.469 98.952 ;
     RECT  36.467 22.176 36.533 23.112 ;
     RECT  36.469 89.088 36.533 98.952 ;
     RECT  35.381 7.728 36.563 11.88 ;
     RECT  36.467 34.128 36.563 38.472 ;
     RECT  36.563 9.696 36.565 11.88 ;
     RECT  35.309 55.248 36.569 55.272 ;
     RECT  36.227 70.224 36.569 82.056 ;
     RECT  36.421 99.984 36.569 102.072 ;
     RECT  36.565 9.696 36.677 12.792 ;
     RECT  35.777 2.304 36.713 3.576 ;
     RECT  36.083 111.12 36.713 111.864 ;
     RECT  36.563 7.728 36.716 8.568 ;
     RECT  36.533 90.288 36.745 98.952 ;
     RECT  36.569 99.984 36.745 101.64 ;
     RECT  36.745 90.288 36.749 101.64 ;
     RECT  36.569 70.56 36.755 82.056 ;
     RECT  36.716 7.392 36.803 8.568 ;
     RECT  36.755 81.936 36.817 82.056 ;
     RECT  36.457 83.04 36.817 85.512 ;
     RECT  36.467 39.6 36.821 40.68 ;
     RECT  36.749 91.632 36.929 101.64 ;
     RECT  36.929 97.632 36.965 101.64 ;
     RECT  36.755 70.56 36.988 80.808 ;
     RECT  36.803 7.728 37.037 8.568 ;
     RECT  36.713 111.36 37.037 111.864 ;
     RECT  36.425 41.712 37.043 53.592 ;
     RECT  36.929 91.632 37.043 96.264 ;
     RECT  37.043 52.512 37.073 53.592 ;
     RECT  36.371 19.296 37.091 20.952 ;
     RECT  36.275 107.232 37.093 107.832 ;
     RECT  37.043 91.632 37.109 94.104 ;
     RECT  36.563 34.128 37.137 38.184 ;
     RECT  37.043 41.712 37.145 51.48 ;
     RECT  37.093 106.848 37.18 107.832 ;
     RECT  36.677 11.856 37.181 12.792 ;
     RECT  36.385 61.248 37.213 68.952 ;
     RECT  36.749 90.288 37.217 90.648 ;
     RECT  36.713 2.64 37.249 3.576 ;
     RECT  36.533 89.088 37.253 89.112 ;
     RECT  37.145 50.736 37.325 51.48 ;
     RECT  37.213 61.248 37.357 69.192 ;
     RECT  36.461 103.344 37.357 105.528 ;
     RECT  37.109 92.832 37.361 94.104 ;
     RECT  36.965 97.68 37.361 101.64 ;
     RECT  36.275 109.104 37.379 109.464 ;
     RECT  36.101 30.384 37.393 30.936 ;
     RECT  37.379 109.104 37.393 109.128 ;
     RECT  36.467 24.144 37.429 29.064 ;
     RECT  37.393 30.144 37.429 30.936 ;
     RECT  36.281 57.312 37.465 58.2 ;
     RECT  36.169 59.232 37.465 60.072 ;
     RECT  37.109 91.632 37.513 91.8 ;
     RECT  36.389 14.352 37.537 14.376 ;
     RECT  36.389 15.408 37.537 18.168 ;
     RECT  36.533 22.176 37.537 23.064 ;
     RECT  37.465 57.312 37.537 60.072 ;
     RECT  37.357 61.248 37.537 69.528 ;
     RECT  37.361 97.68 37.577 99.192 ;
     RECT  37.181 12.24 37.609 12.792 ;
     RECT  37.537 14.352 37.609 18.168 ;
     RECT  37.429 24.144 37.609 30.936 ;
     RECT  36.101 32.112 37.609 32.904 ;
     RECT  36.677 9.696 37.613 10.872 ;
     RECT  37.537 57.312 37.649 69.528 ;
     RECT  35.561 86.496 37.649 87.864 ;
     RECT  37.357 103.152 37.649 105.528 ;
     RECT  37.649 57.312 37.667 61.368 ;
     RECT  37.649 62.832 37.667 69.528 ;
     RECT  36.988 70.704 37.667 80.808 ;
     RECT  37.609 24.144 37.685 32.904 ;
     RECT  37.361 100.272 37.685 101.64 ;
     RECT  37.18 107.232 37.685 107.832 ;
     RECT  37.537 22.08 37.717 23.064 ;
     RECT  37.685 24.144 37.717 27.384 ;
     RECT  36.817 81.936 37.717 85.512 ;
     RECT  37.649 86.496 37.717 86.856 ;
     RECT  37.361 93.312 37.721 94.104 ;
     RECT  37.037 111.36 37.721 111.384 ;
     RECT  37.249 2.64 37.753 3.96 ;
     RECT  36.461 5.136 37.753 6.36 ;
     RECT  37.613 9.696 37.757 10.584 ;
     RECT  36.821 40.224 37.789 40.68 ;
     RECT  37.145 41.712 37.789 49.608 ;
     RECT  37.667 70.704 37.793 77.304 ;
     RECT  37.717 81.936 37.793 86.856 ;
     RECT  37.667 78.384 37.825 80.808 ;
     RECT  37.793 81.936 37.825 86.664 ;
     RECT  37.667 62.832 37.829 69.384 ;
     RECT  37.753 2.64 37.837 6.36 ;
     RECT  37.789 40.224 37.861 49.608 ;
     RECT  37.217 90.576 37.861 90.648 ;
     RECT  37.513 91.632 37.861 91.704 ;
     RECT  37.861 39.312 37.865 49.608 ;
     RECT  37.577 97.68 37.865 98.712 ;
     RECT  37.091 20.352 37.933 20.952 ;
     RECT  37.137 34.128 37.937 37.752 ;
     RECT  37.829 67.248 37.937 69.384 ;
     RECT  37.649 87.84 37.937 87.864 ;
     RECT  37.865 97.824 37.937 98.712 ;
     RECT  37.825 78.384 37.955 86.664 ;
     RECT  37.609 12.24 37.969 18.168 ;
     RECT  37.091 19.296 37.969 19.368 ;
     RECT  37.249 54.672 37.969 54.696 ;
     RECT  37.793 70.704 37.973 77.016 ;
     RECT  37.717 22.08 38.009 27.384 ;
     RECT  37.955 81.936 38.081 86.664 ;
     RECT  37.973 73.776 38.117 77.016 ;
     RECT  37.937 34.128 38.147 37.656 ;
     RECT  37.937 69.36 38.147 69.384 ;
     RECT  37.973 70.704 38.147 72.792 ;
     RECT  37.649 104.88 38.185 105.528 ;
     RECT  38.147 70.704 38.189 71.784 ;
     RECT  37.937 97.824 38.189 98.664 ;
     RECT  37.685 100.512 38.221 101.64 ;
     RECT  37.837 2.64 38.225 3.96 ;
     RECT  38.081 82.56 38.225 85.416 ;
     RECT  38.009 23.328 38.243 27.384 ;
     RECT  38.225 83.328 38.243 85.416 ;
     RECT  37.043 95.088 38.245 96.264 ;
     RECT  37.757 10.56 38.297 10.584 ;
     RECT  38.245 95.088 38.332 96.504 ;
     RECT  37.933 20.352 38.333 21.096 ;
     RECT  38.081 86.496 38.333 86.664 ;
     RECT  37.073 52.992 38.396 53.592 ;
     RECT  37.969 54.672 38.396 55.272 ;
     RECT  37.721 93.312 38.401 93.72 ;
     RECT  38.197 88.848 38.437 88.968 ;
     RECT  37.861 90.576 38.437 91.704 ;
     RECT  37.393 108.864 38.441 109.128 ;
     RECT  38.396 52.992 38.473 55.272 ;
     RECT  36.281 56.256 38.473 56.28 ;
     RECT  37.667 57.312 38.473 60.456 ;
     RECT  38.333 20.4 38.485 21.096 ;
     RECT  38.009 22.08 38.485 22.2 ;
     RECT  38.221 100.512 38.509 102.024 ;
     RECT  37.649 103.152 38.509 103.752 ;
     RECT  37.865 42.144 38.531 49.608 ;
     RECT  38.437 87.888 38.54 91.704 ;
     RECT  38.401 92.736 38.54 93.72 ;
     RECT  38.005 110.448 38.54 110.472 ;
     RECT  38.509 100.512 38.549 103.752 ;
     RECT  37.037 7.728 38.581 7.992 ;
     RECT  38.509 8.976 38.581 9 ;
     RECT  38.485 20.4 38.585 22.2 ;
     RECT  38.54 87.888 38.585 93.72 ;
     RECT  37.865 39.312 38.621 41.16 ;
     RECT  37.325 50.736 38.621 51.432 ;
     RECT  38.54 109.68 38.627 110.472 ;
     RECT  38.473 52.896 38.629 55.272 ;
     RECT  37.829 62.832 38.653 66.216 ;
     RECT  38.549 100.512 38.653 102.648 ;
     RECT  37.969 12.24 38.657 19.368 ;
     RECT  38.531 42.144 38.657 43.032 ;
     RECT  38.189 97.824 38.657 98.184 ;
     RECT  38.332 95.088 38.712 96.024 ;
     RECT  38.653 62.688 38.725 66.216 ;
     RECT  38.185 104.88 38.725 105.96 ;
     RECT  38.473 56.256 38.729 60.456 ;
     RECT  37.955 78.384 38.729 80.376 ;
     RECT  38.531 44.352 38.761 49.608 ;
     RECT  38.621 50.736 38.761 51.384 ;
     RECT  38.725 62.496 38.761 66.216 ;
     RECT  38.629 52.752 38.773 55.272 ;
     RECT  38.761 62.256 38.797 66.216 ;
     RECT  37.937 67.248 38.797 68.376 ;
     RECT  38.657 13.296 38.801 19.368 ;
     RECT  38.585 20.4 38.801 21.096 ;
     RECT  38.243 23.328 38.801 27.288 ;
     RECT  38.147 34.128 38.801 36.36 ;
     RECT  38.147 37.584 38.801 37.656 ;
     RECT  38.729 78.384 38.833 80.136 ;
     RECT  38.801 23.328 38.837 25.992 ;
     RECT  37.685 28.464 38.837 32.904 ;
     RECT  38.621 40.416 38.837 41.16 ;
     RECT  38.729 56.256 38.837 59.736 ;
     RECT  38.621 39.312 38.869 39.384 ;
     RECT  38.801 34.128 38.873 35.352 ;
     RECT  38.761 44.352 38.873 51.384 ;
     RECT  38.725 104.112 38.905 105.96 ;
     RECT  37.685 107.232 38.905 107.592 ;
     RECT  38.801 27.264 38.909 27.288 ;
     RECT  38.837 28.464 38.941 29.4 ;
     RECT  38.801 15.984 38.945 19.368 ;
     RECT  38.873 44.448 38.945 51.384 ;
     RECT  38.797 62.256 38.945 68.376 ;
     RECT  38.905 104.112 38.945 107.592 ;
     RECT  38.945 16.512 38.981 19.368 ;
     RECT  38.873 34.368 38.981 35.352 ;
     RECT  38.585 87.888 38.981 93.528 ;
     RECT  38.653 100.224 38.981 102.648 ;
     RECT  38.585 22.08 39.013 22.2 ;
     RECT  38.837 23.328 39.013 24.984 ;
     RECT  38.837 30.384 39.017 32.904 ;
     RECT  38.945 51.312 39.017 51.384 ;
     RECT  38.117 73.824 39.02 77.016 ;
     RECT  38.225 2.64 39.053 3.72 ;
     RECT  38.581 7.728 39.053 9 ;
     RECT  39.013 22.08 39.053 24.984 ;
     RECT  39.017 30.384 39.059 30.648 ;
     RECT  39.02 73.824 39.107 77.256 ;
     RECT  38.243 83.712 39.107 85.416 ;
     RECT  38.797 11.904 39.121 12.12 ;
     RECT  39.109 60.768 39.121 60.792 ;
     RECT  39.053 7.728 39.125 8.616 ;
     RECT  39.107 83.904 39.125 85.416 ;
     RECT  38.981 87.888 39.125 90.648 ;
     RECT  38.945 104.112 39.125 107.352 ;
     RECT  39.125 83.904 39.148 85.08 ;
     RECT  38.801 37.584 39.155 37.608 ;
     RECT  38.189 70.704 39.157 70.728 ;
     RECT  38.189 71.76 39.157 71.784 ;
     RECT  38.147 72.768 39.157 72.792 ;
     RECT  38.869 38.64 39.161 39.384 ;
     RECT  38.981 92.064 39.161 93.528 ;
     RECT  38.981 100.224 39.161 102.072 ;
     RECT  39.121 60.768 39.196 61.176 ;
     RECT  38.833 78.24 39.205 80.136 ;
     RECT  38.657 42.432 39.233 43.032 ;
     RECT  39.157 70.704 39.241 72.792 ;
     RECT  38.941 28.416 39.26 29.4 ;
     RECT  39.017 31.968 39.301 32.904 ;
     RECT  38.773 52.368 39.301 55.272 ;
     RECT  38.837 56.256 39.301 58.2 ;
     RECT  38.945 62.448 39.349 68.376 ;
     RECT  38.333 86.496 39.481 86.616 ;
     RECT  39.241 70.704 39.517 71.784 ;
     RECT  39.241 72.768 39.553 72.792 ;
     RECT  39.107 73.824 39.553 76.392 ;
     RECT  39.301 99.168 39.553 99.192 ;
     RECT  37.837 5.136 39.625 6.36 ;
     RECT  39.625 5.136 39.637 6.888 ;
     RECT  38.712 94.512 39.661 96.024 ;
     RECT  38.833 97.248 39.661 97.272 ;
     RECT  39.121 11.856 39.692 12.12 ;
     RECT  38.801 13.296 39.692 14.808 ;
     RECT  39.481 86.496 39.692 86.712 ;
     RECT  39.553 98.64 39.692 99.192 ;
     RECT  39.161 100.224 39.692 100.632 ;
     RECT  39.125 104.112 39.692 106.728 ;
     RECT  39.637 5.04 39.697 6.888 ;
     RECT  39.205 77.472 39.697 80.136 ;
     RECT  39.404 81.216 39.697 81.24 ;
     RECT  39.349 62.448 39.805 68.472 ;
     RECT  39.661 94.512 39.829 97.272 ;
     RECT  39.692 98.64 39.829 100.632 ;
     RECT  38.945 44.448 39.841 50.328 ;
     RECT  38.981 34.704 39.877 35.352 ;
     RECT  39.553 36.48 39.877 36.504 ;
     RECT  39.017 51.36 39.877 51.384 ;
     RECT  39.301 52.368 39.877 58.2 ;
     RECT  39.733 10.8 39.925 10.824 ;
     RECT  39.692 11.856 39.925 14.808 ;
     RECT  38.801 20.4 39.925 20.952 ;
     RECT  39.053 22.08 39.925 24.696 ;
     RECT  39.805 62.448 39.925 69 ;
     RECT  39.517 70.416 39.925 71.784 ;
     RECT  39.301 9.696 39.932 9.72 ;
     RECT  39.925 10.8 39.932 14.808 ;
     RECT  39.161 38.64 39.973 38.76 ;
     RECT  38.981 18.816 40.021 19.368 ;
     RECT  39.925 20.4 40.021 24.696 ;
     RECT  39.301 31.968 40.069 33.048 ;
     RECT  39.925 62.448 40.069 71.784 ;
     RECT  39.053 2.64 40.208 3.576 ;
     RECT  39.697 4.8 40.208 6.888 ;
     RECT  39.125 8.16 40.208 8.616 ;
     RECT  39.932 9.696 40.208 14.808 ;
     RECT  38.981 16.512 40.208 17.304 ;
     RECT  40.021 18.816 40.208 24.696 ;
     RECT  38.837 25.968 40.208 25.992 ;
     RECT  39.26 27.36 40.208 29.4 ;
     RECT  39.059 30.528 40.208 30.648 ;
     RECT  40.069 31.92 40.208 33.048 ;
     RECT  39.877 34.704 40.208 36.504 ;
     RECT  39.973 37.872 40.208 38.76 ;
     RECT  38.837 40.416 40.208 40.872 ;
     RECT  39.233 42.432 40.208 42.792 ;
     RECT  39.841 43.824 40.208 50.328 ;
     RECT  39.877 51.36 40.208 58.2 ;
     RECT  38.837 59.184 40.208 59.736 ;
     RECT  39.196 61.152 40.208 61.176 ;
     RECT  40.069 62.208 40.208 71.784 ;
     RECT  39.553 72.768 40.208 76.392 ;
     RECT  39.697 77.472 40.208 81.24 ;
     RECT  39.445 82.656 40.208 82.68 ;
     RECT  39.148 83.904 40.208 84.6 ;
     RECT  39.692 86.448 40.208 86.712 ;
     RECT  39.125 87.888 40.208 88.536 ;
     RECT  39.125 89.952 40.208 90.648 ;
     RECT  39.161 92.064 40.208 92.088 ;
     RECT  39.161 93.072 40.208 93.528 ;
     RECT  39.829 94.512 40.208 100.632 ;
     RECT  39.161 102.048 40.208 102.072 ;
     RECT  39.692 103.728 40.208 106.728 ;
     RECT  40.208 2.148 40.312 114.492 ;
     RECT  40.312 2.418 40.504 114.222 ;
     RECT  40.504 34.896 40.565 34.92 ;
     RECT  40.504 54.624 40.565 54.744 ;
     RECT  40.504 56.88 40.565 56.904 ;
     RECT  40.565 54.72 40.601 54.744 ;
    LAYER M5 ;
     RECT  9.024 0.144 13.512 0.325 ;
     RECT  2.4 2.137 2.52 2.151 ;
     RECT  7.8 2.137 7.92 2.151 ;
     RECT  9.024 0.325 13.8 2.151 ;
     RECT  18.6 2.137 18.72 2.151 ;
     RECT  24 2.137 24.12 2.151 ;
     RECT  29.4 2.137 29.52 2.151 ;
     RECT  34.8 2.137 34.92 2.151 ;
     RECT  40.2 2.137 40.32 2.151 ;
     RECT  7.8 2.151 13.8 2.243 ;
     RECT  32.256 0.133 32.28 2.581 ;
     RECT  16.512 0.901 16.536 2.629 ;
     RECT  34.8 2.151 35.112 2.677 ;
     RECT  18.6 2.151 18.912 2.773 ;
     RECT  5.808 2.773 5.832 2.821 ;
     RECT  7.8 2.243 8.112 2.821 ;
     RECT  29.4 2.151 29.712 2.821 ;
     RECT  5.808 2.821 5.976 3.205 ;
     RECT  9.408 2.243 13.8 3.349 ;
     RECT  14.832 2.485 14.856 3.349 ;
     RECT  22.272 2.245 22.296 3.397 ;
     RECT  37.44 2.629 37.464 3.397 ;
     RECT  9.408 3.349 14.856 3.443 ;
     RECT  22.272 3.397 22.776 3.443 ;
     RECT  25.632 2.245 25.656 3.443 ;
     RECT  37.44 3.397 37.608 3.443 ;
     RECT  11.328 3.443 14.856 3.587 ;
     RECT  16.512 2.629 17.112 3.637 ;
     RECT  9.408 3.443 10.296 3.733 ;
     RECT  18.48 2.773 18.912 3.733 ;
     RECT  22.752 3.443 22.776 3.733 ;
     RECT  24 2.151 24.312 3.733 ;
     RECT  16.512 3.637 17.208 3.875 ;
     RECT  18.48 3.733 19.032 3.875 ;
     RECT  32.256 2.581 32.568 3.875 ;
     RECT  22.752 3.733 24.312 3.925 ;
     RECT  29.28 2.821 29.712 3.971 ;
     RECT  6.96 2.821 8.112 4.501 ;
     RECT  9.264 3.733 10.296 4.501 ;
     RECT  21.264 0.277 21.288 4.501 ;
     RECT  37.584 3.443 37.608 4.501 ;
     RECT  16.512 3.875 17.112 4.645 ;
     RECT  15.984 4.645 17.112 4.691 ;
     RECT  34.8 2.677 35.688 4.741 ;
     RECT  40.2 2.151 40.512 4.789 ;
     RECT  22.752 3.925 24.888 4.837 ;
     RECT  6.96 4.501 10.296 4.931 ;
     RECT  38.832 3.685 38.856 5.029 ;
     RECT  39.84 4.789 40.512 5.029 ;
     RECT  18.48 3.875 18.912 5.077 ;
     RECT  37.584 4.501 37.8 5.125 ;
     RECT  20.784 4.501 21.288 5.317 ;
     RECT  3.984 3.877 4.008 5.365 ;
     RECT  5.136 3.205 5.976 5.365 ;
     RECT  18.192 5.077 18.912 5.413 ;
     RECT  2.4 2.151 2.712 5.509 ;
     RECT  3.696 5.365 5.976 5.509 ;
     RECT  30.816 2.245 30.84 5.747 ;
     RECT  33.936 4.741 35.688 5.747 ;
     RECT  18.192 5.413 19.032 5.795 ;
     RECT  34.8 5.747 35.688 5.989 ;
     RECT  32.256 3.875 32.28 6.037 ;
     RECT  2.4 5.509 5.976 6.181 ;
     RECT  7.056 4.931 10.296 6.181 ;
     RECT  15.984 4.691 16.536 6.229 ;
     RECT  37.344 5.125 37.8 6.275 ;
     RECT  20.736 5.317 21.288 6.323 ;
     RECT  22.656 4.837 24.888 6.323 ;
     RECT  15.984 6.229 16.872 6.851 ;
     RECT  18.6 5.795 19.032 7.093 ;
     RECT  18.6 7.093 19.08 7.189 ;
     RECT  18.48 7.189 19.08 7.381 ;
     RECT  22.992 6.323 24.888 7.381 ;
     RECT  34.8 5.989 35.976 7.381 ;
     RECT  37.584 6.275 37.8 7.381 ;
     RECT  34.8 7.381 37.8 7.429 ;
     RECT  2.4 6.181 10.296 7.621 ;
     RECT  11.328 3.587 13.896 7.621 ;
     RECT  22.32 7.381 24.888 7.861 ;
     RECT  29.4 3.971 29.712 7.861 ;
     RECT  29.4 7.861 30.024 7.957 ;
     RECT  34.704 7.429 37.8 7.957 ;
     RECT  38.832 5.029 40.512 7.957 ;
     RECT  34.704 7.957 40.512 8.003 ;
     RECT  2.4 7.621 13.896 8.195 ;
     RECT  27.312 6.229 27.336 8.243 ;
     RECT  18.48 7.381 19.992 8.291 ;
     RECT  31.344 6.037 32.28 8.293 ;
     RECT  22.32 7.861 25.512 8.339 ;
     RECT  34.8 8.003 40.512 8.483 ;
     RECT  15.168 8.341 15.192 8.485 ;
     RECT  25.488 8.339 25.512 8.485 ;
     RECT  25.488 8.485 26.472 8.579 ;
     RECT  22.32 8.339 24.504 8.723 ;
     RECT  23.088 8.723 24.504 9.301 ;
     RECT  7.8 8.195 13.896 9.349 ;
     RECT  14.88 8.485 15.192 9.349 ;
     RECT  28.512 7.957 30.024 9.349 ;
     RECT  23.088 9.301 25.464 9.829 ;
     RECT  26.448 8.579 26.472 9.829 ;
     RECT  23.088 9.829 26.472 9.973 ;
     RECT  18.48 8.291 18.912 10.069 ;
     RECT  19.968 8.291 19.992 10.069 ;
     RECT  22.8 9.973 26.472 10.163 ;
     RECT  28.512 9.349 30.312 10.165 ;
     RECT  22.8 10.163 26.376 10.211 ;
     RECT  34.8 8.483 36.552 10.261 ;
     RECT  37.584 8.483 40.512 10.261 ;
     RECT  7.8 9.349 15.192 10.355 ;
     RECT  22.896 10.211 26.376 10.355 ;
     RECT  27.696 10.165 30.312 10.501 ;
     RECT  31.344 8.293 32.904 10.501 ;
     RECT  16.512 6.851 16.872 10.693 ;
     RECT  27.696 10.501 32.904 10.789 ;
     RECT  2.4 8.195 6.696 10.837 ;
     RECT  7.8 10.355 14.904 10.837 ;
     RECT  18.48 10.069 19.992 10.883 ;
     RECT  27.696 10.789 33.288 10.883 ;
     RECT  18.48 10.883 19.608 10.931 ;
     RECT  2.4 10.837 14.904 10.979 ;
     RECT  27.936 10.883 33.288 11.171 ;
     RECT  22.896 10.355 24.312 11.365 ;
     RECT  18.6 10.931 19.608 11.893 ;
     RECT  21.264 6.323 21.288 11.893 ;
     RECT  2.4 10.979 14.52 11.941 ;
     RECT  22.464 11.365 24.312 11.941 ;
     RECT  33.264 11.171 33.288 11.941 ;
     RECT  18.6 11.893 21.288 12.133 ;
     RECT  22.464 11.941 24.408 12.133 ;
     RECT  34.8 10.261 40.512 12.275 ;
     RECT  18.6 12.133 24.408 12.323 ;
     RECT  2.4 11.941 14.568 12.517 ;
     RECT  34.8 12.275 37.512 12.755 ;
     RECT  2.4 12.517 14.664 13.045 ;
     RECT  16.512 10.693 17.352 13.045 ;
     RECT  18.6 12.323 19.608 13.045 ;
     RECT  2.4 13.045 14.856 13.187 ;
     RECT  21.264 12.323 24.408 13.189 ;
     RECT  25.44 10.355 26.376 13.189 ;
     RECT  21.264 13.189 26.376 14.099 ;
     RECT  34.8 12.755 37.32 14.197 ;
     RECT  38.496 12.275 40.512 14.197 ;
     RECT  33.264 11.941 33.816 14.245 ;
     RECT  34.8 14.197 40.512 14.245 ;
     RECT  23.088 14.099 26.376 14.675 ;
     RECT  23.088 14.675 25.176 15.059 ;
     RECT  26.352 14.675 26.376 15.205 ;
     RECT  27.936 11.171 32.28 15.205 ;
     RECT  26.352 15.205 32.28 15.443 ;
     RECT  33.264 14.245 40.512 15.443 ;
     RECT  23.76 15.059 25.176 15.733 ;
     RECT  26.352 15.443 29.976 15.733 ;
     RECT  23.76 15.733 29.976 15.875 ;
     RECT  16.512 13.045 19.608 15.925 ;
     RECT  21.264 14.099 21.288 15.925 ;
     RECT  31.056 15.443 32.28 16.259 ;
     RECT  33.264 15.443 37.32 16.501 ;
     RECT  38.496 15.443 40.512 16.501 ;
     RECT  16.512 15.925 21.288 16.549 ;
     RECT  16.512 16.549 22.2 16.595 ;
     RECT  26.352 15.875 29.976 16.595 ;
     RECT  16.512 16.595 17.352 16.789 ;
     RECT  21.264 16.595 22.2 16.933 ;
     RECT  15.84 16.789 17.352 16.979 ;
     RECT  15.84 16.979 16.872 17.027 ;
     RECT  26.352 16.595 29.928 17.219 ;
     RECT  23.76 15.875 25.176 17.605 ;
     RECT  26.352 17.219 29.712 17.605 ;
     RECT  2.4 13.187 14.712 17.893 ;
     RECT  31.104 16.259 32.28 17.989 ;
     RECT  33.264 16.501 40.512 17.989 ;
     RECT  21.264 16.933 22.248 18.181 ;
     RECT  23.76 17.605 29.712 18.181 ;
     RECT  21.264 18.181 29.712 18.899 ;
     RECT  26.352 18.899 29.712 19.333 ;
     RECT  18.432 16.595 19.608 19.573 ;
     RECT  26.352 19.333 30.072 20.339 ;
     RECT  31.104 17.989 40.512 20.387 ;
     RECT  2.4 17.893 14.76 20.437 ;
     RECT  15.84 17.027 16.824 20.437 ;
     RECT  33.888 20.387 40.512 21.107 ;
     RECT  18.384 19.573 19.608 21.109 ;
     RECT  21.264 18.899 25.176 21.109 ;
     RECT  18.384 21.109 25.176 21.637 ;
     RECT  26.352 20.339 26.376 21.637 ;
     RECT  2.4 20.437 16.824 22.787 ;
     RECT  18.384 21.637 26.376 23.315 ;
     RECT  21.264 23.315 26.376 23.363 ;
     RECT  21.264 23.363 22.776 23.555 ;
     RECT  31.104 20.387 32.76 23.893 ;
     RECT  33.984 21.107 40.512 23.893 ;
     RECT  18.384 23.315 19.656 24.085 ;
     RECT  27.504 20.339 30.072 24.371 ;
     RECT  2.4 22.787 14.712 24.469 ;
     RECT  27.504 24.371 29.88 24.707 ;
     RECT  15.792 22.787 16.824 24.853 ;
     RECT  15.792 24.853 17.208 24.899 ;
     RECT  15.84 24.899 17.208 25.091 ;
     RECT  18.336 24.085 19.656 25.093 ;
     RECT  15.84 25.091 17.112 25.283 ;
     RECT  31.104 23.893 40.512 25.283 ;
     RECT  21.264 23.555 22.2 25.285 ;
     RECT  18.24 25.093 19.656 25.427 ;
     RECT  15.84 25.283 16.824 25.475 ;
     RECT  31.2 25.283 40.512 25.475 ;
     RECT  21.264 25.285 22.392 25.861 ;
     RECT  20.544 25.861 22.392 26.197 ;
     RECT  23.76 23.363 26.376 26.293 ;
     RECT  27.6 24.707 29.88 26.293 ;
     RECT  18.24 25.427 19.08 26.341 ;
     RECT  23.76 26.293 29.88 26.387 ;
     RECT  31.632 25.475 40.512 26.629 ;
     RECT  15.84 25.475 16.584 26.725 ;
     RECT  17.616 26.341 19.08 26.725 ;
     RECT  24 26.387 29.88 26.773 ;
     RECT  31.104 26.629 40.512 26.773 ;
     RECT  24 26.773 40.512 26.819 ;
     RECT  24 26.819 32.664 27.107 ;
     RECT  2.4 24.469 14.808 27.205 ;
     RECT  15.84 26.725 19.08 27.205 ;
     RECT  20.544 26.197 22.536 27.205 ;
     RECT  20.256 27.205 22.536 27.301 ;
     RECT  24 27.107 29.88 27.395 ;
     RECT  31.104 27.107 32.664 27.779 ;
     RECT  31.104 27.779 31.128 27.875 ;
     RECT  32.256 27.779 32.664 28.165 ;
     RECT  34.08 26.819 40.512 28.165 ;
     RECT  20.16 27.301 22.536 28.213 ;
     RECT  24 27.395 27.672 28.213 ;
     RECT  20.16 28.213 27.672 28.307 ;
     RECT  25.632 28.307 27.672 28.499 ;
     RECT  2.4 27.205 19.08 28.835 ;
     RECT  15.84 28.835 19.08 28.979 ;
     RECT  25.68 28.499 27.672 29.413 ;
     RECT  28.656 27.395 29.88 29.413 ;
     RECT  20.16 28.307 24.504 29.509 ;
     RECT  32.256 28.165 40.512 30.419 ;
     RECT  19.968 29.509 24.504 30.469 ;
     RECT  39.6 30.419 40.512 30.611 ;
     RECT  15.84 28.979 18.912 30.803 ;
     RECT  25.68 29.413 29.88 30.805 ;
     RECT  19.968 30.469 24.648 31.283 ;
     RECT  31.056 29.029 31.08 31.285 ;
     RECT  25.68 30.805 29.976 31.331 ;
     RECT  25.68 31.331 27.624 31.619 ;
     RECT  2.4 28.835 14.808 31.861 ;
     RECT  15.84 30.803 16.536 31.861 ;
     RECT  39.984 30.611 40.512 32.197 ;
     RECT  20.256 31.283 24.648 32.533 ;
     RECT  25.68 31.619 25.8 32.533 ;
     RECT  2.4 31.861 16.536 32.723 ;
     RECT  16.32 32.723 16.536 33.107 ;
     RECT  31.056 31.285 31.128 33.301 ;
     RECT  27.024 31.619 27.624 33.493 ;
     RECT  28.608 31.331 29.976 33.493 ;
     RECT  20.256 32.533 25.8 33.541 ;
     RECT  27.024 33.493 29.976 33.541 ;
     RECT  20.256 33.541 29.976 33.589 ;
     RECT  31.056 33.301 31.272 33.589 ;
     RECT  17.616 30.803 18.912 34.117 ;
     RECT  20.256 33.589 31.272 34.117 ;
     RECT  17.616 34.117 31.272 34.643 ;
     RECT  2.4 32.723 15.096 34.645 ;
     RECT  39.936 32.197 40.512 34.741 ;
     RECT  20.544 34.643 31.272 34.787 ;
     RECT  16.512 33.107 16.536 35.077 ;
     RECT  2.304 34.645 15.096 35.507 ;
     RECT  17.616 34.643 19.56 35.605 ;
     RECT  20.544 34.787 31.128 35.605 ;
     RECT  2.4 35.507 15.096 36.085 ;
     RECT  16.416 35.077 16.536 36.085 ;
     RECT  2.4 36.085 16.536 36.563 ;
     RECT  11.712 36.563 16.536 36.565 ;
     RECT  17.616 35.605 31.128 36.565 ;
     RECT  11.712 36.565 31.128 36.707 ;
     RECT  11.712 36.707 19.56 36.899 ;
     RECT  20.544 36.707 31.128 37.043 ;
     RECT  17.616 36.899 19.56 37.427 ;
     RECT  11.712 36.899 16.536 37.475 ;
     RECT  39.312 34.741 40.512 37.573 ;
     RECT  20.736 37.043 31.128 38.435 ;
     RECT  15.072 37.475 16.536 38.725 ;
     RECT  17.616 37.427 18.912 38.725 ;
     RECT  2.4 36.563 10.632 39.253 ;
     RECT  11.712 37.475 13.896 39.253 ;
     RECT  15.072 38.725 18.912 39.301 ;
     RECT  2.4 39.253 13.896 39.877 ;
     RECT  15.072 39.301 19.416 39.877 ;
     RECT  32.256 30.419 38.136 40.165 ;
     RECT  39.12 37.573 40.512 40.165 ;
     RECT  20.736 38.435 27.624 40.741 ;
     RECT  28.608 38.435 31.128 40.741 ;
     RECT  2.4 39.877 19.416 41.027 ;
     RECT  2.4 41.027 18.912 41.411 ;
     RECT  20.736 40.741 31.128 42.181 ;
     RECT  32.256 40.165 40.512 42.181 ;
     RECT  20.736 42.181 40.512 42.227 ;
     RECT  11.712 41.411 18.912 42.469 ;
     RECT  20.736 42.227 35.256 42.803 ;
     RECT  11.712 42.469 19.08 43.093 ;
     RECT  21.264 42.803 35.256 43.525 ;
     RECT  36.432 42.227 40.512 43.907 ;
     RECT  2.4 41.411 10.632 44.387 ;
     RECT  11.712 43.093 19.464 44.483 ;
     RECT  21.264 43.525 35.352 44.771 ;
     RECT  15.744 44.483 19.464 44.773 ;
     RECT  11.712 44.483 14.616 45.589 ;
     RECT  15.744 44.773 19.752 45.589 ;
     RECT  21.264 44.771 35.256 45.589 ;
     RECT  2.4 44.387 10.296 46.501 ;
     RECT  11.424 45.589 19.752 46.501 ;
     RECT  20.88 45.589 35.256 46.789 ;
     RECT  36.576 43.907 40.512 46.789 ;
     RECT  20.88 46.789 40.512 46.835 ;
     RECT  2.4 46.501 19.752 46.837 ;
     RECT  2.4 46.837 19.944 47.027 ;
     RECT  21.264 46.835 40.512 47.075 ;
     RECT  21.264 47.075 37.368 47.411 ;
     RECT  2.4 47.027 19.608 48.275 ;
     RECT  21.36 47.411 37.368 48.371 ;
     RECT  21.936 48.371 37.368 48.467 ;
     RECT  38.736 47.075 40.512 48.709 ;
     RECT  38.64 48.709 40.512 48.757 ;
     RECT  22.176 48.467 37.368 48.853 ;
     RECT  38.448 48.757 40.512 48.853 ;
     RECT  22.176 48.853 40.512 49.283 ;
     RECT  15.744 48.275 19.608 49.333 ;
     RECT  15.744 49.333 19.992 49.525 ;
     RECT  22.464 49.283 40.512 49.667 ;
     RECT  15.744 49.525 20.76 50.723 ;
     RECT  31.104 49.667 40.512 50.771 ;
     RECT  22.464 49.667 29.928 50.821 ;
     RECT  22.464 50.821 30.024 51.109 ;
     RECT  22.08 51.109 30.024 51.637 ;
     RECT  31.104 50.771 35.736 51.637 ;
     RECT  37.104 50.771 40.512 52.309 ;
     RECT  15.744 50.723 19.992 52.357 ;
     RECT  36.816 52.309 40.512 52.453 ;
     RECT  22.08 51.637 35.736 52.499 ;
     RECT  31.104 52.499 35.736 52.501 ;
     RECT  36.768 52.453 40.512 52.501 ;
     RECT  22.08 52.499 30.024 53.075 ;
     RECT  31.104 52.501 40.512 53.603 ;
     RECT  2.4 48.275 14.568 54.131 ;
     RECT  15.744 52.357 20.952 54.371 ;
     RECT  22.08 53.075 29.928 54.419 ;
     RECT  15.744 54.371 20.568 54.659 ;
     RECT  22.176 54.419 29.928 55.237 ;
     RECT  31.104 53.603 35.928 55.237 ;
     RECT  22.176 55.237 35.928 55.283 ;
     RECT  2.4 54.131 14.232 55.331 ;
     RECT  16.416 54.659 20.568 55.331 ;
     RECT  16.416 55.331 20.04 55.859 ;
     RECT  16.416 55.859 16.536 56.869 ;
     RECT  17.712 55.859 20.04 56.869 ;
     RECT  2.4 55.331 13.896 57.059 ;
     RECT  16.416 56.869 20.04 57.059 ;
     RECT  0.24 14.869 0.264 57.395 ;
     RECT  28.368 55.283 35.736 57.443 ;
     RECT  22.176 55.283 27 57.731 ;
     RECT  11.136 57.059 13.896 57.875 ;
     RECT  16.416 57.059 19.992 57.971 ;
     RECT  21.024 57.589 21.048 58.067 ;
     RECT  34.176 57.443 35.736 58.117 ;
     RECT  11.376 57.875 13.896 58.163 ;
     RECT  2.4 57.059 9.48 58.645 ;
     RECT  28.368 57.443 33.048 58.645 ;
     RECT  34.176 58.117 35.832 58.645 ;
     RECT  2.4 58.645 10.392 58.835 ;
     RECT  11.424 58.163 13.896 58.933 ;
     RECT  11.424 58.933 13.944 59.075 ;
     RECT  16.416 57.971 16.584 59.461 ;
     RECT  17.712 57.971 19.992 59.461 ;
     RECT  21.408 59.173 21.432 59.701 ;
     RECT  22.512 57.731 27 59.701 ;
     RECT  6.576 58.835 10.392 59.795 ;
     RECT  2.4 58.835 5.256 59.797 ;
     RECT  6.576 59.795 9.48 59.797 ;
     RECT  15.12 57.541 15.144 59.797 ;
     RECT  16.416 59.461 19.992 59.797 ;
     RECT  28.368 58.645 35.832 59.797 ;
     RECT  11.424 59.075 13.896 60.085 ;
     RECT  15.12 59.797 19.992 60.085 ;
     RECT  11.424 60.085 19.992 60.133 ;
     RECT  21.408 59.701 27 60.229 ;
     RECT  10.848 60.133 19.992 60.277 ;
     RECT  21.12 60.229 27 60.277 ;
     RECT  10.848 60.277 27 60.467 ;
     RECT  10.848 60.467 15.48 61.043 ;
     RECT  2.4 59.797 9.48 61.331 ;
     RECT  15.12 61.043 15.48 61.429 ;
     RECT  16.512 60.467 27 61.429 ;
     RECT  28.176 59.797 35.832 61.619 ;
     RECT  15.12 61.429 27 62.243 ;
     RECT  10.848 61.043 13.896 62.723 ;
     RECT  28.176 61.619 33.336 62.725 ;
     RECT  15.12 62.243 19.896 62.819 ;
     RECT  28.176 62.725 33.528 62.821 ;
     RECT  34.512 61.619 35.832 62.821 ;
     RECT  15.12 62.819 19.8 63.829 ;
     RECT  21.12 62.243 27 63.829 ;
     RECT  37.104 53.603 40.512 63.877 ;
     RECT  11.424 62.723 13.896 64.165 ;
     RECT  28.176 62.821 35.832 64.357 ;
     RECT  36.864 63.877 40.512 64.357 ;
     RECT  28.176 64.357 40.512 64.835 ;
     RECT  11.04 64.165 13.896 64.979 ;
     RECT  15.12 63.829 27 65.267 ;
     RECT  28.272 64.835 40.512 65.267 ;
     RECT  2.4 61.331 5.256 66.085 ;
     RECT  15.12 65.267 24.408 66.179 ;
     RECT  28.272 65.267 35.4 66.323 ;
     RECT  15.264 66.179 24.408 66.469 ;
     RECT  25.392 65.267 27 66.469 ;
     RECT  31.68 66.323 35.4 66.755 ;
     RECT  11.424 64.979 13.896 66.803 ;
     RECT  15.264 66.469 27 67.139 ;
     RECT  34.608 66.755 35.4 67.283 ;
     RECT  28.272 66.323 30.552 67.285 ;
     RECT  36.864 65.267 40.512 67.285 ;
     RECT  2.304 66.085 5.256 67.427 ;
     RECT  11.52 66.803 13.896 67.765 ;
     RECT  15.264 67.139 20.424 67.765 ;
     RECT  21.456 67.139 27 68.293 ;
     RECT  34.608 67.283 35.256 68.341 ;
     RECT  36.576 67.285 40.512 68.341 ;
     RECT  11.52 67.765 20.424 68.387 ;
     RECT  28.272 67.285 30.6 68.581 ;
     RECT  31.68 66.755 33.528 68.581 ;
     RECT  21.456 68.293 27.144 68.677 ;
     RECT  28.272 68.581 33.528 68.723 ;
     RECT  34.608 68.341 40.512 68.723 ;
     RECT  11.52 68.387 20.28 68.963 ;
     RECT  6.576 61.331 9.48 69.251 ;
     RECT  11.52 68.963 19.224 70.453 ;
     RECT  20.256 68.963 20.28 70.453 ;
     RECT  31.68 68.723 33.528 70.501 ;
     RECT  21.456 68.677 27.192 70.645 ;
     RECT  28.272 68.723 30.6 70.645 ;
     RECT  31.632 70.501 33.528 70.645 ;
     RECT  34.8 68.723 40.512 70.645 ;
     RECT  11.52 70.453 20.28 70.787 ;
     RECT  21.456 70.645 30.648 70.787 ;
     RECT  11.52 70.787 20.088 70.835 ;
     RECT  6.576 69.251 9.192 71.651 ;
     RECT  21.648 70.787 30.648 71.797 ;
     RECT  31.632 70.645 40.512 71.797 ;
     RECT  11.52 70.835 11.544 71.891 ;
     RECT  12.528 70.835 20.088 72.037 ;
     RECT  21.648 71.797 40.512 72.805 ;
     RECT  11.808 72.037 20.088 72.851 ;
     RECT  21.12 72.805 40.512 73.043 ;
     RECT  11.808 72.851 13.896 73.957 ;
     RECT  15.504 72.851 20.088 73.957 ;
     RECT  21.12 73.043 30.36 74.147 ;
     RECT  31.68 73.043 40.512 74.195 ;
     RECT  21.12 74.147 28.104 74.243 ;
     RECT  11.808 73.957 20.088 74.627 ;
     RECT  31.68 74.195 37.656 75.109 ;
     RECT  21.12 74.243 27.288 75.299 ;
     RECT  15.12 74.627 20.088 75.443 ;
     RECT  11.808 74.627 13.896 75.781 ;
     RECT  21.408 75.299 27.288 75.781 ;
     RECT  11.808 75.781 14.136 76.403 ;
     RECT  15.12 75.443 19.752 76.403 ;
     RECT  21.408 75.781 27.48 76.403 ;
     RECT  39.072 74.195 40.512 77.267 ;
     RECT  2.4 67.427 5.256 77.507 ;
     RECT  15.504 76.403 19.752 77.555 ;
     RECT  31.392 75.109 37.656 77.555 ;
     RECT  11.808 76.403 13.992 77.603 ;
     RECT  39.216 77.267 40.512 78.611 ;
     RECT  21.408 76.403 27.288 78.613 ;
     RECT  31.392 77.555 37.464 78.659 ;
     RECT  15.504 77.555 15.768 78.899 ;
     RECT  29.232 74.147 30.36 78.947 ;
     RECT  31.392 78.659 37.32 79.189 ;
     RECT  16.848 77.555 19.752 79.235 ;
     RECT  21.408 78.613 27.384 79.525 ;
     RECT  17.376 79.235 19.752 79.717 ;
     RECT  17.376 79.717 20.376 79.765 ;
     RECT  21.408 79.525 27.528 79.765 ;
     RECT  31.344 79.189 37.32 79.957 ;
     RECT  15.504 78.899 15.72 80.147 ;
     RECT  31.344 79.957 37.608 80.147 ;
     RECT  11.808 77.603 13.512 80.531 ;
     RECT  10.8 79.045 10.824 80.867 ;
     RECT  17.376 79.765 27.528 80.869 ;
     RECT  9.12 71.651 9.192 81.205 ;
     RECT  31.344 80.147 37.464 81.205 ;
     RECT  31.344 81.205 37.944 81.347 ;
     RECT  12.096 80.531 13.512 81.539 ;
     RECT  31.584 81.347 37.944 82.549 ;
     RECT  15.696 80.147 15.72 82.597 ;
     RECT  39.456 78.611 40.512 82.691 ;
     RECT  17.28 80.869 27.528 82.739 ;
     RECT  15.696 82.597 16.008 82.837 ;
     RECT  29.4 78.947 30.36 83.029 ;
     RECT  12.528 81.539 13.512 83.173 ;
     RECT  31.44 82.549 37.944 83.317 ;
     RECT  31.44 83.317 38.232 83.701 ;
     RECT  39.552 82.691 40.512 83.701 ;
     RECT  15.696 82.837 16.44 83.795 ;
     RECT  15.696 83.795 15.72 84.323 ;
     RECT  29.4 83.029 30.456 84.325 ;
     RECT  31.44 83.701 40.512 84.325 ;
     RECT  29.4 84.325 40.512 85.091 ;
     RECT  17.616 82.739 27.528 86.579 ;
     RECT  29.4 85.091 38.232 86.581 ;
     RECT  17.664 86.579 27.528 86.867 ;
     RECT  17.664 86.867 25.704 87.251 ;
     RECT  29.184 86.581 38.232 88.355 ;
     RECT  29.4 88.355 38.232 88.933 ;
     RECT  39.312 85.091 40.512 88.933 ;
     RECT  29.4 88.933 40.512 88.979 ;
     RECT  27.024 86.867 27.528 89.125 ;
     RECT  20.88 87.251 25.704 89.411 ;
     RECT  2.4 77.507 4.776 89.555 ;
     RECT  11.904 83.173 13.512 89.989 ;
     RECT  14.544 84.277 14.568 89.989 ;
     RECT  6.576 71.651 8.112 90.037 ;
     RECT  9.12 81.205 10.008 90.037 ;
     RECT  27.024 89.125 27.864 90.227 ;
     RECT  20.88 89.411 25.656 90.373 ;
     RECT  27.024 90.227 27.528 90.373 ;
     RECT  20.88 90.373 27.528 90.611 ;
     RECT  6.576 90.037 10.008 90.851 ;
     RECT  29.4 88.979 37.464 90.901 ;
     RECT  6.576 90.851 8.112 91.141 ;
     RECT  29.28 90.901 37.464 91.141 ;
     RECT  20.88 90.611 25.8 91.187 ;
     RECT  29.232 91.141 37.464 91.333 ;
     RECT  29.136 91.333 37.464 91.429 ;
     RECT  38.448 88.979 40.512 91.429 ;
     RECT  29.136 91.429 40.512 91.475 ;
     RECT  17.664 87.251 19.896 91.621 ;
     RECT  20.88 91.187 25.656 91.621 ;
     RECT  29.232 91.475 40.512 91.763 ;
     RECT  31.536 91.763 40.512 91.811 ;
     RECT  6.048 91.141 8.112 92.005 ;
     RECT  9.12 90.851 10.008 92.005 ;
     RECT  11.904 89.989 14.568 92.005 ;
     RECT  11.568 92.005 14.568 92.339 ;
     RECT  29.232 91.763 30.36 92.869 ;
     RECT  31.536 91.811 36.6 92.869 ;
     RECT  6.048 92.005 10.008 92.963 ;
     RECT  11.568 92.339 13.512 93.107 ;
     RECT  27.024 90.611 27.528 93.253 ;
     RECT  29.232 92.869 36.6 93.301 ;
     RECT  37.872 91.811 40.512 93.301 ;
     RECT  29.232 93.301 40.512 93.539 ;
     RECT  29.232 93.539 36.024 93.731 ;
     RECT  14.544 92.339 14.568 93.733 ;
     RECT  15.936 90.229 15.96 93.733 ;
     RECT  14.544 93.733 15.96 93.779 ;
     RECT  29.232 93.731 35.112 93.779 ;
     RECT  4.752 89.555 4.776 93.925 ;
     RECT  6.048 92.963 9.144 93.925 ;
     RECT  27.024 93.253 27.768 94.021 ;
     RECT  17.664 91.621 25.656 94.357 ;
     RECT  27.024 94.021 27.912 94.357 ;
     RECT  29.4 93.779 35.112 94.933 ;
     RECT  17.664 94.357 27.912 95.125 ;
     RECT  37.008 93.539 40.512 95.219 ;
     RECT  10.8 93.397 10.824 95.365 ;
     RECT  29.4 94.933 35.928 95.413 ;
     RECT  10.656 95.365 10.824 95.461 ;
     RECT  11.904 93.107 13.512 95.461 ;
     RECT  4.752 93.925 9.144 95.557 ;
     RECT  4.752 95.557 9.672 95.605 ;
     RECT  10.656 95.461 13.512 95.605 ;
     RECT  4.752 95.605 13.512 95.795 ;
     RECT  17.616 95.125 27.912 95.939 ;
     RECT  29.088 95.413 35.928 96.037 ;
     RECT  28.896 96.037 35.928 96.277 ;
     RECT  37.344 95.219 40.512 96.277 ;
     RECT  18.048 95.939 27.912 96.325 ;
     RECT  28.896 96.277 40.512 96.325 ;
     RECT  18.048 96.325 40.512 96.467 ;
     RECT  31.536 96.467 40.512 96.515 ;
     RECT  31.536 96.515 37.368 96.947 ;
     RECT  6.576 95.795 13.512 96.995 ;
     RECT  18.048 96.467 29.712 97.331 ;
     RECT  31.536 96.947 35.928 97.621 ;
     RECT  21.36 97.331 29.712 97.763 ;
     RECT  18.048 97.331 19.944 97.909 ;
     RECT  6.576 96.995 8.424 97.957 ;
     RECT  6.336 97.957 8.424 98.005 ;
     RECT  9.648 96.995 13.512 98.005 ;
     RECT  2.4 89.555 3.672 98.099 ;
     RECT  21.36 97.763 28.104 98.387 ;
     RECT  31.104 97.621 35.928 98.629 ;
     RECT  14.544 93.779 15.384 99.157 ;
     RECT  17.952 97.909 19.944 99.157 ;
     RECT  37.344 96.947 37.368 99.157 ;
     RECT  2.4 98.099 3.336 99.203 ;
     RECT  6.336 98.005 13.512 99.203 ;
     RECT  29.4 97.763 29.712 99.541 ;
     RECT  17.952 99.157 20.04 99.587 ;
     RECT  14.544 99.157 16.008 99.683 ;
     RECT  21.36 98.387 27.48 99.683 ;
     RECT  4.752 95.795 4.776 99.685 ;
     RECT  6.336 99.203 10.968 99.685 ;
     RECT  28.992 99.541 29.712 99.685 ;
     RECT  2.4 99.203 2.808 99.731 ;
     RECT  4.752 99.685 10.968 99.779 ;
     RECT  18.048 99.587 20.04 99.779 ;
     RECT  31.104 98.629 36.024 100.021 ;
     RECT  37.056 99.157 37.368 100.021 ;
     RECT  15.072 99.683 16.008 100.261 ;
     RECT  4.752 99.779 9.096 100.355 ;
     RECT  15.072 100.261 16.536 100.355 ;
     RECT  12.24 99.203 13.512 100.499 ;
     RECT  18.048 99.779 19.944 100.645 ;
     RECT  10.176 99.779 10.968 100.693 ;
     RECT  7.392 100.355 9.096 100.789 ;
     RECT  10.176 100.693 11.448 100.789 ;
     RECT  31.104 100.021 37.368 100.789 ;
     RECT  38.448 96.515 40.512 100.789 ;
     RECT  31.104 100.789 40.512 100.835 ;
     RECT  28.752 99.685 29.712 100.931 ;
     RECT  16.512 100.355 16.536 101.027 ;
     RECT  17.856 100.645 19.944 101.075 ;
     RECT  31.104 100.835 38.232 101.651 ;
     RECT  4.752 100.355 6.36 101.989 ;
     RECT  7.392 100.789 11.448 101.989 ;
     RECT  28.8 100.931 29.712 101.989 ;
     RECT  31.104 101.651 37.368 101.989 ;
     RECT  39.312 100.835 40.512 102.083 ;
     RECT  17.856 101.075 19.704 102.133 ;
     RECT  2.4 99.731 2.712 102.613 ;
     RECT  2.4 102.613 2.808 102.947 ;
     RECT  28.8 101.989 37.368 103.235 ;
     RECT  16.32 101.317 16.344 103.379 ;
     RECT  4.752 101.989 11.448 103.381 ;
     RECT  21.36 99.683 27.384 103.475 ;
     RECT  30.816 103.235 37.368 103.523 ;
     RECT  17.856 102.133 19.992 103.717 ;
     RECT  39.744 102.083 40.512 103.763 ;
     RECT  4.752 103.381 11.688 104.245 ;
     RECT  38.928 104.101 38.952 104.245 ;
     RECT  16.224 103.717 16.248 104.291 ;
     RECT  4.32 104.245 11.688 104.435 ;
     RECT  30.816 103.523 33.816 104.531 ;
     RECT  30.816 104.531 32.952 104.675 ;
     RECT  5.76 104.435 11.688 104.773 ;
     RECT  28.8 103.235 29.712 104.773 ;
     RECT  21.36 103.475 26.28 104.821 ;
     RECT  27.36 103.475 27.384 104.821 ;
     RECT  21.36 104.821 27.384 104.867 ;
     RECT  38.736 104.245 38.952 105.155 ;
     RECT  21.36 104.867 25.32 105.395 ;
     RECT  30.816 104.675 32.616 105.395 ;
     RECT  34.8 103.523 37.368 105.395 ;
     RECT  4.32 104.435 4.776 105.683 ;
     RECT  5.76 104.773 11.784 105.779 ;
     RECT  17.808 103.717 19.992 105.781 ;
     RECT  21.36 105.395 25.176 105.781 ;
     RECT  38.928 105.155 38.952 105.781 ;
     RECT  40.2 103.763 40.512 105.781 ;
     RECT  31.2 105.395 32.616 105.973 ;
     RECT  13.2 100.499 13.512 106.357 ;
     RECT  15.072 100.355 15.096 106.357 ;
     RECT  6.048 105.779 11.784 106.453 ;
     RECT  17.808 105.781 25.176 106.643 ;
     RECT  17.808 106.643 22.152 106.691 ;
     RECT  38.928 105.781 40.512 106.739 ;
     RECT  34.8 105.395 36.264 106.837 ;
     RECT  37.344 105.395 37.368 106.837 ;
     RECT  28.8 104.773 29.832 107.075 ;
     RECT  6.048 106.453 11.976 107.125 ;
     RECT  26.4 104.867 27.384 107.125 ;
     RECT  38.928 106.739 38.952 107.267 ;
     RECT  31.2 105.973 32.76 107.317 ;
     RECT  26.4 107.125 27.672 107.363 ;
     RECT  6.048 107.125 12.12 107.413 ;
     RECT  30.816 107.317 32.76 107.507 ;
     RECT  26.736 107.363 27.672 107.603 ;
     RECT  2.4 102.947 2.712 107.653 ;
     RECT  13.2 106.357 15.096 107.795 ;
     RECT  4.752 105.683 4.776 107.797 ;
     RECT  5.904 107.413 12.12 107.797 ;
     RECT  34.8 106.837 37.368 107.843 ;
     RECT  27.648 107.603 27.672 107.845 ;
     RECT  23.472 106.643 25.176 107.941 ;
     RECT  23.472 107.941 25.704 108.085 ;
     RECT  2.4 107.653 3.048 108.227 ;
     RECT  4.752 107.797 12.12 108.323 ;
     RECT  28.8 107.075 29.712 108.323 ;
     RECT  34.8 107.843 36.264 108.323 ;
     RECT  5.088 108.323 12.12 108.611 ;
     RECT  18.192 106.691 22.152 108.851 ;
     RECT  13.2 107.795 14.76 108.899 ;
     RECT  18.192 108.851 19.656 108.947 ;
     RECT  30.816 107.507 31.704 108.947 ;
     RECT  5.904 108.611 12.12 109.093 ;
     RECT  13.2 108.899 13.512 109.093 ;
     RECT  2.4 108.227 2.712 109.381 ;
     RECT  23.328 108.085 25.704 109.475 ;
     RECT  37.344 107.843 37.368 109.475 ;
     RECT  23.424 109.475 25.704 109.523 ;
     RECT  34.8 108.323 36.216 109.715 ;
     RECT  21.36 108.851 22.152 109.957 ;
     RECT  2.4 109.381 3.144 110.051 ;
     RECT  18.432 108.947 19.656 110.051 ;
     RECT  27.648 107.845 27.768 110.243 ;
     RECT  38.592 107.557 38.616 110.483 ;
     RECT  18.432 110.051 18.912 110.627 ;
     RECT  32.736 107.507 32.76 110.819 ;
     RECT  21.168 109.957 22.152 110.867 ;
     RECT  5.904 109.093 13.512 111.109 ;
     RECT  21.168 110.867 21.384 111.203 ;
     RECT  27.648 110.243 27.672 111.347 ;
     RECT  31.68 108.947 31.704 111.445 ;
     RECT  5.616 111.109 13.512 111.685 ;
     RECT  14.736 108.899 14.76 111.685 ;
     RECT  23.424 109.523 25.368 111.685 ;
     RECT  30.816 111.445 31.704 111.685 ;
     RECT  5.616 111.685 14.76 111.779 ;
     RECT  30.816 111.685 32.136 111.875 ;
     RECT  34.8 109.715 36.072 112.259 ;
     RECT  32.112 111.875 32.136 112.307 ;
     RECT  5.616 111.779 14.28 112.355 ;
     RECT  5.616 112.355 5.64 112.403 ;
     RECT  30.816 111.875 30.84 112.643 ;
     RECT  29.4 108.323 29.712 112.645 ;
     RECT  21.168 111.203 21.192 112.837 ;
     RECT  21.072 112.837 21.192 112.883 ;
     RECT  23.424 111.685 25.56 112.883 ;
     RECT  7.2 112.355 14.28 113.075 ;
     RECT  7.2 113.075 13.512 113.219 ;
     RECT  23.424 112.883 24.312 113.219 ;
     RECT  7.44 113.219 13.512 113.267 ;
     RECT  25.536 112.883 25.56 113.267 ;
     RECT  34.8 112.259 35.304 113.267 ;
     RECT  29.28 112.645 29.712 113.317 ;
     RECT  18.48 110.627 18.912 113.459 ;
     RECT  34.8 113.267 35.208 113.603 ;
     RECT  21.072 112.883 21.096 113.747 ;
     RECT  26.688 111.637 26.712 113.747 ;
     RECT  7.584 113.267 13.512 113.987 ;
     RECT  7.584 113.987 11.544 114.035 ;
     RECT  28.56 113.317 29.712 114.035 ;
     RECT  13.104 113.987 13.512 114.131 ;
     RECT  7.584 114.035 10.344 114.179 ;
     RECT  29.28 114.035 29.712 114.275 ;
     RECT  2.4 110.051 2.712 114.489 ;
     RECT  7.8 114.179 10.344 114.489 ;
     RECT  13.2 114.131 13.512 114.489 ;
     RECT  18.6 113.459 18.912 114.489 ;
     RECT  24 113.219 24.312 114.489 ;
     RECT  29.4 114.275 29.712 114.489 ;
     RECT  34.8 113.603 35.112 114.489 ;
     RECT  40.2 106.739 40.512 114.489 ;
     RECT  2.4 114.489 2.52 114.503 ;
     RECT  7.8 114.489 7.92 114.503 ;
     RECT  13.2 114.489 13.32 114.503 ;
     RECT  18.6 114.489 18.72 114.503 ;
     RECT  24 114.489 24.12 114.503 ;
     RECT  29.4 114.489 29.52 114.503 ;
     RECT  34.8 114.489 34.92 114.503 ;
     RECT  40.2 114.489 40.32 114.503 ;
     RECT  9.024 114.489 10.344 115.141 ;
     RECT  11.52 114.035 11.544 115.141 ;
     RECT  9.024 115.141 11.544 115.763 ;
     RECT  9.024 115.763 11.208 116.496 ;
     RECT  7.92 2.137 9.024 2.151 ;
     RECT  8.112 2.243 9.408 3.733 ;
     RECT  21.288 2.245 22.272 3.443 ;
     RECT  24.312 2.245 25.632 3.443 ;
     RECT  29.712 2.245 30.816 5.747 ;
     RECT  30.84 2.245 32.256 5.747 ;
     RECT  13.8 2.485 14.832 3.349 ;
     RECT  17.112 2.629 18.6 2.773 ;
     RECT  17.112 2.773 18.48 3.637 ;
     RECT  5.976 2.821 6.96 4.931 ;
     RECT  22.776 3.397 24 3.733 ;
     RECT  10.296 3.443 11.328 7.621 ;
     RECT  21.288 3.443 22.752 4.837 ;
     RECT  24.312 3.443 24.888 3.925 ;
     RECT  17.208 3.637 18.48 3.875 ;
     RECT  37.608 3.685 38.832 4.501 ;
     RECT  38.856 3.685 40.2 4.789 ;
     RECT  8.112 3.733 9.264 4.501 ;
     RECT  17.112 3.875 18.48 4.691 ;
     RECT  2.712 3.877 3.984 5.365 ;
     RECT  4.008 3.877 5.136 5.365 ;
     RECT  37.8 4.501 38.832 7.957 ;
     RECT  18.192 4.691 18.48 5.077 ;
     RECT  38.856 4.789 39.84 5.029 ;
     RECT  21.288 4.837 22.656 6.323 ;
     RECT  5.976 4.931 7.056 6.181 ;
     RECT  2.712 5.365 3.696 5.509 ;
     RECT  31.344 5.747 32.256 6.037 ;
     RECT  18.48 5.795 18.6 7.189 ;
     RECT  35.976 5.989 37.344 6.275 ;
     RECT  35.976 6.275 37.584 7.381 ;
     RECT  20.736 6.323 21.264 7.381 ;
     RECT  21.288 6.323 22.992 7.381 ;
     RECT  15.984 6.851 16.512 8.341 ;
     RECT  19.992 7.381 21.264 10.883 ;
     RECT  21.288 7.381 22.32 8.723 ;
     RECT  30.024 7.861 31.344 9.349 ;
     RECT  27.336 7.957 28.512 8.243 ;
     RECT  6.696 8.195 7.8 10.837 ;
     RECT  18.912 8.291 19.968 10.069 ;
     RECT  24.504 8.339 25.488 8.579 ;
     RECT  13.896 8.341 15.168 8.485 ;
     RECT  15.192 8.341 16.512 10.355 ;
     RECT  36.552 8.483 37.584 10.261 ;
     RECT  13.896 8.485 14.88 9.349 ;
     RECT  24.504 8.579 26.448 9.301 ;
     RECT  21.288 8.723 23.088 9.973 ;
     RECT  25.464 9.301 26.448 9.829 ;
     RECT  30.312 9.349 31.344 10.501 ;
     RECT  21.288 9.973 22.8 10.211 ;
     RECT  26.376 10.163 26.472 10.165 ;
     RECT  26.376 10.165 27.696 10.883 ;
     RECT  21.288 10.211 22.896 11.365 ;
     RECT  24.312 10.355 25.44 11.941 ;
     RECT  17.352 10.693 18.48 10.931 ;
     RECT  33.288 10.789 34.8 11.941 ;
     RECT  19.608 10.883 21.264 11.893 ;
     RECT  17.352 10.931 18.6 13.045 ;
     RECT  14.52 10.979 14.568 11.941 ;
     RECT  32.28 11.171 33.264 17.989 ;
     RECT  21.288 11.365 22.464 12.133 ;
     RECT  24.408 11.941 25.44 13.189 ;
     RECT  33.816 11.941 34.8 14.245 ;
     RECT  37.512 12.275 38.496 12.755 ;
     RECT  37.32 12.755 38.496 14.197 ;
     RECT  25.176 14.675 26.352 15.733 ;
     RECT  29.976 15.443 31.056 16.259 ;
     RECT  37.32 15.443 38.496 16.501 ;
     RECT  25.176 15.875 26.352 17.605 ;
     RECT  29.976 16.259 31.104 16.595 ;
     RECT  17.352 16.595 18.432 16.979 ;
     RECT  29.928 16.595 31.104 17.219 ;
     RECT  14.712 16.789 15.84 17.893 ;
     RECT  22.248 16.933 23.76 18.181 ;
     RECT  29.712 17.219 31.104 19.333 ;
     RECT  14.76 17.893 15.84 20.437 ;
     RECT  25.176 18.899 26.352 21.637 ;
     RECT  30.072 19.333 31.104 24.371 ;
     RECT  26.376 20.339 27.504 24.707 ;
     RECT  32.76 20.387 33.888 21.107 ;
     RECT  32.76 21.107 33.984 23.893 ;
     RECT  14.712 22.787 15.792 24.469 ;
     RECT  22.776 23.363 23.76 23.555 ;
     RECT  16.824 24.085 18.336 24.853 ;
     RECT  29.88 24.371 31.104 25.283 ;
     RECT  14.808 24.469 15.792 24.899 ;
     RECT  26.376 24.707 27.6 26.293 ;
     RECT  17.208 24.853 18.336 25.091 ;
     RECT  14.808 24.899 15.84 27.205 ;
     RECT  17.112 25.091 18.336 25.093 ;
     RECT  17.112 25.093 18.24 25.283 ;
     RECT  16.824 25.283 18.24 25.475 ;
     RECT  29.88 25.283 31.2 25.475 ;
     RECT  22.392 25.285 23.76 26.197 ;
     RECT  19.08 25.427 19.656 25.861 ;
     RECT  16.584 25.475 18.24 26.341 ;
     RECT  29.88 25.475 31.632 26.629 ;
     RECT  19.08 25.861 20.544 27.205 ;
     RECT  22.536 26.197 23.76 26.387 ;
     RECT  16.584 26.341 17.616 26.725 ;
     RECT  22.536 26.387 24 28.213 ;
     RECT  29.88 26.629 31.104 26.773 ;
     RECT  32.664 26.819 34.08 28.165 ;
     RECT  29.88 27.107 31.104 27.875 ;
     RECT  19.08 27.205 20.256 27.301 ;
     RECT  19.08 27.301 20.16 28.979 ;
     RECT  27.672 27.395 28.656 29.413 ;
     RECT  31.128 27.779 32.256 27.875 ;
     RECT  29.88 27.875 32.256 29.029 ;
     RECT  24.504 28.307 25.632 28.499 ;
     RECT  24.504 28.499 25.68 30.469 ;
     RECT  14.808 28.835 15.84 31.861 ;
     RECT  18.912 28.979 20.16 29.509 ;
     RECT  29.88 29.029 31.056 30.805 ;
     RECT  31.08 29.029 32.256 31.285 ;
     RECT  18.912 29.509 19.968 31.283 ;
     RECT  38.136 30.419 39.6 30.611 ;
     RECT  24.648 30.469 25.68 32.533 ;
     RECT  16.536 30.803 17.616 36.565 ;
     RECT  29.976 30.805 31.056 33.589 ;
     RECT  18.912 31.283 20.256 34.117 ;
     RECT  31.128 31.285 32.256 33.301 ;
     RECT  27.624 31.331 28.608 33.493 ;
     RECT  25.8 31.619 27.024 33.541 ;
     RECT  15.096 32.723 16.32 33.107 ;
     RECT  15.096 33.107 16.512 35.077 ;
     RECT  31.272 33.301 32.256 34.787 ;
     RECT  19.56 34.643 20.544 35.605 ;
     RECT  38.136 34.741 39.312 37.573 ;
     RECT  31.128 34.787 32.256 42.181 ;
     RECT  15.096 35.077 16.416 36.085 ;
     RECT  10.632 36.563 11.712 39.253 ;
     RECT  19.56 36.707 20.544 37.043 ;
     RECT  16.536 36.899 17.616 38.725 ;
     RECT  19.56 37.043 20.736 37.427 ;
     RECT  13.896 37.475 15.072 39.877 ;
     RECT  38.136 37.573 39.12 40.165 ;
     RECT  27.624 38.435 28.608 40.741 ;
     RECT  19.416 39.301 20.736 41.027 ;
     RECT  18.912 41.027 19.08 42.469 ;
     RECT  10.632 41.411 11.712 44.387 ;
     RECT  35.256 42.227 36.432 43.525 ;
     RECT  35.352 43.525 36.432 43.907 ;
     RECT  35.352 43.907 36.576 44.771 ;
     RECT  10.296 44.387 11.712 45.589 ;
     RECT  14.616 44.483 15.744 45.589 ;
     RECT  35.256 44.771 36.576 46.789 ;
     RECT  19.752 44.773 21.264 45.589 ;
     RECT  10.296 45.589 11.424 46.501 ;
     RECT  19.752 45.589 20.88 46.835 ;
     RECT  19.752 46.835 21.264 46.837 ;
     RECT  19.944 46.837 21.264 47.027 ;
     RECT  37.368 47.075 38.736 48.709 ;
     RECT  14.568 48.275 15.744 54.131 ;
     RECT  37.368 48.709 38.64 48.757 ;
     RECT  37.368 48.757 38.448 48.853 ;
     RECT  29.928 49.667 31.104 50.821 ;
     RECT  35.736 50.771 37.104 52.309 ;
     RECT  30.024 50.821 31.104 51.637 ;
     RECT  35.736 52.309 36.816 52.453 ;
     RECT  20.952 52.357 22.08 54.371 ;
     RECT  35.736 52.453 36.768 52.501 ;
     RECT  30.024 52.499 31.104 53.075 ;
     RECT  29.928 53.075 31.104 55.237 ;
     RECT  35.928 53.603 37.104 55.283 ;
     RECT  14.232 54.131 15.744 54.659 ;
     RECT  20.568 54.371 22.08 54.419 ;
     RECT  27 55.283 28.368 59.797 ;
     RECT  35.736 55.283 37.104 58.117 ;
     RECT  16.536 55.859 17.712 56.869 ;
     RECT  19.992 57.059 20.04 57.589 ;
     RECT  33.048 57.443 34.176 58.645 ;
     RECT  13.896 57.541 15.12 58.933 ;
     RECT  15.144 57.541 16.416 59.797 ;
     RECT  19.992 57.589 21.024 58.067 ;
     RECT  21.048 57.589 22.176 57.731 ;
     RECT  21.048 57.731 22.512 58.067 ;
     RECT  11.136 57.875 11.376 58.163 ;
     RECT  16.584 57.971 17.712 59.461 ;
     RECT  19.992 58.067 22.512 59.173 ;
     RECT  35.832 58.117 37.104 63.877 ;
     RECT  11.136 58.163 11.424 58.645 ;
     RECT  10.392 58.645 11.424 59.795 ;
     RECT  5.256 58.835 6.576 59.797 ;
     RECT  13.944 58.933 15.12 59.075 ;
     RECT  13.896 59.075 15.12 60.085 ;
     RECT  19.992 59.173 21.408 60.229 ;
     RECT  21.432 59.173 22.512 59.701 ;
     RECT  9.48 59.795 11.424 60.133 ;
     RECT  27 59.797 28.176 64.835 ;
     RECT  9.48 60.133 10.848 62.723 ;
     RECT  19.992 60.229 21.12 60.277 ;
     RECT  15.48 60.467 16.512 61.429 ;
     RECT  13.896 61.043 15.12 66.179 ;
     RECT  5.256 61.331 6.576 77.507 ;
     RECT  33.336 61.619 34.512 62.725 ;
     RECT  19.896 62.243 21.12 62.819 ;
     RECT  11.04 62.723 11.424 64.165 ;
     RECT  33.528 62.725 34.512 62.821 ;
     RECT  19.8 62.819 21.12 63.829 ;
     RECT  35.832 63.877 36.864 64.357 ;
     RECT  27 64.835 28.272 68.293 ;
     RECT  24.408 65.267 25.392 66.469 ;
     RECT  35.4 65.267 36.864 67.283 ;
     RECT  13.896 66.179 15.264 67.765 ;
     RECT  30.552 66.323 31.68 67.285 ;
     RECT  33.528 66.755 34.608 68.723 ;
     RECT  20.424 67.139 21.456 68.387 ;
     RECT  35.256 67.283 36.864 67.285 ;
     RECT  30.6 67.285 31.68 68.581 ;
     RECT  35.256 67.285 36.576 68.341 ;
     RECT  27.144 68.293 28.272 68.677 ;
     RECT  20.28 68.387 21.456 70.787 ;
     RECT  27.192 68.677 28.272 70.645 ;
     RECT  30.6 68.723 31.68 70.501 ;
     RECT  33.528 68.723 34.8 70.645 ;
     RECT  19.224 68.963 20.256 70.453 ;
     RECT  30.6 70.501 31.632 70.645 ;
     RECT  30.648 70.645 31.632 71.797 ;
     RECT  11.544 70.835 12.528 71.891 ;
     RECT  8.112 71.651 9.12 90.037 ;
     RECT  11.808 71.891 12.528 72.037 ;
     RECT  20.088 72.805 21.12 75.299 ;
     RECT  13.896 72.851 15.504 73.957 ;
     RECT  30.36 73.043 31.68 75.109 ;
     RECT  28.104 74.147 29.232 74.243 ;
     RECT  37.656 74.195 39.072 77.267 ;
     RECT  13.896 74.627 15.12 75.781 ;
     RECT  30.36 75.109 31.392 79.189 ;
     RECT  20.088 75.299 21.408 75.443 ;
     RECT  14.136 75.781 15.12 76.403 ;
     RECT  13.992 76.403 15.504 77.603 ;
     RECT  15.768 77.555 16.848 78.899 ;
     RECT  37.32 78.659 37.464 79.957 ;
     RECT  15.72 78.899 16.848 79.235 ;
     RECT  10.824 79.045 11.808 80.531 ;
     RECT  30.36 79.189 31.344 81.347 ;
     RECT  20.376 79.717 21.408 79.765 ;
     RECT  37.464 80.147 37.608 81.205 ;
     RECT  10.824 80.531 12.096 80.867 ;
     RECT  37.944 81.205 39.456 82.691 ;
     RECT  30.36 81.347 31.584 82.549 ;
     RECT  30.36 82.549 31.44 83.029 ;
     RECT  16.008 82.597 17.28 82.739 ;
     RECT  37.944 82.691 39.552 83.317 ;
     RECT  16.008 82.739 17.616 82.837 ;
     RECT  16.44 82.837 17.616 83.795 ;
     RECT  30.456 83.029 31.44 84.325 ;
     RECT  38.232 83.317 39.552 83.701 ;
     RECT  13.512 84.277 14.544 89.989 ;
     RECT  14.568 84.277 15.696 84.323 ;
     RECT  38.232 85.091 39.312 88.933 ;
     RECT  25.704 86.867 27.024 89.411 ;
     RECT  19.896 87.251 20.88 91.621 ;
     RECT  37.464 88.979 38.448 91.429 ;
     RECT  25.656 89.411 27.024 90.373 ;
     RECT  3.672 89.555 4.752 98.099 ;
     RECT  14.568 90.229 15.936 93.733 ;
     RECT  25.8 90.611 27.024 91.187 ;
     RECT  8.112 90.851 9.12 92.005 ;
     RECT  4.776 91.141 6.048 93.925 ;
     RECT  25.656 91.187 27.024 94.357 ;
     RECT  30.36 91.763 31.536 92.869 ;
     RECT  36.6 91.811 37.872 93.301 ;
     RECT  13.512 92.339 14.544 99.683 ;
     RECT  11.568 93.107 11.904 93.397 ;
     RECT  27.768 93.253 29.232 93.779 ;
     RECT  10.824 93.397 11.904 95.461 ;
     RECT  36.024 93.539 37.008 93.731 ;
     RECT  35.112 93.731 37.008 94.933 ;
     RECT  27.768 93.779 29.4 94.021 ;
     RECT  27.912 94.021 29.4 95.413 ;
     RECT  35.928 94.933 37.008 95.219 ;
     RECT  35.928 95.219 37.344 96.277 ;
     RECT  9.144 95.365 10.656 95.557 ;
     RECT  27.912 95.413 29.088 96.037 ;
     RECT  9.672 95.557 10.656 95.605 ;
     RECT  27.912 96.037 28.896 96.325 ;
     RECT  29.712 96.467 31.536 97.621 ;
     RECT  37.368 96.515 38.448 100.789 ;
     RECT  35.928 96.947 37.344 98.629 ;
     RECT  8.424 96.995 9.648 98.005 ;
     RECT  19.944 97.331 21.36 99.157 ;
     RECT  29.712 97.621 31.104 101.989 ;
     RECT  28.104 97.763 29.4 98.387 ;
     RECT  3.336 98.099 4.752 99.203 ;
     RECT  27.48 98.387 29.4 99.541 ;
     RECT  36.024 98.629 37.344 99.157 ;
     RECT  20.04 99.157 21.36 99.779 ;
     RECT  36.024 99.157 37.056 100.021 ;
     RECT  10.968 99.203 12.24 100.499 ;
     RECT  27.48 99.541 28.992 99.683 ;
     RECT  17.952 99.587 18.048 100.261 ;
     RECT  27.384 99.683 28.992 99.685 ;
     RECT  27.384 99.685 28.752 100.931 ;
     RECT  9.096 99.779 10.176 100.789 ;
     RECT  19.944 99.779 21.36 101.075 ;
     RECT  16.536 100.261 18.048 100.645 ;
     RECT  6.36 100.355 7.392 101.989 ;
     RECT  15.096 100.355 16.512 101.027 ;
     RECT  10.968 100.499 11.448 100.693 ;
     RECT  16.536 100.645 17.856 101.027 ;
     RECT  38.232 100.835 39.312 101.651 ;
     RECT  27.384 100.931 28.8 107.125 ;
     RECT  15.096 101.027 17.856 101.317 ;
     RECT  19.704 101.075 21.36 102.133 ;
     RECT  15.096 101.317 16.32 103.379 ;
     RECT  16.344 101.317 17.856 103.379 ;
     RECT  19.992 102.133 21.36 105.781 ;
     RECT  29.712 103.235 30.816 104.773 ;
     RECT  15.096 103.379 16.248 103.717 ;
     RECT  17.808 103.379 17.856 103.717 ;
     RECT  11.688 103.381 13.2 104.773 ;
     RECT  26.28 103.475 27.36 104.821 ;
     RECT  33.816 103.523 34.8 104.531 ;
     RECT  15.096 103.717 16.224 104.291 ;
     RECT  39.744 103.763 40.2 104.101 ;
     RECT  38.952 104.101 40.2 105.781 ;
     RECT  37.368 104.245 38.736 105.155 ;
     RECT  4.776 104.435 5.76 105.779 ;
     RECT  32.616 104.675 32.76 105.973 ;
     RECT  11.784 104.773 13.2 106.453 ;
     RECT  29.832 104.773 30.816 105.395 ;
     RECT  25.32 104.867 26.4 105.395 ;
     RECT  25.176 105.395 26.4 107.363 ;
     RECT  29.832 105.395 31.2 107.075 ;
     RECT  36.264 105.395 37.344 106.837 ;
     RECT  4.776 105.779 6.048 107.413 ;
     RECT  11.976 106.453 13.2 107.125 ;
     RECT  22.152 106.643 23.472 108.085 ;
     RECT  38.952 106.739 40.2 107.267 ;
     RECT  29.712 107.075 31.2 107.317 ;
     RECT  12.12 107.125 13.2 109.093 ;
     RECT  27.672 107.125 28.8 107.845 ;
     RECT  29.712 107.317 30.816 108.947 ;
     RECT  25.176 107.363 26.736 107.603 ;
     RECT  4.776 107.413 5.904 107.797 ;
     RECT  31.704 107.507 32.736 110.819 ;
     RECT  37.368 107.557 38.592 109.475 ;
     RECT  25.176 107.603 25.704 107.941 ;
     RECT  36.264 107.843 37.344 108.323 ;
     RECT  27.768 107.845 28.8 108.323 ;
     RECT  22.152 108.085 23.328 109.475 ;
     RECT  2.712 108.227 3.048 109.381 ;
     RECT  36.216 108.323 37.344 109.475 ;
     RECT  19.656 108.851 21.36 109.957 ;
     RECT  13.512 108.899 14.736 111.685 ;
     RECT  22.152 109.475 23.424 110.867 ;
     RECT  19.656 109.957 21.168 110.051 ;
     RECT  31.704 110.819 32.136 111.685 ;
     RECT  29.712 111.445 30.816 112.643 ;
     RECT  25.368 111.637 26.688 111.685 ;
     RECT  25.56 111.685 26.688 113.267 ;
     RECT  30.84 111.875 32.112 112.307 ;
     RECT  24.312 112.883 25.536 113.267 ;
     RECT  10.344 114.035 11.52 115.141 ;
     RECT  7.92 114.489 9.024 114.503 ;
  END
END ot_s81_markov_chunk7_native
END LIBRARY
